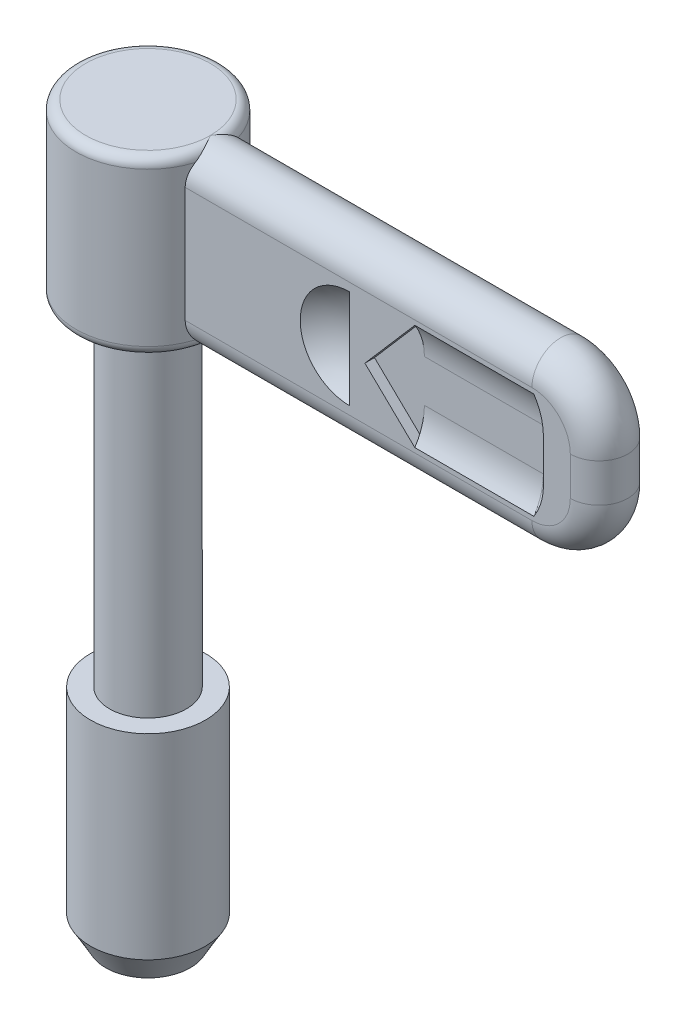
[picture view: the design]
ISO-10303-21;
HEADER;
FILE_DESCRIPTION(('STEP AP214'),'2;1');
FILE_NAME('part.step','',(''),(''),'','','');
FILE_SCHEMA(('AUTOMOTIVE_DESIGN { 1 0 10303 214 1 1 1 1 }'));
ENDSEC;
DATA;
#1=APPLICATION_CONTEXT('core data for automotive mechanical design processes');
#2=APPLICATION_PROTOCOL_DEFINITION('international standard','automotive_design',2000,#1);
#3=PRODUCT_CONTEXT('',#1,'mechanical');
#4=PRODUCT('Part','Part','',(#3));
#5=PRODUCT_RELATED_PRODUCT_CATEGORY('part','',(#4));
#6=PRODUCT_DEFINITION_FORMATION('','',#4);
#7=PRODUCT_DEFINITION_CONTEXT('part definition',#1,'design');
#8=PRODUCT_DEFINITION('design','',#6,#7);
#9=PRODUCT_DEFINITION_SHAPE('','',#8);
#10=(LENGTH_UNIT() NAMED_UNIT(*) SI_UNIT(.MILLI.,.METRE.));
#11=(NAMED_UNIT(*) PLANE_ANGLE_UNIT() SI_UNIT($,.RADIAN.));
#12=(NAMED_UNIT(*) SI_UNIT($,.STERADIAN.) SOLID_ANGLE_UNIT());
#13=UNCERTAINTY_MEASURE_WITH_UNIT(LENGTH_MEASURE(1.E-05),#10,'distance_accuracy_value','');
#14=(GEOMETRIC_REPRESENTATION_CONTEXT(3) GLOBAL_UNCERTAINTY_ASSIGNED_CONTEXT((#13)) GLOBAL_UNIT_ASSIGNED_CONTEXT((#10,
#11,#12)) REPRESENTATION_CONTEXT('',''));
#15=CARTESIAN_POINT('',(0.,0.,0.));
#16=DIRECTION('',(0.,0.,1.));
#17=DIRECTION('',(1.,0.,0.));
#18=AXIS2_PLACEMENT_3D('',#15,#16,#17);
#19=CARTESIAN_POINT('',(15.4,25.241687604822,-1.5));
#20=DIRECTION('',(-1.,0.,0.));
#21=DIRECTION('',(0.,0.,1.));
#22=AXIS2_PLACEMENT_3D('',#19,#20,#21);
#23=PLANE('',#22);
#24=CARTESIAN_POINT('',(15.4,26.9000000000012,-4.0000000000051));
#25=DIRECTION('',(1.,0.,0.));
#26=DIRECTION('',(0.,-4.16851738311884E-13,1.));
#27=AXIS2_PLACEMENT_3D('',#24,#25,#26);
#28=CIRCLE('',#27,3.0000000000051);
#29=CARTESIAN_POINT('',(15.4,26.9,-1.));
#30=VERTEX_POINT('',#29);
#31=CARTESIAN_POINT('',(15.4,25.241687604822,-1.5));
#32=VERTEX_POINT('',#31);
#33=EDGE_CURVE('E190',#30,#32,#28,.T.);
#34=ORIENTED_EDGE('',*,*,#33,.T.);
#35=DIRECTION('',(0.,0.,1.));
#36=VECTOR('',#35,1.);
#37=CARTESIAN_POINT('',(15.4,25.241687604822,-1.5));
#38=LINE('',#37,#36);
#39=CARTESIAN_POINT('',(15.4,25.241687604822,-1.));
#40=VERTEX_POINT('',#39);
#41=EDGE_CURVE('E206',#40,#32,#38,.F.);
#42=ORIENTED_EDGE('',*,*,#41,.F.);
#43=DIRECTION('',(0.,1.,0.));
#44=VECTOR('',#43,1.);
#45=CARTESIAN_POINT('',(15.4,25.241687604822,-1.));
#46=LINE('',#45,#44);
#47=EDGE_CURVE('E207',#40,#30,#46,.T.);
#48=ORIENTED_EDGE('',*,*,#47,.T.);
#49=EDGE_LOOP('',(#34,#42,#48));
#50=FACE_BOUND('',#49,.T.);
#51=ADVANCED_FACE('F14',(#50),#23,.T.);
#52=CARTESIAN_POINT('',(3.43693177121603,25.,-1.5));
#53=DIRECTION('',(0.,0.,-1.));
#54=DIRECTION('',(0.,1.,0.));
#55=AXIS2_PLACEMENT_3D('',#52,#53,#54);
#56=PLANE('',#55);
#57=DIRECTION('',(2.18195849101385E-13,1.,0.));
#58=VECTOR('',#57,1.);
#59=CARTESIAN_POINT('',(3.43693177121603,25.,-1.5));
#60=LINE('',#59,#58);
#61=CARTESIAN_POINT('',(3.43693177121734,30.9999995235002,-1.5));
#62=VERTEX_POINT('',#61);
#63=CARTESIAN_POINT('',(3.43693177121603,25.,-1.5));
#64=VERTEX_POINT('',#63);
#65=EDGE_CURVE('E421',#62,#64,#60,.F.);
#66=ORIENTED_EDGE('',*,*,#65,.F.);
#67=DIRECTION('',(1.,2.63797795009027E-08,0.));
#68=VECTOR('',#67,1.);
#69=CARTESIAN_POINT('',(3.43693177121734,30.9999995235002,-1.5));
#70=LINE('',#69,#68);
#71=CARTESIAN_POINT('',(21.5,31.,-1.5));
#72=VERTEX_POINT('',#71);
#73=EDGE_CURVE('E439',#62,#72,#70,.T.);
#74=ORIENTED_EDGE('',*,*,#73,.T.);
#75=CARTESIAN_POINT('',(21.5000000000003,29.,-1.5));
#76=DIRECTION('',(0.,0.,-1.));
#77=DIRECTION('',(-1.43884903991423E-13,1.,0.));
#78=AXIS2_PLACEMENT_3D('',#75,#76,#77);
#79=CIRCLE('',#78,1.99999999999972);
#80=CARTESIAN_POINT('',(23.5,29.,-1.5));
#81=VERTEX_POINT('',#80);
#82=EDGE_CURVE('E429',#72,#81,#79,.T.);
#83=ORIENTED_EDGE('',*,*,#82,.T.);
#84=DIRECTION('',(0.,-1.,0.));
#85=VECTOR('',#84,1.);
#86=CARTESIAN_POINT('',(23.5,29.,-1.5));
#87=LINE('',#86,#85);
#88=CARTESIAN_POINT('',(23.5,27.,-1.5));
#89=VERTEX_POINT('',#88);
#90=EDGE_CURVE('E425',#81,#89,#87,.T.);
#91=ORIENTED_EDGE('',*,*,#90,.T.);
#92=CARTESIAN_POINT('',(21.5000000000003,27.,-1.5));
#93=DIRECTION('',(0.,0.,-1.));
#94=DIRECTION('',(1.,0.,0.));
#95=AXIS2_PLACEMENT_3D('',#92,#93,#94);
#96=CIRCLE('',#95,1.99999999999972);
#97=CARTESIAN_POINT('',(21.5,25.,-1.5));
#98=VERTEX_POINT('',#97);
#99=EDGE_CURVE('E225',#89,#98,#96,.T.);
#100=ORIENTED_EDGE('',*,*,#99,.T.);
#101=DIRECTION('',(-1.,0.,0.));
#102=VECTOR('',#101,1.);
#103=CARTESIAN_POINT('',(21.5,25.,-1.5));
#104=LINE('',#103,#102);
#105=EDGE_CURVE('E222',#98,#64,#104,.T.);
#106=ORIENTED_EDGE('',*,*,#105,.T.);
#107=EDGE_LOOP('',(#66,#74,#83,#91,#100,#106));
#108=FACE_BOUND('',#107,.T.);
#109=DIRECTION('',(0.719682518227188,-0.694303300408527,0.));
#110=VECTOR('',#109,1.);
#111=CARTESIAN_POINT('',(12.8,27.75,-1.5));
#112=LINE('',#111,#110);
#113=CARTESIAN_POINT('',(12.8,27.75,-1.5));
#114=VERTEX_POINT('',#113);
#115=EDGE_CURVE('E200',#114,#32,#112,.T.);
#116=ORIENTED_EDGE('',*,*,#115,.T.);
#117=DIRECTION('',(1.,0.,0.));
#118=VECTOR('',#117,1.);
#119=CARTESIAN_POINT('',(15.4,25.241687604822,-1.5));
#120=LINE('',#119,#118);
#121=CARTESIAN_POINT('',(21.6,25.241687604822,-1.5));
#122=VERTEX_POINT('',#121);
#123=EDGE_CURVE('E186',#32,#122,#120,.T.);
#124=ORIENTED_EDGE('',*,*,#123,.T.);
#125=CARTESIAN_POINT('',(22.1,26.9000000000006,-1.5));
#126=CARTESIAN_POINT('',(22.0997802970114,26.8633870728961,-1.5));
#127=CARTESIAN_POINT('',(22.0989547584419,26.8267766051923,-1.5));
#128=CARTESIAN_POINT('',(22.0960619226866,26.7535959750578,-1.5));
#129=CARTESIAN_POINT('',(22.0939943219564,26.7170258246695,-1.5));
#130=CARTESIAN_POINT('',(22.088587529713,26.6439815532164,-1.5));
#131=CARTESIAN_POINT('',(22.0852484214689,26.6075074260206,-1.5));
#132=CARTESIAN_POINT('',(22.077276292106,26.5347099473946,-1.5));
#133=CARTESIAN_POINT('',(22.0726435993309,26.4983865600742,-1.5));
#134=CARTESIAN_POINT('',(22.0620680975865,26.4259432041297,-1.5));
#135=CARTESIAN_POINT('',(22.0561257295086,26.3898231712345,-1.5));
#136=CARTESIAN_POINT('',(22.0429212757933,26.3178373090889,-1.5));
#137=CARTESIAN_POINT('',(22.0356596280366,26.2819713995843,-1.5));
#138=CARTESIAN_POINT('',(22.0198135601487,26.2105425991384,-1.5));
#139=CARTESIAN_POINT('',(22.0112294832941,26.1749796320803,-1.5));
#140=CARTESIAN_POINT('',(21.9927421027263,26.1042035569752,-1.5));
#141=CARTESIAN_POINT('',(21.9828389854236,26.0689904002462,-1.5));
#142=CARTESIAN_POINT('',(21.9617236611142,25.9989587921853,-1.5));
#143=CARTESIAN_POINT('',(21.9505114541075,25.9641403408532,-1.5));
#144=CARTESIAN_POINT('',(21.9267946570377,25.894940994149,-1.5));
#145=CARTESIAN_POINT('',(21.9142898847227,25.8605601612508,-1.5));
#146=CARTESIAN_POINT('',(21.8880111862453,25.7922769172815,-1.5));
#147=CARTESIAN_POINT('',(21.8742369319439,25.7583746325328,-1.5));
#148=CARTESIAN_POINT('',(21.8454489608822,25.6910873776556,-1.5));
#149=CARTESIAN_POINT('',(21.830434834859,25.6577025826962,-1.5));
#150=CARTESIAN_POINT('',(21.7992031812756,25.5914872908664,-1.5));
#151=CARTESIAN_POINT('',(21.7829852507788,25.5586569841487,-1.5));
#152=CARTESIAN_POINT('',(21.7493883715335,25.4935856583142,-1.5));
#153=CARTESIAN_POINT('',(21.7320091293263,25.4613447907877,-1.5));
#154=CARTESIAN_POINT('',(21.6961380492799,25.3974858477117,-1.5));
#155=CARTESIAN_POINT('',(21.677646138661,25.3658678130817,-1.5));
#156=CARTESIAN_POINT('',(21.6396047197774,25.3032848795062,-1.5));
#157=CARTESIAN_POINT('',(21.6200554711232,25.2723198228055,-1.5));
#158=CARTESIAN_POINT('',(21.6,25.241687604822,-1.5));
#159=B_SPLINE_CURVE_WITH_KNOTS('',3,(#125,#126,#127,#128,#129,#130,#131,#132,#133,#134,#135,
#136,#137,#138,#139,#140,#141,#142,#143,#144,#145,#146,#147,#148,#149,#150,#151,#152,#153,#154,
#155,#156,#157,#158),.UNSPECIFIED.,.F.,.F.,(4,2,2,2,2,2,2,2,2,2,2,2,2,2,2,2,4),(0.,
0.109837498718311,0.219701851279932,0.329559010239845,0.439388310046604,0.549180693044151,
0.658936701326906,0.768664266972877,0.878376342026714,0.988088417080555,1.09781598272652,
1.20757199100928,1.31736437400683,1.42719367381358,1.5370508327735,1.64691518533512,
1.75675268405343),.UNSPECIFIED.);
#160=CARTESIAN_POINT('',(22.1,26.9000000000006,-1.5));
#161=VERTEX_POINT('',#160);
#162=EDGE_CURVE('E199',#161,#122,#159,.T.);
#163=ORIENTED_EDGE('',*,*,#162,.F.);
#164=DIRECTION('',(0.,1.,0.));
#165=VECTOR('',#164,1.);
#166=CARTESIAN_POINT('',(22.1,26.9000000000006,-1.5));
#167=LINE('',#166,#165);
#168=CARTESIAN_POINT('',(22.1,29.1,-1.5));
#169=VERTEX_POINT('',#168);
#170=EDGE_CURVE('E240',#161,#169,#167,.T.);
#171=ORIENTED_EDGE('',*,*,#170,.T.);
#172=CARTESIAN_POINT('',(21.6,30.758312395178,-1.5));
#173=CARTESIAN_POINT('',(21.6200554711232,30.7276801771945,-1.5));
#174=CARTESIAN_POINT('',(21.6396047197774,30.6967151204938,-1.5));
#175=CARTESIAN_POINT('',(21.677646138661,30.6341321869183,-1.5));
#176=CARTESIAN_POINT('',(21.6961380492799,30.6025141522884,-1.5));
#177=CARTESIAN_POINT('',(21.7320091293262,30.5386552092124,-1.5));
#178=CARTESIAN_POINT('',(21.7493883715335,30.5064143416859,-1.5));
#179=CARTESIAN_POINT('',(21.7829852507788,30.4413430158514,-1.5));
#180=CARTESIAN_POINT('',(21.7992031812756,30.4085127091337,-1.5));
#181=CARTESIAN_POINT('',(21.8304348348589,30.342297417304,-1.5));
#182=CARTESIAN_POINT('',(21.8454489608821,30.3089126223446,-1.5));
#183=CARTESIAN_POINT('',(21.8742369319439,30.2416253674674,-1.5));
#184=CARTESIAN_POINT('',(21.8880111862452,30.2077230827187,-1.5));
#185=CARTESIAN_POINT('',(21.9142898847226,30.1394398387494,-1.5));
#186=CARTESIAN_POINT('',(21.9267946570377,30.1050590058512,-1.5));
#187=CARTESIAN_POINT('',(21.9505114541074,30.035859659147,-1.5));
#188=CARTESIAN_POINT('',(21.9617236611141,30.001041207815,-1.5));
#189=CARTESIAN_POINT('',(21.9828389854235,29.9310095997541,-1.5));
#190=CARTESIAN_POINT('',(21.9927421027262,29.8957964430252,-1.5));
#191=CARTESIAN_POINT('',(22.011229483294,29.8250203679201,-1.5));
#192=CARTESIAN_POINT('',(22.0198135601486,29.789457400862,-1.5));
#193=CARTESIAN_POINT('',(22.0356596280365,29.7180286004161,-1.5));
#194=CARTESIAN_POINT('',(22.0429212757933,29.6821626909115,-1.5));
#195=CARTESIAN_POINT('',(22.0561257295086,29.6101768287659,-1.5));
#196=CARTESIAN_POINT('',(22.0620680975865,29.5740567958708,-1.5));
#197=CARTESIAN_POINT('',(22.0726435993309,29.5016134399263,-1.5));
#198=CARTESIAN_POINT('',(22.077276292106,29.4652900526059,-1.5));
#199=CARTESIAN_POINT('',(22.0852484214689,29.3924925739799,-1.5));
#200=CARTESIAN_POINT('',(22.088587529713,29.3560184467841,-1.5));
#201=CARTESIAN_POINT('',(22.0939943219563,29.282974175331,-1.5));
#202=CARTESIAN_POINT('',(22.0960619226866,29.2464040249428,-1.5));
#203=CARTESIAN_POINT('',(22.0989547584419,29.1732233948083,-1.5));
#204=CARTESIAN_POINT('',(22.0997802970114,29.1366129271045,-1.5));
#205=CARTESIAN_POINT('',(22.1,29.1,-1.5));
#206=B_SPLINE_CURVE_WITH_KNOTS('',3,(#172,#173,#174,#175,#176,#177,#178,#179,#180,#181,#182,
#183,#184,#185,#186,#187,#188,#189,#190,#191,#192,#193,#194,#195,#196,#197,#198,#199,#200,#201,
#202,#203,#204,#205),.UNSPECIFIED.,.F.,.F.,(4,2,2,2,2,2,2,2,2,2,2,2,2,2,2,2,4),(0.,
0.109837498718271,0.219701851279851,0.329559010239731,0.439388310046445,0.549180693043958,
0.658936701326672,0.768664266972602,0.878376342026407,0.988088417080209,1.09781598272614,
1.20757199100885,1.31736437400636,1.42719367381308,1.53705083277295,1.64691518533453,
1.7567526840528),.UNSPECIFIED.);
#207=CARTESIAN_POINT('',(21.6,30.758312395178,-1.5));
#208=VERTEX_POINT('',#207);
#209=EDGE_CURVE('E678',#208,#169,#206,.T.);
#210=ORIENTED_EDGE('',*,*,#209,.F.);
#211=DIRECTION('',(-1.,0.,0.));
#212=VECTOR('',#211,1.);
#213=CARTESIAN_POINT('',(21.6,30.758312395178,-1.5));
#214=LINE('',#213,#212);
#215=CARTESIAN_POINT('',(15.4,30.758312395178,-1.5));
#216=VERTEX_POINT('',#215);
#217=EDGE_CURVE('E1399',#216,#208,#214,.F.);
#218=ORIENTED_EDGE('',*,*,#217,.F.);
#219=DIRECTION('',(-0.653895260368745,-0.756585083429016,0.));
#220=VECTOR('',#219,1.);
#221=CARTESIAN_POINT('',(15.4,30.758312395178,-1.5));
#222=LINE('',#221,#220);
#223=EDGE_CURVE('E221',#216,#114,#222,.T.);
#224=ORIENTED_EDGE('',*,*,#223,.T.);
#225=EDGE_LOOP('',(#116,#124,#163,#171,#210,#218,#224));
#226=FACE_BOUND('',#225,.T.);
#227=DIRECTION('',(0.,1.,0.));
#228=VECTOR('',#227,1.);
#229=CARTESIAN_POINT('',(12.,25.430953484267,-1.5));
#230=LINE('',#229,#228);
#231=CARTESIAN_POINT('',(12.,25.430953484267,-1.5));
#232=VERTEX_POINT('',#231);
#233=CARTESIAN_POINT('',(12.,30.569046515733,-1.5));
#234=VERTEX_POINT('',#233);
#235=EDGE_CURVE('E1397',#232,#234,#230,.T.);
#236=ORIENTED_EDGE('',*,*,#235,.T.);
#237=CARTESIAN_POINT('',(12.,30.569046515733,-1.5));
#238=CARTESIAN_POINT('',(11.8604662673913,30.569046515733,-1.5));
#239=CARTESIAN_POINT('',(11.7251672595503,30.558257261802,-1.5));
#240=CARTESIAN_POINT('',(11.4614528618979,30.5161788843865,-1.5));
#241=CARTESIAN_POINT('',(11.3330374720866,30.4848897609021,-1.5));
#242=CARTESIAN_POINT('',(10.9180636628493,30.349608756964,-1.5));
#243=CARTESIAN_POINT('',(10.6751190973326,30.2176773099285,-1.5));
#244=CARTESIAN_POINT('',(10.1926951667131,29.8569578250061,-1.5));
#245=CARTESIAN_POINT('',(9.96213756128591,29.6004957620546,-1.5));
#246=CARTESIAN_POINT('',(9.19003735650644,28.3008382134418,-1.5));
#247=CARTESIAN_POINT('',(9.35292610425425,27.0138934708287,-1.5));
#248=CARTESIAN_POINT('',(10.3717569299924,25.9950626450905,-1.5));
#249=CARTESIAN_POINT('',(10.5851466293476,25.8366086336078,-1.5));
#250=CARTESIAN_POINT('',(11.0064475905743,25.6232428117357,-1.5));
#251=CARTESIAN_POINT('',(11.1899669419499,25.55356956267,-1.5));
#252=CARTESIAN_POINT('',(11.58418094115,25.4558125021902,-1.5));
#253=CARTESIAN_POINT('',(11.7896180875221,25.4309534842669,-1.5));
#254=CARTESIAN_POINT('',(12.,25.4309534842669,-1.5));
#255=B_SPLINE_CURVE_WITH_KNOTS('',3,(#237,#238,#239,#240,#241,#242,#243,#244,#245,#246,#247,
#248,#249,#250,#251,#252,#253,#254),.UNSPECIFIED.,.F.,.F.,(4,2,2,2,2,2,2,2,4),(0.,
0.042961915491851,0.0859238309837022,0.184717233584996,0.310914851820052,0.758114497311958,
0.859535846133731,0.928561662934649,1.),.UNSPECIFIED.);
#256=EDGE_CURVE('E274',#234,#232,#255,.T.);
#257=ORIENTED_EDGE('',*,*,#256,.T.);
#258=EDGE_LOOP('',(#236,#257));
#259=FACE_BOUND('',#258,.T.);
#260=ADVANCED_FACE('F217',(#108,#226,#259),#56,.T.);
#261=CARTESIAN_POINT('',(3.43693177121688,25.,1.5));
#262=DIRECTION('',(0.,0.,1.));
#263=DIRECTION('',(1.,0.,0.));
#264=AXIS2_PLACEMENT_3D('',#261,#262,#263);
#265=PLANE('',#264);
#266=DIRECTION('',(-1.,-1.82876122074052E-08,0.));
#267=VECTOR('',#266,1.);
#268=CARTESIAN_POINT('',(21.5,31.,1.5));
#269=LINE('',#268,#267);
#270=CARTESIAN_POINT('',(21.5,31.,1.5));
#271=VERTEX_POINT('',#270);
#272=CARTESIAN_POINT('',(3.4369317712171,30.9999996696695,1.5));
#273=VERTEX_POINT('',#272);
#274=EDGE_CURVE('E265',#271,#273,#269,.T.);
#275=ORIENTED_EDGE('',*,*,#274,.T.);
#276=DIRECTION('',(0.,-1.,0.));
#277=VECTOR('',#276,1.);
#278=CARTESIAN_POINT('',(3.4369317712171,30.9999996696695,1.5));
#279=LINE('',#278,#277);
#280=CARTESIAN_POINT('',(3.43693177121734,25.0000004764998,1.5));
#281=VERTEX_POINT('',#280);
#282=EDGE_CURVE('E273',#273,#281,#279,.T.);
#283=ORIENTED_EDGE('',*,*,#282,.T.);
#284=DIRECTION('',(1.,-2.63797796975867E-08,0.));
#285=VECTOR('',#284,1.);
#286=CARTESIAN_POINT('',(3.43693177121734,25.0000004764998,1.5));
#287=LINE('',#286,#285);
#288=CARTESIAN_POINT('',(21.5,25.,1.5));
#289=VERTEX_POINT('',#288);
#290=EDGE_CURVE('E279',#281,#289,#287,.T.);
#291=ORIENTED_EDGE('',*,*,#290,.T.);
#292=CARTESIAN_POINT('',(21.5000000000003,27.,1.5));
#293=DIRECTION('',(0.,0.,1.));
#294=DIRECTION('',(-1.59872115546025E-13,-1.,0.));
#295=AXIS2_PLACEMENT_3D('',#292,#293,#294);
#296=CIRCLE('',#295,1.99999999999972);
#297=CARTESIAN_POINT('',(23.5,27.,1.5));
#298=VERTEX_POINT('',#297);
#299=EDGE_CURVE('E284',#289,#298,#296,.T.);
#300=ORIENTED_EDGE('',*,*,#299,.T.);
#301=DIRECTION('',(0.,1.,0.));
#302=VECTOR('',#301,1.);
#303=CARTESIAN_POINT('',(23.5,27.,1.5));
#304=LINE('',#303,#302);
#305=CARTESIAN_POINT('',(23.5,29.,1.5));
#306=VERTEX_POINT('',#305);
#307=EDGE_CURVE('E289',#298,#306,#304,.T.);
#308=ORIENTED_EDGE('',*,*,#307,.T.);
#309=CARTESIAN_POINT('',(21.5000000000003,29.,1.5));
#310=DIRECTION('',(0.,0.,1.));
#311=DIRECTION('',(1.,0.,0.));
#312=AXIS2_PLACEMENT_3D('',#309,#310,#311);
#313=CIRCLE('',#312,1.99999999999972);
#314=EDGE_CURVE('E294',#306,#271,#313,.T.);
#315=ORIENTED_EDGE('',*,*,#314,.T.);
#316=EDGE_LOOP('',(#275,#283,#291,#300,#308,#315));
#317=FACE_BOUND('',#316,.T.);
#318=DIRECTION('',(0.653895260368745,0.756585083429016,0.));
#319=VECTOR('',#318,1.);
#320=CARTESIAN_POINT('',(12.8,27.75,1.5));
#321=LINE('',#320,#319);
#322=CARTESIAN_POINT('',(15.4,30.758312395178,1.5));
#323=VERTEX_POINT('',#322);
#324=CARTESIAN_POINT('',(12.8,27.75,1.5));
#325=VERTEX_POINT('',#324);
#326=EDGE_CURVE('E299',#323,#325,#321,.F.);
#327=ORIENTED_EDGE('',*,*,#326,.F.);
#328=DIRECTION('',(1.,0.,0.));
#329=VECTOR('',#328,1.);
#330=CARTESIAN_POINT('',(15.4,30.758312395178,1.5));
#331=LINE('',#330,#329);
#332=CARTESIAN_POINT('',(21.6,30.758312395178,1.5));
#333=VERTEX_POINT('',#332);
#334=EDGE_CURVE('E304',#323,#333,#331,.T.);
#335=ORIENTED_EDGE('',*,*,#334,.T.);
#336=CARTESIAN_POINT('',(22.1,29.0999999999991,1.5));
#337=CARTESIAN_POINT('',(22.0997802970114,29.1366129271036,1.5));
#338=CARTESIAN_POINT('',(22.0989547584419,29.1732233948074,1.5));
#339=CARTESIAN_POINT('',(22.0960619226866,29.246404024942,1.5));
#340=CARTESIAN_POINT('',(22.0939943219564,29.2829741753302,1.5));
#341=CARTESIAN_POINT('',(22.088587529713,29.3560184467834,1.5));
#342=CARTESIAN_POINT('',(22.085248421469,29.3924925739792,1.5));
#343=CARTESIAN_POINT('',(22.0772762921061,29.4652900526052,1.5));
#344=CARTESIAN_POINT('',(22.072643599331,29.5016134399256,1.5));
#345=CARTESIAN_POINT('',(22.0620680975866,29.5740567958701,1.5));
#346=CARTESIAN_POINT('',(22.0561257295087,29.6101768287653,1.5));
#347=CARTESIAN_POINT('',(22.0429212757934,29.6821626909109,1.5));
#348=CARTESIAN_POINT('',(22.0356596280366,29.7180286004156,1.5));
#349=CARTESIAN_POINT('',(22.0198135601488,29.7894574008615,1.5));
#350=CARTESIAN_POINT('',(22.0112294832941,29.8250203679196,1.5));
#351=CARTESIAN_POINT('',(21.9927421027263,29.8957964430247,1.5));
#352=CARTESIAN_POINT('',(21.9828389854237,29.9310095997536,1.5));
#353=CARTESIAN_POINT('',(21.9617236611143,30.0010412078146,1.5));
#354=CARTESIAN_POINT('',(21.9505114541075,30.0358596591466,1.5));
#355=CARTESIAN_POINT('',(21.9267946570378,30.1050590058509,1.5));
#356=CARTESIAN_POINT('',(21.9142898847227,30.1394398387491,1.5));
#357=CARTESIAN_POINT('',(21.8880111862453,30.2077230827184,1.5));
#358=CARTESIAN_POINT('',(21.874236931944,30.2416253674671,1.5));
#359=CARTESIAN_POINT('',(21.8454489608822,30.3089126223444,1.5));
#360=CARTESIAN_POINT('',(21.830434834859,30.3422974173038,1.5));
#361=CARTESIAN_POINT('',(21.7992031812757,30.4085127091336,1.5));
#362=CARTESIAN_POINT('',(21.7829852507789,30.4413430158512,1.5));
#363=CARTESIAN_POINT('',(21.7493883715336,30.5064143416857,1.5));
#364=CARTESIAN_POINT('',(21.7320091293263,30.5386552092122,1.5));
#365=CARTESIAN_POINT('',(21.6961380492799,30.6025141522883,1.5));
#366=CARTESIAN_POINT('',(21.677646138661,30.6341321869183,1.5));
#367=CARTESIAN_POINT('',(21.6396047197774,30.6967151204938,1.5));
#368=CARTESIAN_POINT('',(21.6200554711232,30.7276801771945,1.5));
#369=CARTESIAN_POINT('',(21.6,30.758312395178,1.5));
#370=B_SPLINE_CURVE_WITH_KNOTS('',3,(#336,#337,#338,#339,#340,#341,#342,#343,#344,#345,#346,
#347,#348,#349,#350,#351,#352,#353,#354,#355,#356,#357,#358,#359,#360,#361,#362,#363,#364,#365,
#366,#367,#368,#369),.UNSPECIFIED.,.F.,.F.,(4,2,2,2,2,2,2,2,2,2,2,2,2,2,2,2,4),(0.,
0.109837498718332,0.21970185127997,0.329559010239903,0.439388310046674,0.549180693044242,
0.658936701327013,0.768664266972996,0.878376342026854,0.988088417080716,1.0978159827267,
1.20757199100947,1.31736437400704,1.42719367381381,1.53705083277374,1.64691518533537,
1.7567526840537),.UNSPECIFIED.);
#371=CARTESIAN_POINT('',(22.1,29.0999999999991,1.5));
#372=VERTEX_POINT('',#371);
#373=EDGE_CURVE('E309',#372,#333,#370,.T.);
#374=ORIENTED_EDGE('',*,*,#373,.F.);
#375=DIRECTION('',(0.,-1.,0.));
#376=VECTOR('',#375,1.);
#377=CARTESIAN_POINT('',(22.1,29.0999999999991,1.5));
#378=LINE('',#377,#376);
#379=CARTESIAN_POINT('',(22.1,26.9,1.5));
#380=VERTEX_POINT('',#379);
#381=EDGE_CURVE('E319',#372,#380,#378,.T.);
#382=ORIENTED_EDGE('',*,*,#381,.T.);
#383=CARTESIAN_POINT('',(21.6,25.241687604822,1.5));
#384=CARTESIAN_POINT('',(21.6200554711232,25.2723198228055,1.5));
#385=CARTESIAN_POINT('',(21.6396047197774,25.3032848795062,1.5));
#386=CARTESIAN_POINT('',(21.677646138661,25.3658678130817,1.5));
#387=CARTESIAN_POINT('',(21.6961380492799,25.3974858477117,1.5));
#388=CARTESIAN_POINT('',(21.7320091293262,25.4613447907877,1.5));
#389=CARTESIAN_POINT('',(21.7493883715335,25.4935856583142,1.5));
#390=CARTESIAN_POINT('',(21.7829852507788,25.5586569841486,1.5));
#391=CARTESIAN_POINT('',(21.7992031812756,25.5914872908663,1.5));
#392=CARTESIAN_POINT('',(21.830434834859,25.6577025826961,1.5));
#393=CARTESIAN_POINT('',(21.8454489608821,25.6910873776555,1.5));
#394=CARTESIAN_POINT('',(21.8742369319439,25.7583746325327,1.5));
#395=CARTESIAN_POINT('',(21.8880111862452,25.7922769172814,1.5));
#396=CARTESIAN_POINT('',(21.9142898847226,25.8605601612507,1.5));
#397=CARTESIAN_POINT('',(21.9267946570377,25.8949409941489,1.5));
#398=CARTESIAN_POINT('',(21.9505114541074,25.9641403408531,1.5));
#399=CARTESIAN_POINT('',(21.9617236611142,25.9989587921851,1.5));
#400=CARTESIAN_POINT('',(21.9828389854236,26.0689904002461,1.5));
#401=CARTESIAN_POINT('',(21.9927421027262,26.104203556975,1.5));
#402=CARTESIAN_POINT('',(22.011229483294,26.1749796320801,1.5));
#403=CARTESIAN_POINT('',(22.0198135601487,26.2105425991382,1.5));
#404=CARTESIAN_POINT('',(22.0356596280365,26.281971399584,1.5));
#405=CARTESIAN_POINT('',(22.0429212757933,26.3178373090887,1.5));
#406=CARTESIAN_POINT('',(22.0561257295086,26.3898231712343,1.5));
#407=CARTESIAN_POINT('',(22.0620680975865,26.4259432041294,1.5));
#408=CARTESIAN_POINT('',(22.0726435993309,26.4983865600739,1.5));
#409=CARTESIAN_POINT('',(22.077276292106,26.5347099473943,1.5));
#410=CARTESIAN_POINT('',(22.0852484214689,26.6075074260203,1.5));
#411=CARTESIAN_POINT('',(22.088587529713,26.6439815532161,1.5));
#412=CARTESIAN_POINT('',(22.0939943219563,26.7170258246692,1.5));
#413=CARTESIAN_POINT('',(22.0960619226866,26.7535959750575,1.5));
#414=CARTESIAN_POINT('',(22.0989547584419,26.826776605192,1.5));
#415=CARTESIAN_POINT('',(22.0997802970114,26.8633870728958,1.5));
#416=CARTESIAN_POINT('',(22.1,26.9000000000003,1.5));
#417=B_SPLINE_CURVE_WITH_KNOTS('',3,(#383,#384,#385,#386,#387,#388,#389,#390,#391,#392,#393,
#394,#395,#396,#397,#398,#399,#400,#401,#402,#403,#404,#405,#406,#407,#408,#409,#410,#411,#412,
#413,#414,#415,#416),.UNSPECIFIED.,.F.,.F.,(4,2,2,2,2,2,2,2,2,2,2,2,2,2,2,2,4),(0.,
0.109837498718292,0.219701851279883,0.329559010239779,0.439388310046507,0.549180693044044,
0.658936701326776,0.768664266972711,0.878376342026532,0.988088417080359,1.0978159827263,
1.20757199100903,1.31736437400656,1.42719367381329,1.53705083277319,1.64691518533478,
1.75675268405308),.UNSPECIFIED.);
#418=CARTESIAN_POINT('',(21.6,25.241687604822,1.5));
#419=VERTEX_POINT('',#418);
#420=EDGE_CURVE('E326',#419,#380,#417,.T.);
#421=ORIENTED_EDGE('',*,*,#420,.F.);
#422=DIRECTION('',(-1.,0.,0.));
#423=VECTOR('',#422,1.);
#424=CARTESIAN_POINT('',(21.6,25.241687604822,1.5));
#425=LINE('',#424,#423);
#426=CARTESIAN_POINT('',(15.4,25.241687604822,1.5));
#427=VERTEX_POINT('',#426);
#428=EDGE_CURVE('E336',#427,#419,#425,.F.);
#429=ORIENTED_EDGE('',*,*,#428,.F.);
#430=DIRECTION('',(-0.719682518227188,0.694303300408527,0.));
#431=VECTOR('',#430,1.);
#432=CARTESIAN_POINT('',(15.4,25.241687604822,1.5));
#433=LINE('',#432,#431);
#434=EDGE_CURVE('E343',#325,#427,#433,.F.);
#435=ORIENTED_EDGE('',*,*,#434,.F.);
#436=EDGE_LOOP('',(#327,#335,#374,#382,#421,#429,#435));
#437=FACE_BOUND('',#436,.T.);
#438=CARTESIAN_POINT('',(12.,30.569046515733,1.5));
#439=CARTESIAN_POINT('',(11.9582370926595,30.5690491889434,1.50000165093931));
#440=CARTESIAN_POINT('',(11.9164737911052,30.5680358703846,1.50000705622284));
#441=CARTESIAN_POINT('',(11.8333649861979,30.5639908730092,1.50001785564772));
#442=CARTESIAN_POINT('',(11.7920187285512,30.5609746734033,1.5000232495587));
#443=CARTESIAN_POINT('',(11.7097099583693,30.552955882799,1.50002675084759));
#444=CARTESIAN_POINT('',(11.6687465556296,30.5479624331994,1.50002489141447));
#445=CARTESIAN_POINT('',(11.5871842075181,30.5360141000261,1.50001585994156));
#446=CARTESIAN_POINT('',(11.5465847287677,30.5290628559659,1.50000869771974));
#447=CARTESIAN_POINT('',(11.4657484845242,30.5132128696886,1.49999399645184));
#448=CARTESIAN_POINT('',(11.4255118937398,30.5043132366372,1.49998645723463));
#449=CARTESIAN_POINT('',(11.3454198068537,30.4845716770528,1.49997618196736));
#450=CARTESIAN_POINT('',(11.3055654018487,30.4737253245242,1.49997345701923));
#451=CARTESIAN_POINT('',(11.2262777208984,30.4500884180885,1.49997532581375));
#452=CARTESIAN_POINT('',(11.1868465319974,30.4372908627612,1.49997994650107));
#453=CARTESIAN_POINT('',(11.1084689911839,30.4097413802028,1.49999065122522));
#454=CARTESIAN_POINT('',(11.0695257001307,30.3949807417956,1.49999674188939));
#455=CARTESIAN_POINT('',(10.9923719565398,30.3635644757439,1.50000265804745));
#456=CARTESIAN_POINT('',(10.9541621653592,30.3469072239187,1.50000247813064));
#457=CARTESIAN_POINT('',(10.8787589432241,30.3118282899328,1.50000176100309));
#458=CARTESIAN_POINT('',(10.8415618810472,30.2934144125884,1.50000122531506));
#459=CARTESIAN_POINT('',(10.7681900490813,30.2548440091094,1.49999346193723));
#460=CARTESIAN_POINT('',(10.7320131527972,30.2346915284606,1.49998624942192));
#461=CARTESIAN_POINT('',(10.66070034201,30.19267111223,1.49996757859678));
#462=CARTESIAN_POINT('',(10.6255637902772,30.1708042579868,1.49995612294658));
#463=CARTESIAN_POINT('',(10.5563669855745,30.1253840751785,1.49993212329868));
#464=CARTESIAN_POINT('',(10.5223074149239,30.1018297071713,1.49991957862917));
#465=CARTESIAN_POINT('',(10.4553136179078,30.0530680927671,1.49989741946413));
#466=CARTESIAN_POINT('',(10.4223811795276,30.0278583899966,1.49988780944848));
#467=CARTESIAN_POINT('',(10.3577022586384,29.9758249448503,1.49987495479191));
#468=CARTESIAN_POINT('',(10.3259584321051,29.9489979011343,1.4998717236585));
#469=CARTESIAN_POINT('',(10.2637264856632,29.8937748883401,1.49987396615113));
#470=CARTESIAN_POINT('',(10.2332416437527,29.865375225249,1.49987946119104));
#471=CARTESIAN_POINT('',(10.1736041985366,29.8070590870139,1.49990005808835));
#472=CARTESIAN_POINT('',(10.1444552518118,29.7771388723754,1.49991518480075));
#473=CARTESIAN_POINT('',(10.0875705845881,29.7158413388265,1.49995446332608));
#474=CARTESIAN_POINT('',(10.0598386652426,29.6844604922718,1.49997863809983));
#475=CARTESIAN_POINT('',(10.0058712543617,29.6203094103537,1.50003408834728));
#476=CARTESIAN_POINT('',(9.97963948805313,29.5875360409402,1.50006538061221));
#477=CARTESIAN_POINT('',(9.92875566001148,29.5206758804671,1.50013208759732));
#478=CARTESIAN_POINT('',(9.90410704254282,29.4865864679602,1.50016751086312));
#479=CARTESIAN_POINT('',(9.85647084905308,29.4171785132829,1.50023883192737));
#480=CARTESIAN_POINT('',(9.83348624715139,29.3818579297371,1.50027473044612));
#481=CARTESIAN_POINT('',(9.78925560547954,29.3100801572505,1.50034312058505));
#482=CARTESIAN_POINT('',(9.76801189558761,29.2736215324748,1.50037560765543));
#483=CARTESIAN_POINT('',(9.72733501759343,29.1996681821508,1.50043350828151));
#484=CARTESIAN_POINT('',(9.70790337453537,29.1621726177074,1.50045891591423));
#485=CARTESIAN_POINT('',(9.67091550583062,29.0862534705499,1.50049963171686));
#486=CARTESIAN_POINT('',(9.65335985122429,29.0478296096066,1.50051493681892));
#487=CARTESIAN_POINT('',(9.62018033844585,28.9701689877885,1.50053343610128));
#488=CARTESIAN_POINT('',(9.60455595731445,28.9309324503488,1.50053663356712));
#489=CARTESIAN_POINT('',(9.5752856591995,28.85176796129,1.50053021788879));
#490=CARTESIAN_POINT('',(9.56163799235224,28.8118406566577,1.50052061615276));
#491=CARTESIAN_POINT('',(9.53635704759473,28.7314217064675,1.50048941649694));
#492=CARTESIAN_POINT('',(9.52472066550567,28.6909310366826,1.50046783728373));
#493=CARTESIAN_POINT('',(9.50348663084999,28.6095171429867,1.5004151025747));
#494=CARTESIAN_POINT('',(9.49388439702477,28.5685951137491,1.50038396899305));
#495=CARTESIAN_POINT('',(9.4767307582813,28.4864540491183,1.50031613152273));
#496=CARTESIAN_POINT('',(9.469173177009,28.4452363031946,1.50027944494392));
#497=CARTESIAN_POINT('',(9.45610826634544,28.362642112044,1.50020592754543));
#498=CARTESIAN_POINT('',(9.45059305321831,28.3212669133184,1.50016909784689));
#499=CARTESIAN_POINT('',(9.44159928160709,28.238497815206,1.50010194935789));
#500=CARTESIAN_POINT('',(9.43811102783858,28.1971049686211,1.50007160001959));
#501=CARTESIAN_POINT('',(9.43314479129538,28.1144412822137,1.50002464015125));
#502=CARTESIAN_POINT('',(9.43165520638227,28.0731711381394,1.50000795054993));
#503=CARTESIAN_POINT('',(9.4306439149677,27.9907111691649,1.49999662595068));
#504=CARTESIAN_POINT('',(9.4311172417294,27.9495214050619,1.50000193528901));
#505=CARTESIAN_POINT('',(9.43403811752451,27.8669064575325,1.5000273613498));
#506=CARTESIAN_POINT('',(9.43650025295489,27.8254817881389,1.50004758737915));
#507=CARTESIAN_POINT('',(9.44344068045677,27.7425213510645,1.50009759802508));
#508=CARTESIAN_POINT('',(9.44793240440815,27.7009867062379,1.5001274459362));
#509=CARTESIAN_POINT('',(9.4589618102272,27.6179533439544,1.50019123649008));
#510=CARTESIAN_POINT('',(9.4655107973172,27.5764561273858,1.50022520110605));
#511=CARTESIAN_POINT('',(9.48067047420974,27.4936440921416,1.50029243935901));
#512=CARTESIAN_POINT('',(9.48929043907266,27.4523309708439,1.50032570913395));
#513=CARTESIAN_POINT('',(9.50859396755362,27.3700318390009,1.50038770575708));
#514=CARTESIAN_POINT('',(9.5192848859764,27.3290475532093,1.50041641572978));
#515=CARTESIAN_POINT('',(9.54271864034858,27.2475479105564,1.50046665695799));
#516=CARTESIAN_POINT('',(9.55546703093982,27.2070341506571,1.50048816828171));
#517=CARTESIAN_POINT('',(9.58299100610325,27.1266133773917,1.50052270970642));
#518=CARTESIAN_POINT('',(9.59777047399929,27.0867076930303,1.50053572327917));
#519=CARTESIAN_POINT('',(9.62931957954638,27.0076358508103,1.50055330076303));
#520=CARTESIAN_POINT('',(9.64609156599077,26.968470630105,1.50055785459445));
#521=CARTESIAN_POINT('',(9.68157734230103,26.8910065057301,1.50055975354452));
#522=CARTESIAN_POINT('',(9.70029209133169,26.8527080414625,1.50055709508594));
#523=CARTESIAN_POINT('',(9.73960485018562,26.777097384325,1.50054678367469));
#524=CARTESIAN_POINT('',(9.76020258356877,26.7397850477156,1.50053913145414));
#525=CARTESIAN_POINT('',(9.80321395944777,26.6662590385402,1.50052168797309));
#526=CARTESIAN_POINT('',(9.82562625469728,26.6300445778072,1.50051189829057));
#527=CARTESIAN_POINT('',(9.87219215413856,26.5588185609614,1.50049327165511));
#528=CARTESIAN_POINT('',(9.89634351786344,26.5238055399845,1.50048443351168));
#529=CARTESIAN_POINT('',(9.94630745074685,26.455078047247,1.50047058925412));
#530=CARTESIAN_POINT('',(9.97211707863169,26.4213614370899,1.50046557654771));
#531=CARTESIAN_POINT('',(10.0253138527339,26.3553135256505,1.50046159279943));
#532=CARTESIAN_POINT('',(10.0526975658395,26.3229794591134,1.50046260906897));
#533=CARTESIAN_POINT('',(10.1089573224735,26.2597743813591,1.50047179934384));
#534=CARTESIAN_POINT('',(10.1378296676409,26.2289000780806,1.50047995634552));
#535=CARTESIAN_POINT('',(10.1969822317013,26.1686832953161,1.50050310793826));
#536=CARTESIAN_POINT('',(10.2272587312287,26.1393371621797,1.50051808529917));
#537=CARTESIAN_POINT('',(10.2891382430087,26.0822367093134,1.50055291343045));
#538=CARTESIAN_POINT('',(10.320737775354,26.0544786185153,1.50057275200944));
#539=CARTESIAN_POINT('',(10.3851875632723,26.0006058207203,1.50061368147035));
#540=CARTESIAN_POINT('',(10.4180348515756,25.9744875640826,1.50063476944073));
#541=CARTESIAN_POINT('',(10.4849124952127,25.9239381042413,1.50067316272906));
#542=CARTESIAN_POINT('',(10.5189406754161,25.8995040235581,1.50069047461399));
#543=CARTESIAN_POINT('',(10.5881231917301,25.8523593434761,1.50071544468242));
#544=CARTESIAN_POINT('',(10.6232764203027,25.8296471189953,1.50072311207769));
#545=CARTESIAN_POINT('',(10.6946654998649,25.7859761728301,1.50072302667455));
#546=CARTESIAN_POINT('',(10.73090156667,25.7650178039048,1.50071527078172));
#547=CARTESIAN_POINT('',(10.804428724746,25.7248790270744,1.50068020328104));
#548=CARTESIAN_POINT('',(10.8417215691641,25.7057018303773,1.5006528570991));
#549=CARTESIAN_POINT('',(10.9173532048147,25.6691457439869,1.5005777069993));
#550=CARTESIAN_POINT('',(10.9556954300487,25.6517739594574,1.50052982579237));
#551=CARTESIAN_POINT('',(11.0334371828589,25.6188447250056,1.5004198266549));
#552=CARTESIAN_POINT('',(11.0728418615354,25.6032994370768,1.50035762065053));
#553=CARTESIAN_POINT('',(11.1527437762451,25.5740415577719,1.50023045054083));
#554=CARTESIAN_POINT('',(11.193247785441,25.5603474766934,1.50016546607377));
#555=CARTESIAN_POINT('',(11.2753912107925,25.5347980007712,1.50007240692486));
#556=CARTESIAN_POINT('',(11.3170385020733,25.5229679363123,1.50004480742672));
#557=CARTESIAN_POINT('',(11.400908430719,25.5013815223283,1.50002290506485));
#558=CARTESIAN_POINT('',(11.4431315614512,25.4916270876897,1.50002863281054));
#559=CARTESIAN_POINT('',(11.5278166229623,25.4743068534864,1.50003999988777));
#560=CARTESIAN_POINT('',(11.5702764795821,25.4667309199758,1.50004563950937));
#561=CARTESIAN_POINT('',(11.6554527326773,25.4537425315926,1.50005125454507));
#562=CARTESIAN_POINT('',(11.6981685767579,25.4483264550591,1.50005123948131));
#563=CARTESIAN_POINT('',(11.7838953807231,25.4396510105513,1.50004091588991));
#564=CARTESIAN_POINT('',(11.8269067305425,25.4363954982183,1.50003058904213));
#565=CARTESIAN_POINT('',(11.9132785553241,25.4320389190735,1.50001128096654));
#566=CARTESIAN_POINT('',(11.9566396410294,25.4309499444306,1.50000230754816));
#567=CARTESIAN_POINT('',(12.,25.430953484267,1.49999999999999));
#568=B_SPLINE_CURVE_WITH_KNOTS('',3,(#438,#439,#440,#441,#442,#443,#444,#445,#446,#447,#448,
#449,#450,#451,#452,#453,#454,#455,#456,#457,#458,#459,#460,#461,#462,#463,#464,#465,#466,#467,
#468,#469,#470,#471,#472,#473,#474,#475,#476,#477,#478,#479,#480,#481,#482,#483,#484,#485,#486,
#487,#488,#489,#490,#491,#492,#493,#494,#495,#496,#497,#498,#499,#500,#501,#502,#503,#504,#505,
#506,#507,#508,#509,#510,#511,#512,#513,#514,#515,#516,#517,#518,#519,#520,#521,#522,#523,#524,
#525,#526,#527,#528,#529,#530,#531,#532,#533,#534,#535,#536,#537,#538,#539,#540,#541,#542,#543,
#544,#545,#546,#547,#548,#549,#550,#551,#552,#553,#554,#555,#556,#557,#558,#559,#560,#561,#562,
#563,#564,#565,#566,#567),.UNSPECIFIED.,.F.,.F.,(4,2,2,2,2,2,2,2,2,2,2,2,2,2,2,2,2,2,2,2,2,2,2,
2,2,2,2,2,2,2,2,2,2,2,2,2,2,2,2,2,2,2,2,2,2,2,2,2,2,2,2,2,2,2,2,2,2,2,2,2,2,2,2,2,4),(0.,
0.125276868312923,0.249596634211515,0.373348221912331,0.496871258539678,0.620450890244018,
0.744315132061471,0.868634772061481,0.993525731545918,1.11852445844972,1.24299160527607,
1.36717656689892,1.49128381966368,1.61546818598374,1.73984118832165,1.86447727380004,
1.98941968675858,2.11468583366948,2.24027204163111,2.36615765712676,2.49230846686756,
2.61867944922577,2.74521688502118,2.8718598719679,2.99854129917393,3.12518834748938,
3.25172258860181,3.37805976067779,3.50410930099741,3.62977371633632,3.75494786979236,
3.8795182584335,4.00336234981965,4.12689327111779,4.25133851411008,4.37661968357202,
4.50260171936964,4.62915885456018,4.75617397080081,4.88353791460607,5.01114885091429,
5.13891173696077,5.2667380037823,5.39454553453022,5.52225902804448,5.64981083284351,
5.77714233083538,5.90420594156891,6.03096780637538,6.15741119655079,6.28354066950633,
6.40938696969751,6.53501263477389,6.66051821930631,6.78604898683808,6.91180184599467,
7.03803222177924,7.16506046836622,7.29327736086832,7.42310913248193,7.55306016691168,
7.68239653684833,7.81151511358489,7.94086349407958,8.07093180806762),.UNSPECIFIED.);
#569=CARTESIAN_POINT('',(12.,30.569046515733,1.5));
#570=VERTEX_POINT('',#569);
#571=CARTESIAN_POINT('',(12.,25.430953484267,1.5));
#572=VERTEX_POINT('',#571);
#573=EDGE_CURVE('E347',#570,#572,#568,.T.);
#574=ORIENTED_EDGE('',*,*,#573,.F.);
#575=DIRECTION('',(0.,-1.,0.));
#576=VECTOR('',#575,1.);
#577=CARTESIAN_POINT('',(12.,30.569046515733,1.5));
#578=LINE('',#577,#576);
#579=EDGE_CURVE('E358',#572,#570,#578,.F.);
#580=ORIENTED_EDGE('',*,*,#579,.F.);
#581=EDGE_LOOP('',(#574,#580));
#582=FACE_BOUND('',#581,.T.);
#583=ADVANCED_FACE('F251',(#317,#437,#582),#265,.T.);
#584=CARTESIAN_POINT('',(21.5000000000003,25.,0.));
#585=DIRECTION('',(-1.,0.,0.));
#586=DIRECTION('',(0.,1.49091509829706E-13,-1.));
#587=AXIS2_PLACEMENT_3D('',#584,#585,#586);
#588=CYLINDRICAL_SURFACE('',#587,1.5);
#589=ORIENTED_EDGE('',*,*,#290,.F.);
#590=CARTESIAN_POINT('',(3.43693177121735,25.0000004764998,1.49999999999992));
#591=CARTESIAN_POINT('',(3.43693084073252,24.976099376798,1.50000080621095));
#592=CARTESIAN_POINT('',(3.43717996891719,24.9521985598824,1.49942877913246));
#593=CARTESIAN_POINT('',(3.43816456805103,24.9048032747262,1.49716122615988));
#594=CARTESIAN_POINT('',(3.43889302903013,24.8813078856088,1.49548189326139));
#595=CARTESIAN_POINT('',(3.44081113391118,24.8347290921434,1.49104871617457));
#596=CARTESIAN_POINT('',(3.44199501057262,24.8116441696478,1.4883083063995));
#597=CARTESIAN_POINT('',(3.44479742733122,24.7658880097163,1.48179623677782));
#598=CARTESIAN_POINT('',(3.44641141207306,24.7432149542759,1.47803537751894));
#599=CARTESIAN_POINT('',(3.4500479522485,24.6982815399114,1.46951850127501));
#600=CARTESIAN_POINT('',(3.45206708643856,24.6760193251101,1.46477080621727));
#601=CARTESIAN_POINT('',(3.45648782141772,24.631904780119,1.45430969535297));
#602=CARTESIAN_POINT('',(3.45888704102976,24.6100507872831,1.4486022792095));
#603=CARTESIAN_POINT('',(3.46404197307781,24.5667489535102,1.43624456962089));
#604=CARTESIAN_POINT('',(3.46679623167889,24.5452998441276,1.42959811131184));
#605=CARTESIAN_POINT('',(3.47263538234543,24.5028039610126,1.41537880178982));
#606=CARTESIAN_POINT('',(3.47571962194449,24.481756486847,1.4078077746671));
#607=CARTESIAN_POINT('',(3.48219300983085,24.4400607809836,1.3917496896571));
#608=CARTESIAN_POINT('',(3.48558217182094,24.4194125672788,1.38326259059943));
#609=CARTESIAN_POINT('',(3.49263981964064,24.3785137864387,1.36537688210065));
#610=CARTESIAN_POINT('',(3.49630884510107,24.3582640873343,1.35597650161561));
#611=CARTESIAN_POINT('',(3.50390077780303,24.3181629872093,1.33626321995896));
#612=CARTESIAN_POINT('',(3.50782460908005,24.2983134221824,1.32594694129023));
#613=CARTESIAN_POINT('',(3.51590085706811,24.2590162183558,1.3043956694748));
#614=CARTESIAN_POINT('',(3.52005444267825,24.2395714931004,1.29315580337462));
#615=CARTESIAN_POINT('',(3.52856503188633,24.2010912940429,1.26974635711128));
#616=CARTESIAN_POINT('',(3.53292331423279,24.1820599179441,1.25757050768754));
#617=CARTESIAN_POINT('',(3.54181830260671,24.1444181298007,1.23227372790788));
#618=CARTESIAN_POINT('',(3.54635626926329,24.1258131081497,1.21914522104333));
#619=CARTESIAN_POINT('',(3.55558560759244,24.0890408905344,1.19192379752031));
#620=CARTESIAN_POINT('',(3.56027810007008,24.0708804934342,1.17782207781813));
#621=CARTESIAN_POINT('',(3.56979215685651,24.0350200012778,1.14863169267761));
#622=CARTESIAN_POINT('',(3.57461459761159,24.017328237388,1.13353307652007));
#623=CARTESIAN_POINT('',(3.5794552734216,23.9999999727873,1.11803396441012));
#624=B_SPLINE_CURVE_WITH_KNOTS('',3,(#590,#591,#592,#593,#594,#595,#596,#597,#598,#599,#600,
#601,#602,#603,#604,#605,#606,#607,#608,#609,#610,#611,#612,#613,#614,#615,#616,#617,#618,#619,
#620,#621,#622,#623),.UNSPECIFIED.,.F.,.F.,(4,2,2,2,2,2,2,2,2,2,2,2,2,2,2,2,4),(0.,
0.0716946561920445,0.142363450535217,0.212165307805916,0.281255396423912,0.349784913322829,
0.417900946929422,0.485746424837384,0.553460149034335,0.621176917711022,0.689027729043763,
0.757140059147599,0.825638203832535,0.894643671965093,0.96427561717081,1.03465129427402,
1.10588652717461),.UNSPECIFIED.);
#625=CARTESIAN_POINT('',(3.57945527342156,24.0000000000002,1.1180339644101));
#626=VERTEX_POINT('',#625);
#627=EDGE_CURVE('E365',#281,#626,#624,.T.);
#628=ORIENTED_EDGE('',*,*,#627,.T.);
#629=CARTESIAN_POINT('',(3.24999999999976,23.5,0.));
#630=CARTESIAN_POINT('',(3.2643639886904,23.5000003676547,0.024924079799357));
#631=CARTESIAN_POINT('',(3.27851851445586,23.5006190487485,0.0499723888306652));
#632=CARTESIAN_POINT('',(3.30625631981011,23.5031278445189,0.100135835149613));
#633=CARTESIAN_POINT('',(3.31984236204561,23.5050107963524,0.125249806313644));
#634=CARTESIAN_POINT('',(3.34638117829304,23.5100681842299,0.175506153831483));
#635=CARTESIAN_POINT('',(3.35933700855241,23.5132355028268,0.200647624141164));
#636=CARTESIAN_POINT('',(3.38454749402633,23.5208832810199,0.250912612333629));
#637=CARTESIAN_POINT('',(3.3968055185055,23.5253566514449,0.276035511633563));
#638=CARTESIAN_POINT('',(3.42054648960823,23.5356376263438,0.32621004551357));
#639=CARTESIAN_POINT('',(3.43203313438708,23.5414381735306,0.351261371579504));
#640=CARTESIAN_POINT('',(3.45415128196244,23.5543939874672,0.401235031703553));
#641=CARTESIAN_POINT('',(3.46478682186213,23.5615422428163,0.42615737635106));
#642=CARTESIAN_POINT('',(3.48004823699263,23.573305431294,0.463433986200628));
#643=CARTESIAN_POINT('',(3.48501169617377,23.5773916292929,0.475819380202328));
#644=CARTESIAN_POINT('',(3.49469074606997,23.5859071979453,0.500531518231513));
#645=CARTESIAN_POINT('',(3.49940690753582,23.5903357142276,0.512858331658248));
#646=CARTESIAN_POINT('',(3.50857852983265,23.599536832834,0.537443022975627));
#647=CARTESIAN_POINT('',(3.51303458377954,23.6043085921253,0.54970099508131));
#648=CARTESIAN_POINT('',(3.52167276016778,23.6141967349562,0.574137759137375));
#649=CARTESIAN_POINT('',(3.52585549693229,23.6193122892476,0.586316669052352));
#650=CARTESIAN_POINT('',(3.53393310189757,23.6298878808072,0.610584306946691));
#651=CARTESIAN_POINT('',(3.53782860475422,23.6353471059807,0.622673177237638));
#652=CARTESIAN_POINT('',(3.54531716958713,23.6466091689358,0.646749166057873));
#653=CARTESIAN_POINT('',(3.54891088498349,23.652411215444,0.6587364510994));
#654=CARTESIAN_POINT('',(3.55578064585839,23.6643571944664,0.682597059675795));
#655=CARTESIAN_POINT('',(3.55905736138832,23.6705003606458,0.694470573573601));
#656=CARTESIAN_POINT('',(3.56527724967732,23.6831258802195,0.718090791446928));
#657=CARTESIAN_POINT('',(3.56822110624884,23.6896074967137,0.729837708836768));
#658=CARTESIAN_POINT('',(3.57375877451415,23.7029061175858,0.753191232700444));
#659=CARTESIAN_POINT('',(3.57635328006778,23.7097224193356,0.764798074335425));
#660=CARTESIAN_POINT('',(3.58117514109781,23.7236853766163,0.787857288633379));
#661=CARTESIAN_POINT('',(3.58340319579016,23.7308313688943,0.799309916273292));
#662=CARTESIAN_POINT('',(3.58747448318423,23.745447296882,0.822045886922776));
#663=CARTESIAN_POINT('',(3.58931841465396,23.75291661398,0.833329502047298));
#664=CARTESIAN_POINT('',(3.59260326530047,23.7681712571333,0.855711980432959));
#665=CARTESIAN_POINT('',(3.59404487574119,23.7759560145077,0.866811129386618));
#666=CARTESIAN_POINT('',(3.59650643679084,23.7918319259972,0.888808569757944));
#667=CARTESIAN_POINT('',(3.59752706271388,23.7999225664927,0.899707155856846));
#668=CARTESIAN_POINT('',(3.59912762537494,23.816398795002,0.921286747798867));
#669=CARTESIAN_POINT('',(3.59970821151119,23.8247839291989,0.931968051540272));
#670=CARTESIAN_POINT('',(3.60040937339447,23.8418356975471,0.953095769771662));
#671=CARTESIAN_POINT('',(3.60053056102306,23.8505019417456,0.963542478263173));
#672=CARTESIAN_POINT('',(3.60029342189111,23.8681003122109,0.984183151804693));
#673=CARTESIAN_POINT('',(3.59993565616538,23.8770321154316,0.994377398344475));
#674=CARTESIAN_POINT('',(3.59872104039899,23.8951436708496,1.01449480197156));
#675=CARTESIAN_POINT('',(3.59786468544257,23.9043231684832,1.02441821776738));
#676=CARTESIAN_POINT('',(3.59563342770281,23.922909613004,1.04397518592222));
#677=CARTESIAN_POINT('',(3.59425893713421,23.9323163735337,1.05360896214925));
#678=CARTESIAN_POINT('',(3.59097210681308,23.9513344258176,1.07256753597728));
#679=CARTESIAN_POINT('',(3.58906007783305,23.9609455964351,1.08189250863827));
#680=CARTESIAN_POINT('',(3.58467961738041,23.980345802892,1.10021408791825));
#681=CARTESIAN_POINT('',(3.58221137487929,23.9901347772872,1.10921080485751));
#682=CARTESIAN_POINT('',(3.57945527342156,23.9999999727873,1.11803396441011));
#683=B_SPLINE_CURVE_WITH_KNOTS('',3,(#629,#630,#631,#632,#633,#634,#635,#636,#637,#638,#639,
#640,#641,#642,#643,#644,#645,#646,#647,#648,#649,#650,#651,#652,#653,#654,#655,#656,#657,#658,
#659,#660,#661,#662,#663,#664,#665,#666,#667,#668,#669,#670,#671,#672,#673,#674,#675,#676,#677,
#678,#679,#680,#681,#682),.UNSPECIFIED.,.F.,.F.,(4,2,2,2,2,2,2,2,2,2,2,2,2,2,2,2,2,2,2,2,2,2,2,
2,2,2,4),(0.,0.0862975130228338,0.172110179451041,0.257453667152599,0.342342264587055,
0.426789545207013,0.510809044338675,0.552667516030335,0.59442469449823,0.636082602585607,
0.677643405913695,0.719109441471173,0.760483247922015,0.801767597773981,0.842965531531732,
0.884080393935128,0.925115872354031,0.966076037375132,1.00696538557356,1.04778888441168,
1.08855201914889,1.12926084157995,1.16992202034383,1.21054289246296,1.25113151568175,
1.29169672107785,1.33224816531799),.UNSPECIFIED.);
#684=CARTESIAN_POINT('',(3.25,23.5,0.));
#685=VERTEX_POINT('',#684);
#686=EDGE_CURVE('E610',#685,#626,#683,.T.);
#687=ORIENTED_EDGE('',*,*,#686,.F.);
#688=CARTESIAN_POINT('',(3.57945533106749,23.9999997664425,-1.11803377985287));
#689=CARTESIAN_POINT('',(3.58221153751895,23.9901341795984,-1.10921026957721));
#690=CARTESIAN_POINT('',(3.58467985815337,23.9803448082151,-1.1002131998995));
#691=CARTESIAN_POINT('',(3.58906040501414,23.9609438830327,-1.08189098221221));
#692=CARTESIAN_POINT('',(3.59097244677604,23.9513323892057,-1.07256572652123));
#693=CARTESIAN_POINT('',(3.5942592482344,23.9323137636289,-1.05360665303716));
#694=CARTESIAN_POINT('',(3.59563370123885,23.9229067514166,-1.04397266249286));
#695=CARTESIAN_POINT('',(3.59786484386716,23.9043198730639,-1.02441533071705));
#696=CARTESIAN_POINT('',(3.59872112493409,23.8951401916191,-1.01449176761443));
#697=CARTESIAN_POINT('',(3.59993556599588,23.8770283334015,-0.994374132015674));
#698=CARTESIAN_POINT('',(3.60029323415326,23.8680964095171,-0.984179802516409));
#699=CARTESIAN_POINT('',(3.60053016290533,23.8504978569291,-0.963539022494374));
#700=CARTESIAN_POINT('',(3.60040886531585,23.8418315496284,-0.953092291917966));
#701=CARTESIAN_POINT('',(3.59970747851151,23.8247797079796,-0.931964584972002));
#702=CARTESIAN_POINT('',(3.59912677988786,23.816394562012,-0.921283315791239));
#703=CARTESIAN_POINT('',(3.59752599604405,23.7999183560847,-0.89970384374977));
#704=CARTESIAN_POINT('',(3.59650526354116,23.7918277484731,-0.888805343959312));
#705=CARTESIAN_POINT('',(3.59404350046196,23.7759519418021,-0.866808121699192));
#706=CARTESIAN_POINT('',(3.59260179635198,23.7681672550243,-0.855709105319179));
#707=CARTESIAN_POINT('',(3.58931677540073,23.7529127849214,-0.833326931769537));
#708=CARTESIAN_POINT('',(3.58747276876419,23.745443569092,-0.82204348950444));
#709=CARTESIAN_POINT('',(3.58340135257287,23.7308278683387,-0.799307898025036));
#710=CARTESIAN_POINT('',(3.58117324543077,23.723682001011,-0.787855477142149));
#711=CARTESIAN_POINT('',(3.57635130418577,23.7097193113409,-0.764796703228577));
#712=CARTESIAN_POINT('',(3.57375677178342,23.7029031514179,-0.753190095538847));
#713=CARTESIAN_POINT('',(3.56821907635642,23.6896048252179,-0.729837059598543));
#714=CARTESIAN_POINT('',(3.56527522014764,23.6831233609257,-0.718090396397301));
#715=CARTESIAN_POINT('',(3.55905535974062,23.6704981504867,-0.694470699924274));
#716=CARTESIAN_POINT('',(3.55577867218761,23.664355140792,-0.682597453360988));
#717=CARTESIAN_POINT('',(3.5489089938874,23.6524094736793,-0.658737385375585));
#718=CARTESIAN_POINT('',(3.54531533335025,23.6466075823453,-0.646750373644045));
#719=CARTESIAN_POINT('',(3.5378269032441,23.6353458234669,-0.622674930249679));
#720=CARTESIAN_POINT('',(3.53393148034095,23.6298867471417,-0.610586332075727));
#721=CARTESIAN_POINT('',(3.52585405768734,23.6193114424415,-0.586319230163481));
#722=CARTESIAN_POINT('',(3.52167142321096,23.614196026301,-0.574140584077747));
#723=CARTESIAN_POINT('',(3.51303347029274,23.6043081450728,-0.549704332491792));
#724=CARTESIAN_POINT('',(3.50857753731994,23.5995365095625,-0.537446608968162));
#725=CARTESIAN_POINT('',(3.49940617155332,23.590335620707,-0.512862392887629));
#726=CARTESIAN_POINT('',(3.49469014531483,23.5859072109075,-0.500535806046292));
#727=CARTESIAN_POINT('',(3.48501137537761,23.5773918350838,-0.47582409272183));
#728=CARTESIAN_POINT('',(3.48004806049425,23.5733057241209,-0.463438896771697));
#729=CARTESIAN_POINT('',(3.46478706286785,23.5615427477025,-0.426162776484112));
#730=CARTESIAN_POINT('',(3.45415181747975,23.5543946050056,-0.401240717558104));
#731=CARTESIAN_POINT('',(3.43203422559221,23.5414389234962,-0.351267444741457));
#732=CARTESIAN_POINT('',(3.42054783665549,23.5356384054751,-0.326216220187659));
#733=CARTESIAN_POINT('',(3.39680728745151,23.5253574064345,-0.276041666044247));
#734=CARTESIAN_POINT('',(3.38454942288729,23.5208839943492,-0.250918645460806));
#735=CARTESIAN_POINT('',(3.35933910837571,23.5132360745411,-0.200653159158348));
#736=CARTESIAN_POINT('',(3.34638328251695,23.510068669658,-0.175511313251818));
#737=CARTESIAN_POINT('',(3.31984426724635,23.5050110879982,-0.12525393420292));
#738=CARTESIAN_POINT('',(3.30625801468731,23.5031280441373,-0.10013930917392));
#739=CARTESIAN_POINT('',(3.27851952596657,23.5006190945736,-0.0499742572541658));
#740=CARTESIAN_POINT('',(3.26436452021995,23.5000003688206,-0.0249249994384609));
#741=CARTESIAN_POINT('',(3.24999999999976,23.5,0.));
#742=B_SPLINE_CURVE_WITH_KNOTS('',3,(#688,#689,#690,#691,#692,#693,#694,#695,#696,#697,#698,
#699,#700,#701,#702,#703,#704,#705,#706,#707,#708,#709,#710,#711,#712,#713,#714,#715,#716,#717,
#718,#719,#720,#721,#722,#723,#724,#725,#726,#727,#728,#729,#730,#731,#732,#733,#734,#735,#736,
#737,#738,#739,#740,#741),.UNSPECIFIED.,.F.,.F.,(4,2,2,2,2,2,2,2,2,2,2,2,2,2,2,2,2,2,2,2,2,2,2,
2,2,2,4),(0.,0.0405530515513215,0.0811195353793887,0.121709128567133,0.162330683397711,
0.202992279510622,0.243701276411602,0.284464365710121,0.325287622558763,0.366176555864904,
0.407136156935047,0.448170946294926,0.489285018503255,0.530482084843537,0.571765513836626,
0.613138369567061,0.654603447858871,0.696163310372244,0.737820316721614,0.779576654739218,
0.821434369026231,0.905452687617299,0.989899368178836,1.07478810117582,1.16013260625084,
1.24594730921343,1.33224800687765),.UNSPECIFIED.);
#743=CARTESIAN_POINT('',(3.57945533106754,23.9999997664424,-1.11803377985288));
#744=VERTEX_POINT('',#743);
#745=EDGE_CURVE('E413',#744,#685,#742,.T.);
#746=ORIENTED_EDGE('',*,*,#745,.F.);
#747=CARTESIAN_POINT('',(3.57945533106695,23.999999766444,-1.11803377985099));
#748=CARTESIAN_POINT('',(3.57460447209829,24.0173645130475,-1.13356553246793));
#749=CARTESIAN_POINT('',(3.56977218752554,24.0350943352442,-1.14869513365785));
#750=CARTESIAN_POINT('',(3.56024102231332,24.0710266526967,-1.17793813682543));
#751=CARTESIAN_POINT('',(3.5555412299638,24.0892205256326,-1.19206183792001));
#752=CARTESIAN_POINT('',(3.54629960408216,24.1260548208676,-1.21931908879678));
#753=CARTESIAN_POINT('',(3.54175660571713,24.1446881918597,-1.2324617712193));
#754=CARTESIAN_POINT('',(3.53285361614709,24.1823813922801,-1.25777995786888));
#755=CARTESIAN_POINT('',(3.52849231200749,24.2014356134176,-1.26996334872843));
#756=CARTESIAN_POINT('',(3.51997748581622,24.239955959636,-1.29338208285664));
#757=CARTESIAN_POINT('',(3.51582262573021,24.2594177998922,-1.30462398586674));
#758=CARTESIAN_POINT('',(3.50774537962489,24.2987435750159,-1.32617463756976));
#759=CARTESIAN_POINT('',(3.5038217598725,24.3186044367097,-1.3364885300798));
#760=CARTESIAN_POINT('',(3.49623154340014,24.3587224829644,-1.35619339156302));
#761=CARTESIAN_POINT('',(3.4925639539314,24.3789776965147,-1.36558798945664));
#762=CARTESIAN_POINT('',(3.4855102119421,24.4198819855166,-1.38345947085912));
#763=CARTESIAN_POINT('',(3.48212344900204,24.4405300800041,-1.39193835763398));
#764=CARTESIAN_POINT('',(3.47565563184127,24.4822202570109,-1.40797827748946));
#765=CARTESIAN_POINT('',(3.47257449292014,24.5032622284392,-1.41553956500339));
#766=CARTESIAN_POINT('',(3.46674205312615,24.5457421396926,-1.42973850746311));
#767=CARTESIAN_POINT('',(3.46399133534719,24.5671807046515,-1.43637453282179));
#768=CARTESIAN_POINT('',(3.4588437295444,24.6104568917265,-1.44871126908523));
#769=CARTESIAN_POINT('',(3.45644822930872,24.6322957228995,-1.45440832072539));
#770=CARTESIAN_POINT('',(3.45203491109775,24.6763758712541,-1.46484929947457));
#771=CARTESIAN_POINT('',(3.45001941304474,24.6986188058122,-1.46958738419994));
#772=CARTESIAN_POINT('',(3.44638985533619,24.7435101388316,-1.47808626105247));
#773=CARTESIAN_POINT('',(3.44477916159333,24.7661603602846,-1.48183886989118));
#774=CARTESIAN_POINT('',(3.44198276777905,24.8118679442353,-1.48833619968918));
#775=CARTESIAN_POINT('',(3.44080157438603,24.8349271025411,-1.49107023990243));
#776=CARTESIAN_POINT('',(3.43888800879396,24.8814521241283,-1.49549289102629));
#777=CARTESIAN_POINT('',(3.43816136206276,24.9049194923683,-1.49716816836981));
#778=CARTESIAN_POINT('',(3.43717928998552,24.9522572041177,-1.49943017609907));
#779=CARTESIAN_POINT('',(3.43693083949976,24.9761284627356,-1.50000079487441));
#780=CARTESIAN_POINT('',(3.43693177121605,25.0000000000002,-1.5));
#781=B_SPLINE_CURVE_WITH_KNOTS('',3,(#747,#748,#749,#750,#751,#752,#753,#754,#755,#756,#757,
#758,#759,#760,#761,#762,#763,#764,#765,#766,#767,#768,#769,#770,#771,#772,#773,#774,#775,#776,
#777,#778,#779,#780),.UNSPECIFIED.,.F.,.F.,(4,2,2,2,2,2,2,2,2,2,2,2,2,2,2,2,4),(0.,
0.0713851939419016,0.141882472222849,0.2116094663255,0.280685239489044,0.349230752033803,
0.417369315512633,0.485227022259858,0.552933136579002,0.620620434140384,0.688425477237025,
0.756488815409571,0.824955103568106,0.893973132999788,0.963695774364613,1.0342798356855,
1.10588584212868),.UNSPECIFIED.);
#782=EDGE_CURVE('E410',#744,#64,#781,.T.);
#783=ORIENTED_EDGE('',*,*,#782,.T.);
#784=ORIENTED_EDGE('',*,*,#105,.F.);
#785=CARTESIAN_POINT('',(21.5,25.,0.));
#786=DIRECTION('',(-1.,1.35003119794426E-13,0.));
#787=DIRECTION('',(0.,-1.13686837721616E-13,-1.));
#788=AXIS2_PLACEMENT_3D('',#785,#786,#787);
#789=CIRCLE('',#788,1.5);
#790=EDGE_CURVE('E417',#98,#289,#789,.T.);
#791=ORIENTED_EDGE('',*,*,#790,.T.);
#792=EDGE_LOOP('',(#589,#628,#687,#746,#783,#784,#791));
#793=FACE_BOUND('',#792,.T.);
#794=ADVANCED_FACE('F377',(#793),#588,.T.);
#795=CARTESIAN_POINT('',(21.5000000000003,31.,0.));
#796=DIRECTION('',(1.,0.,0.));
#797=DIRECTION('',(0.,-3.17666533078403E-07,-0.99999999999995));
#798=AXIS2_PLACEMENT_3D('',#795,#796,#797);
#799=CYLINDRICAL_SURFACE('',#798,1.5);
#800=CARTESIAN_POINT('',(3.57945533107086,32.0000002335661,1.11803377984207));
#801=CARTESIAN_POINT('',(3.58221153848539,32.009865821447,1.10921026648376));
#802=CARTESIAN_POINT('',(3.58467985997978,32.0196551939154,1.10021319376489));
#803=CARTESIAN_POINT('',(3.58906040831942,32.0390561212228,1.08189097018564));
#804=CARTESIAN_POINT('',(3.59097245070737,32.0486676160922,1.0725657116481));
#805=CARTESIAN_POINT('',(3.59425925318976,32.0676862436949,1.05360663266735));
#806=CARTESIAN_POINT('',(3.59563370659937,32.0770932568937,1.04397263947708));
#807=CARTESIAN_POINT('',(3.5978648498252,32.0956801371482,1.02441530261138));
#808=CARTESIAN_POINT('',(3.5987211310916,32.1048598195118,1.01449173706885));
#809=CARTESIAN_POINT('',(3.59993557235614,32.122971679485,0.994374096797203));
#810=CARTESIAN_POINT('',(3.6002932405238,32.1319036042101,0.98417976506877));
#811=CARTESIAN_POINT('',(3.60053016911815,32.1495021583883,0.963538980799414));
#812=CARTESIAN_POINT('',(3.60040887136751,32.1581684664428,0.953092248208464));
#813=CARTESIAN_POINT('',(3.59970748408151,32.1752203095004,0.931964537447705));
#814=CARTESIAN_POINT('',(3.59912678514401,32.1836054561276,0.921283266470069));
#815=CARTESIAN_POINT('',(3.59752600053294,32.2000816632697,0.899703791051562));
#816=CARTESIAN_POINT('',(3.59650526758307,32.208172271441,0.888805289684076));
#817=CARTESIAN_POINT('',(3.59404350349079,32.2240480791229,0.866808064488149));
#818=CARTESIAN_POINT('',(3.59260179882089,32.2318327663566,0.855709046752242));
#819=CARTESIAN_POINT('',(3.58931677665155,32.24708723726,0.8333268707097));
#820=CARTESIAN_POINT('',(3.58747276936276,32.254556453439,0.82204342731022));
#821=CARTESIAN_POINT('',(3.58340135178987,32.2691721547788,0.799307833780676));
#822=CARTESIAN_POINT('',(3.58117324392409,32.2763180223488,0.787855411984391));
#823=CARTESIAN_POINT('',(3.57635130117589,32.2902807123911,0.764796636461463));
#824=CARTESIAN_POINT('',(3.5737567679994,32.2970968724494,0.753190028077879));
#825=CARTESIAN_POINT('',(3.56821907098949,32.3103951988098,0.729836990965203));
#826=CARTESIAN_POINT('',(3.56527521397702,32.3168766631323,0.718090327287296));
#827=CARTESIAN_POINT('',(3.55905535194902,32.3295018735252,0.694470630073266));
#828=CARTESIAN_POINT('',(3.5557786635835,32.3356448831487,0.682597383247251));
#829=CARTESIAN_POINT('',(3.5489089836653,32.3475905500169,0.658737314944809));
#830=CARTESIAN_POINT('',(3.5453153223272,32.3533924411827,0.646750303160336));
#831=CARTESIAN_POINT('',(3.53782689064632,32.3646541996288,0.622674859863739));
#832=CARTESIAN_POINT('',(3.53393146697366,32.370113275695,0.610586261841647));
#833=CARTESIAN_POINT('',(3.52585404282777,32.3806885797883,0.586319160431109));
#834=CARTESIAN_POINT('',(3.52167140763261,32.385803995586,0.574140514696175));
#835=CARTESIAN_POINT('',(3.51303345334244,32.3956918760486,0.549704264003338));
#836=CARTESIAN_POINT('',(3.50857751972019,32.4004635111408,0.537446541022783));
#837=CARTESIAN_POINT('',(3.49940615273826,32.4096643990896,0.512862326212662));
#838=CARTESIAN_POINT('',(3.49469012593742,32.4140928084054,0.500535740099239));
#839=CARTESIAN_POINT('',(3.48501135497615,32.4226081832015,0.475824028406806));
#840=CARTESIAN_POINT('',(3.48004803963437,32.4266942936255,0.463438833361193));
#841=CARTESIAN_POINT('',(3.46478704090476,32.4384572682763,0.426162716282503));
#842=CARTESIAN_POINT('',(3.45415179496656,32.4456054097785,0.401240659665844));
#843=CARTESIAN_POINT('',(3.43203420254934,32.4585610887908,0.351267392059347));
#844=CARTESIAN_POINT('',(3.42054781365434,32.4643616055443,0.326216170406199));
#845=CARTESIAN_POINT('',(3.39680726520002,32.474642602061,0.276041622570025));
#846=CARTESIAN_POINT('',(3.38454940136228,32.4791160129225,0.250918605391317));
#847=CARTESIAN_POINT('',(3.35933908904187,32.486763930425,0.20065312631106));
#848=CARTESIAN_POINT('',(3.34638326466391,32.4899313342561,0.175511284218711));
#849=CARTESIAN_POINT('',(3.31984425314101,32.4949889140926,0.1252539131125));
#850=CARTESIAN_POINT('',(3.3062580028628,32.49687195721,0.100139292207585));
#851=CARTESIAN_POINT('',(3.27851951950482,32.4993809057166,0.0499742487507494));
#852=CARTESIAN_POINT('',(3.26436451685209,32.4999996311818,0.0249249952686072));
#853=CARTESIAN_POINT('',(3.24999999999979,32.5,0.));
#854=B_SPLINE_CURVE_WITH_KNOTS('',3,(#800,#801,#802,#803,#804,#805,#806,#807,#808,#809,#810,
#811,#812,#813,#814,#815,#816,#817,#818,#819,#820,#821,#822,#823,#824,#825,#826,#827,#828,#829,
#830,#831,#832,#833,#834,#835,#836,#837,#838,#839,#840,#841,#842,#843,#844,#845,#846,#847,#848,
#849,#850,#851,#852,#853),.UNSPECIFIED.,.F.,.F.,(4,2,2,2,2,2,2,2,2,2,2,2,2,2,2,2,2,2,2,2,2,2,2,
2,2,2,4),(0.,0.0405530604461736,0.0811195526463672,0.121709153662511,0.162330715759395,
0.202992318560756,0.243701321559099,0.284464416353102,0.325287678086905,0.366176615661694,
0.407136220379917,0.448171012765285,0.489285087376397,0.530482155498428,0.57176558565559,
0.613138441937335,0.654603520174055,0.696163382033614,0.737820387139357,0.779576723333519,
0.821434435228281,0.905452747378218,0.989899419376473,1.07478814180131,1.16013263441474,
1.24594732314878,1.33224800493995),.UNSPECIFIED.);
#855=CARTESIAN_POINT('',(3.57945533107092,32.0000002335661,1.11803377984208));
#856=VERTEX_POINT('',#855);
#857=CARTESIAN_POINT('',(3.25000012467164,32.5,0.));
#858=VERTEX_POINT('',#857);
#859=EDGE_CURVE('E508',#856,#858,#854,.T.);
#860=ORIENTED_EDGE('',*,*,#859,.F.);
#861=CARTESIAN_POINT('',(3.5794553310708,32.0000002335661,1.11803377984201));
#862=CARTESIAN_POINT('',(3.57460447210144,31.9826354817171,1.13356553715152));
#863=CARTESIAN_POINT('',(3.56977218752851,31.9649056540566,1.14869514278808));
#864=CARTESIAN_POINT('',(3.5602410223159,31.9289733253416,1.17793815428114));
#865=CARTESIAN_POINT('',(3.55554122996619,31.9107794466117,1.1920618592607));
#866=CARTESIAN_POINT('',(3.54629960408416,31.8739451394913,1.21931911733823));
#867=CARTESIAN_POINT('',(3.54175660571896,31.8553117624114,1.23246180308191));
#868=CARTESIAN_POINT('',(3.53285361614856,31.8176185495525,1.25777999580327));
#869=CARTESIAN_POINT('',(3.52849231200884,31.7985643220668,1.26996338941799));
#870=CARTESIAN_POINT('',(3.51997748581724,31.7600439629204,1.29338212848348));
#871=CARTESIAN_POINT('',(3.51582262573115,31.7405821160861,1.30462403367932));
#872=CARTESIAN_POINT('',(3.50774537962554,31.7012563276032,1.32617468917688));
#873=CARTESIAN_POINT('',(3.50382175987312,31.6813954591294,1.33648858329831));
#874=CARTESIAN_POINT('',(3.49623154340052,31.6412773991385,1.35619344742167));
#875=CARTESIAN_POINT('',(3.49256395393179,31.6210221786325,1.36558804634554));
#876=CARTESIAN_POINT('',(3.4855102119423,31.5801178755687,1.38345952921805));
#877=CARTESIAN_POINT('',(3.48212344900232,31.5594697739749,1.39193841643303));
#878=CARTESIAN_POINT('',(3.4756556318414,31.51777958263,1.40797833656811));
#879=CARTESIAN_POINT('',(3.47257449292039,31.4967376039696,1.41553962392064));
#880=CARTESIAN_POINT('',(3.4667420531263,31.4542576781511,1.42973856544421));
#881=CARTESIAN_POINT('',(3.4639913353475,31.4328191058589,1.436374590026));
#882=CARTESIAN_POINT('',(3.45884372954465,31.3895429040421,1.44871132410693));
#883=CARTESIAN_POINT('',(3.45644822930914,31.3677040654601,1.45440837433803));
#884=CARTESIAN_POINT('',(3.45203491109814,31.3236239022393,1.46484934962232));
#885=CARTESIAN_POINT('',(3.45001941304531,31.3013809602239,1.46958743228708));
#886=CARTESIAN_POINT('',(3.44638985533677,31.2564896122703,1.47808630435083));
#887=CARTESIAN_POINT('',(3.44477916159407,31.2338393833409,1.48183891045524));
#888=CARTESIAN_POINT('',(3.44198276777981,31.1881317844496,1.48833623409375));
#889=CARTESIAN_POINT('',(3.44080157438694,31.1650726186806,1.49107027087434));
#890=CARTESIAN_POINT('',(3.43888800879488,31.118547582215,1.49549291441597));
#891=CARTESIAN_POINT('',(3.43816136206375,31.0950802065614,1.4971681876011));
#892=CARTESIAN_POINT('',(3.43717928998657,31.0477424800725,1.49943018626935));
#893=CARTESIAN_POINT('',(3.43693083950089,31.0238712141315,1.50000080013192));
#894=CARTESIAN_POINT('',(3.4369317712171,30.9999996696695,1.49999999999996));
#895=B_SPLINE_CURVE_WITH_KNOTS('',3,(#861,#862,#863,#864,#865,#866,#867,#868,#869,#870,#871,
#872,#873,#874,#875,#876,#877,#878,#879,#880,#881,#882,#883,#884,#885,#886,#887,#888,#889,#890,
#891,#892,#893,#894),.UNSPECIFIED.,.F.,.F.,(4,2,2,2,2,2,2,2,2,2,2,2,2,2,2,2,4),(0.,
0.0713852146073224,0.141882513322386,0.211609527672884,0.280685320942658,0.349230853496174,
0.417369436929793,0.48522716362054,0.55293329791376,0.620620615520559,0.688425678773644,
0.756489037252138,0.824955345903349,0.893973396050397,0.963696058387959,1.03428014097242,
1.1058861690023),.UNSPECIFIED.);
#896=EDGE_CURVE('E504',#856,#273,#895,.T.);
#897=ORIENTED_EDGE('',*,*,#896,.T.);
#898=ORIENTED_EDGE('',*,*,#274,.F.);
#899=CARTESIAN_POINT('',(21.5,31.,0.));
#900=DIRECTION('',(-1.,0.,0.));
#901=DIRECTION('',(0.,1.13686837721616E-13,1.));
#902=AXIS2_PLACEMENT_3D('',#899,#900,#901);
#903=CIRCLE('',#902,1.5);
#904=EDGE_CURVE('E463',#72,#271,#903,.F.);
#905=ORIENTED_EDGE('',*,*,#904,.F.);
#906=ORIENTED_EDGE('',*,*,#73,.F.);
#907=CARTESIAN_POINT('',(3.43693177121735,30.9999995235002,-1.49999999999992));
#908=CARTESIAN_POINT('',(3.43693084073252,31.023900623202,-1.50000080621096));
#909=CARTESIAN_POINT('',(3.43717996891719,31.0478014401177,-1.49942877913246));
#910=CARTESIAN_POINT('',(3.43816456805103,31.0951967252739,-1.49716122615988));
#911=CARTESIAN_POINT('',(3.43889302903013,31.1186921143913,-1.49548189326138));
#912=CARTESIAN_POINT('',(3.44081113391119,31.1652709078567,-1.49104871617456));
#913=CARTESIAN_POINT('',(3.44199501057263,31.1883558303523,-1.48830830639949));
#914=CARTESIAN_POINT('',(3.44479742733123,31.2341119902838,-1.4817962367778));
#915=CARTESIAN_POINT('',(3.44641141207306,31.2567850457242,-1.47803537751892));
#916=CARTESIAN_POINT('',(3.45004795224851,31.3017184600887,-1.46951850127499));
#917=CARTESIAN_POINT('',(3.45206708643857,31.32398067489,-1.46477080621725));
#918=CARTESIAN_POINT('',(3.45648782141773,31.3680952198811,-1.45430969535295));
#919=CARTESIAN_POINT('',(3.45888704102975,31.389949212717,-1.44860227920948));
#920=CARTESIAN_POINT('',(3.46404197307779,31.4332510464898,-1.43624456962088));
#921=CARTESIAN_POINT('',(3.46679623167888,31.4547001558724,-1.42959811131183));
#922=CARTESIAN_POINT('',(3.47263538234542,31.4971960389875,-1.41537880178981));
#923=CARTESIAN_POINT('',(3.47571962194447,31.518243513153,-1.4078077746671));
#924=CARTESIAN_POINT('',(3.48219300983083,31.5599392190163,-1.39174968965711));
#925=CARTESIAN_POINT('',(3.48558217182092,31.5805874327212,-1.38326259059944));
#926=CARTESIAN_POINT('',(3.49263981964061,31.6214862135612,-1.36537688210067));
#927=CARTESIAN_POINT('',(3.49630884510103,31.6417359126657,-1.35597650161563));
#928=CARTESIAN_POINT('',(3.503900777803,31.6818370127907,-1.33626321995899));
#929=CARTESIAN_POINT('',(3.50782460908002,31.7016865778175,-1.32594694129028));
#930=CARTESIAN_POINT('',(3.51590085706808,31.7409837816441,-1.30439566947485));
#931=CARTESIAN_POINT('',(3.52005444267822,31.7604285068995,-1.29315580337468));
#932=CARTESIAN_POINT('',(3.52856503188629,31.798908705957,-1.26974635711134));
#933=CARTESIAN_POINT('',(3.53292331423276,31.8179400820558,-1.2575705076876));
#934=CARTESIAN_POINT('',(3.54181830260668,31.8555818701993,-1.23227372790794));
#935=CARTESIAN_POINT('',(3.54635626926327,31.8741868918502,-1.21914522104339));
#936=CARTESIAN_POINT('',(3.55558560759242,31.9109591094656,-1.19192379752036));
#937=CARTESIAN_POINT('',(3.56027810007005,31.9291195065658,-1.17782207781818));
#938=CARTESIAN_POINT('',(3.56979215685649,31.9649799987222,-1.14863169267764));
#939=CARTESIAN_POINT('',(3.57461459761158,31.982671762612,-1.13353307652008));
#940=CARTESIAN_POINT('',(3.5794552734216,32.0000000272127,-1.11803396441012));
#941=B_SPLINE_CURVE_WITH_KNOTS('',3,(#907,#908,#909,#910,#911,#912,#913,#914,#915,#916,#917,
#918,#919,#920,#921,#922,#923,#924,#925,#926,#927,#928,#929,#930,#931,#932,#933,#934,#935,#936,
#937,#938,#939,#940),.UNSPECIFIED.,.F.,.F.,(4,2,2,2,2,2,2,2,2,2,2,2,2,2,2,2,4),(0.,
0.0716946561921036,0.142363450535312,0.212165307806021,0.281255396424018,0.349784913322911,
0.417900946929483,0.485746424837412,0.553460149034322,0.621176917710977,0.689027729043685,
0.757140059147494,0.825638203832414,0.894643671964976,0.964275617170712,1.03465129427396,
1.10588652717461),.UNSPECIFIED.);
#942=CARTESIAN_POINT('',(3.57945527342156,32.,-1.1180339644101));
#943=VERTEX_POINT('',#942);
#944=EDGE_CURVE('E455',#62,#943,#941,.T.);
#945=ORIENTED_EDGE('',*,*,#944,.T.);
#946=CARTESIAN_POINT('',(3.24999999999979,32.5,0.));
#947=CARTESIAN_POINT('',(3.26436398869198,32.4999996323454,-0.024924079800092));
#948=CARTESIAN_POINT('',(3.27851851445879,32.4993809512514,-0.0499723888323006));
#949=CARTESIAN_POINT('',(3.30625631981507,32.4968721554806,-0.100135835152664));
#950=CARTESIAN_POINT('',(3.31984236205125,32.4949892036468,-0.125249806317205));
#951=CARTESIAN_POINT('',(3.3463811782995,32.4899318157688,-0.175506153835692));
#952=CARTESIAN_POINT('',(3.35933700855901,32.4867644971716,-0.200647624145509));
#953=CARTESIAN_POINT('',(3.38454749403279,32.4791167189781,-0.250912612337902));
#954=CARTESIAN_POINT('',(3.39680551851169,32.474643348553,-0.276035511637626));
#955=CARTESIAN_POINT('',(3.4205464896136,32.4643623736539,-0.326210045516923));
#956=CARTESIAN_POINT('',(3.4320331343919,32.4585618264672,-0.351261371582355));
#957=CARTESIAN_POINT('',(3.45415128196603,32.4456060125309,-0.401235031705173));
#958=CARTESIAN_POINT('',(3.46478682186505,32.438457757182,-0.42615737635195));
#959=CARTESIAN_POINT('',(3.48004823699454,32.4266945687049,-0.463433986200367));
#960=CARTESIAN_POINT('',(3.48501169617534,32.4226083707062,-0.475819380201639));
#961=CARTESIAN_POINT('',(3.49469074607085,32.4140928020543,-0.500531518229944));
#962=CARTESIAN_POINT('',(3.49940690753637,32.4096642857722,-0.512858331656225));
#963=CARTESIAN_POINT('',(3.50857852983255,32.4004631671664,-0.537443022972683));
#964=CARTESIAN_POINT('',(3.51303458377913,32.3956914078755,-0.549700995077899));
#965=CARTESIAN_POINT('',(3.52167276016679,32.3858032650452,-0.574137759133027));
#966=CARTESIAN_POINT('',(3.52585549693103,32.3806877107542,-0.586316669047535));
#967=CARTESIAN_POINT('',(3.53393310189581,32.3701121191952,-0.610584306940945));
#968=CARTESIAN_POINT('',(3.53782860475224,32.3646528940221,-0.622673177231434));
#969=CARTESIAN_POINT('',(3.54531716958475,32.3533908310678,-0.646749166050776));
#970=CARTESIAN_POINT('',(3.54891088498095,32.34758878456,-0.658736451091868));
#971=CARTESIAN_POINT('',(3.55578064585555,32.3356428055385,-0.682597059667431));
#972=CARTESIAN_POINT('',(3.55905736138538,32.3294996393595,-0.694470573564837));
#973=CARTESIAN_POINT('',(3.56527724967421,32.3168741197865,-0.718090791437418));
#974=CARTESIAN_POINT('',(3.56822110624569,32.3103925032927,-0.72983770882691));
#975=CARTESIAN_POINT('',(3.57375877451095,32.2970938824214,-0.753191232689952));
#976=CARTESIAN_POINT('',(3.57635328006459,32.290277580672,-0.764798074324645));
#977=CARTESIAN_POINT('',(3.58117514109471,32.2763146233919,-0.787857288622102));
#978=CARTESIAN_POINT('',(3.58340319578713,32.2691686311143,-0.799309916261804));
#979=CARTESIAN_POINT('',(3.5874744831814,32.2545527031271,-0.822045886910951));
#980=CARTESIAN_POINT('',(3.58931841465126,32.2470833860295,-0.833329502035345));
#981=CARTESIAN_POINT('',(3.59260326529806,32.2318287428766,-0.855711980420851));
#982=CARTESIAN_POINT('',(3.59404487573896,32.2240439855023,-0.866811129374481));
#983=CARTESIAN_POINT('',(3.59650643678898,32.2081680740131,-0.888808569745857));
#984=CARTESIAN_POINT('',(3.59752706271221,32.2000774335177,-0.899707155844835));
#985=CARTESIAN_POINT('',(3.5991276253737,32.1836012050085,-0.921286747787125));
#986=CARTESIAN_POINT('',(3.59970821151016,32.1752160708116,-0.93196805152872));
#987=CARTESIAN_POINT('',(3.60040937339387,32.1581643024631,-0.953095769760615));
#988=CARTESIAN_POINT('',(3.60053056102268,32.1494980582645,-0.963542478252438));
#989=CARTESIAN_POINT('',(3.60029342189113,32.1318996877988,-0.984183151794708));
#990=CARTESIAN_POINT('',(3.59993565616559,32.1229678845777,-0.994377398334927));
#991=CARTESIAN_POINT('',(3.59872104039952,32.1048563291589,-1.01449480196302));
#992=CARTESIAN_POINT('',(3.59786468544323,32.0956768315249,-1.02441821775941));
#993=CARTESIAN_POINT('',(3.59563342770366,32.0770903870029,-1.04397518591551));
#994=CARTESIAN_POINT('',(3.5942589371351,32.0676836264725,-1.05360896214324));
#995=CARTESIAN_POINT('',(3.59097210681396,32.0486655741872,-1.07256753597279));
#996=CARTESIAN_POINT('',(3.58906007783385,32.0390544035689,-1.08189250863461));
#997=CARTESIAN_POINT('',(3.58467961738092,32.0196541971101,-1.10021408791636));
#998=CARTESIAN_POINT('',(3.58221137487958,32.0098652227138,-1.10921080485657));
#999=CARTESIAN_POINT('',(3.57945527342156,32.0000000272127,-1.1180339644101));
#1000=B_SPLINE_CURVE_WITH_KNOTS('',3,(#946,#947,#948,#949,#950,#951,#952,#953,#954,#955,#956,
#957,#958,#959,#960,#961,#962,#963,#964,#965,#966,#967,#968,#969,#970,#971,#972,#973,#974,#975,
#976,#977,#978,#979,#980,#981,#982,#983,#984,#985,#986,#987,#988,#989,#990,#991,#992,#993,#994,
#995,#996,#997,#998,#999),.UNSPECIFIED.,.F.,.F.,(4,2,2,2,2,2,2,2,2,2,2,2,2,2,2,2,2,2,2,2,2,2,2,
2,2,2,4),(0.,0.0862975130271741,0.172110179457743,0.257453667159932,0.342342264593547,
0.426789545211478,0.510809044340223,0.55266751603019,0.594424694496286,0.636082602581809,
0.677643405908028,0.71910944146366,0.760483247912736,0.801767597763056,0.842965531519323,
0.884080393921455,0.925115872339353,0.966076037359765,1.00696538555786,1.04778888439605,
1.0885520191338,1.12926084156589,1.16992202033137,1.21054289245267,1.2511315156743,
1.29169672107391,1.33224816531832),.UNSPECIFIED.);
#1001=EDGE_CURVE('E462',#858,#943,#1000,.T.);
#1002=ORIENTED_EDGE('',*,*,#1001,.F.);
#1003=EDGE_LOOP('',(#860,#897,#898,#905,#906,#945,#1002));
#1004=FACE_BOUND('',#1003,.T.);
#1005=ADVANCED_FACE('F386',(#1004),#799,.T.);
#1006=CARTESIAN_POINT('',(21.5000000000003,29.,0.));
#1007=DIRECTION('',(0.,0.,1.));
#1008=DIRECTION('',(1.,0.,0.));
#1009=AXIS2_PLACEMENT_3D('',#1006,#1007,#1008);
#1010=TOROIDAL_SURFACE('',#1009,1.99999999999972,1.5);
#1011=ORIENTED_EDGE('',*,*,#904,.T.);
#1012=ORIENTED_EDGE('',*,*,#314,.F.);
#1013=CARTESIAN_POINT('',(23.5,29.,0.));
#1014=DIRECTION('',(0.,1.,0.));
#1015=DIRECTION('',(0.,0.,1.));
#1016=AXIS2_PLACEMENT_3D('',#1013,#1014,#1015);
#1017=CIRCLE('',#1016,1.5);
#1018=EDGE_CURVE('E548',#81,#306,#1017,.F.);
#1019=ORIENTED_EDGE('',*,*,#1018,.F.);
#1020=ORIENTED_EDGE('',*,*,#82,.F.);
#1021=EDGE_LOOP('',(#1011,#1012,#1019,#1020));
#1022=FACE_BOUND('',#1021,.T.);
#1023=ADVANCED_FACE('F892',(#1022),#1010,.T.);
#1024=CARTESIAN_POINT('',(23.5,27.,0.));
#1025=DIRECTION('',(0.,-1.,0.));
#1026=DIRECTION('',(0.,0.,-1.));
#1027=AXIS2_PLACEMENT_3D('',#1024,#1025,#1026);
#1028=CYLINDRICAL_SURFACE('',#1027,1.5);
#1029=ORIENTED_EDGE('',*,*,#1018,.T.);
#1030=ORIENTED_EDGE('',*,*,#307,.F.);
#1031=CARTESIAN_POINT('',(23.5,27.,0.));
#1032=DIRECTION('',(0.,1.,0.));
#1033=DIRECTION('',(0.,0.,1.));
#1034=AXIS2_PLACEMENT_3D('',#1031,#1032,#1033);
#1035=CIRCLE('',#1034,1.5);
#1036=EDGE_CURVE('E555',#89,#298,#1035,.F.);
#1037=ORIENTED_EDGE('',*,*,#1036,.F.);
#1038=ORIENTED_EDGE('',*,*,#90,.F.);
#1039=EDGE_LOOP('',(#1029,#1030,#1037,#1038));
#1040=FACE_BOUND('',#1039,.T.);
#1041=ADVANCED_FACE('F900',(#1040),#1028,.T.);
#1042=CARTESIAN_POINT('',(21.5000000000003,27.,0.));
#1043=DIRECTION('',(0.,0.,1.));
#1044=DIRECTION('',(-2.08660696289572E-13,-1.,0.));
#1045=AXIS2_PLACEMENT_3D('',#1042,#1043,#1044);
#1046=TOROIDAL_SURFACE('',#1045,1.99999999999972,1.5);
#1047=ORIENTED_EDGE('',*,*,#1036,.T.);
#1048=ORIENTED_EDGE('',*,*,#299,.F.);
#1049=ORIENTED_EDGE('',*,*,#790,.F.);
#1050=ORIENTED_EDGE('',*,*,#99,.F.);
#1051=EDGE_LOOP('',(#1047,#1048,#1049,#1050));
#1052=FACE_BOUND('',#1051,.T.);
#1053=ADVANCED_FACE('F909',(#1052),#1046,.T.);
#1054=CARTESIAN_POINT('',(-3.24997217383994,32.5,3.2746253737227));
#1055=DIRECTION('',(0.,1.,0.));
#1056=DIRECTION('',(1.,0.,0.));
#1057=AXIS2_PLACEMENT_3D('',#1054,#1055,#1056);
#1058=PLANE('',#1057);
#1059=CARTESIAN_POINT('',(0.,32.5,0.));
#1060=DIRECTION('',(0.,1.,0.));
#1061=DIRECTION('',(-0.707106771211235,0.,0.70710679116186));
#1062=AXIS2_PLACEMENT_3D('',#1059,#1060,#1061);
#1063=CIRCLE('',#1062,3.25000012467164);
#1064=EDGE_CURVE('E557',#858,#858,#1063,.F.);
#1065=ORIENTED_EDGE('',*,*,#1064,.F.);
#1066=EDGE_LOOP('',(#1065));
#1067=FACE_BOUND('',#1066,.T.);
#1068=ADVANCED_FACE('F482',(#1067),#1058,.T.);
#1069=CARTESIAN_POINT('',(0.,23.5,0.));
#1070=DIRECTION('',(0.,-1.,0.));
#1071=DIRECTION('',(-1.,0.,0.));
#1072=AXIS2_PLACEMENT_3D('',#1069,#1070,#1071);
#1073=CYLINDRICAL_SURFACE('',#1072,3.75);
#1074=ORIENTED_EDGE('',*,*,#944,.F.);
#1075=ORIENTED_EDGE('',*,*,#65,.T.);
#1076=ORIENTED_EDGE('',*,*,#782,.F.);
#1077=CARTESIAN_POINT('',(0.,23.9999997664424,0.));
#1078=DIRECTION('',(0.,1.,0.));
#1079=DIRECTION('',(0.954521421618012,0.,-0.298142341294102));
#1080=AXIS2_PLACEMENT_3D('',#1077,#1078,#1079);
#1081=CIRCLE('',#1080,3.75);
#1082=EDGE_CURVE('E558',#626,#744,#1081,.F.);
#1083=ORIENTED_EDGE('',*,*,#1082,.F.);
#1084=ORIENTED_EDGE('',*,*,#627,.F.);
#1085=ORIENTED_EDGE('',*,*,#282,.F.);
#1086=ORIENTED_EDGE('',*,*,#896,.F.);
#1087=CARTESIAN_POINT('',(0.,32.0000002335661,0.));
#1088=DIRECTION('',(0.,-1.,0.));
#1089=DIRECTION('',(0.954521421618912,0.,0.29814234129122));
#1090=AXIS2_PLACEMENT_3D('',#1087,#1088,#1089);
#1091=CIRCLE('',#1090,3.75);
#1092=EDGE_CURVE('E458',#856,#943,#1091,.T.);
#1093=ORIENTED_EDGE('',*,*,#1092,.T.);
#1094=EDGE_LOOP('',(#1074,#1075,#1076,#1083,#1084,#1085,#1086,#1093));
#1095=FACE_BOUND('',#1094,.T.);
#1096=ADVANCED_FACE('F452',(#1095),#1073,.T.);
#1097=CARTESIAN_POINT('',(-3.27462537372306,23.5,-3.25000458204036));
#1098=DIRECTION('',(0.,-1.,0.));
#1099=DIRECTION('',(1.,0.,0.));
#1100=AXIS2_PLACEMENT_3D('',#1097,#1098,#1099);
#1101=PLANE('',#1100);
#1102=CARTESIAN_POINT('',(0.,23.5,0.));
#1103=DIRECTION('',(0.,-1.,0.));
#1104=DIRECTION('',(1.42006240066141E-07,0.,-1.));
#1105=AXIS2_PLACEMENT_3D('',#1102,#1103,#1104);
#1106=CIRCLE('',#1105,3.25);
#1107=CARTESIAN_POINT('',(-2.29814125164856,23.5,2.29814118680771));
#1108=VERTEX_POINT('',#1107);
#1109=EDGE_CURVE('E1206',#1108,#685,#1106,.T.);
#1110=ORIENTED_EDGE('',*,*,#1109,.T.);
#1111=CARTESIAN_POINT('',(0.,23.5,0.));
#1112=DIRECTION('',(0.,-1.,0.));
#1113=DIRECTION('',(1.,0.,0.));
#1114=AXIS2_PLACEMENT_3D('',#1111,#1112,#1113);
#1115=CIRCLE('',#1114,3.24999999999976);
#1116=EDGE_CURVE('E1202',#685,#1108,#1115,.T.);
#1117=ORIENTED_EDGE('',*,*,#1116,.T.);
#1118=EDGE_LOOP('',(#1110,#1117));
#1119=FACE_BOUND('',#1118,.T.);
#1120=CARTESIAN_POINT('',(0.,23.5,0.));
#1121=DIRECTION('',(0.,-1.,0.));
#1122=DIRECTION('',(0.,0.,-1.));
#1123=AXIS2_PLACEMENT_3D('',#1120,#1121,#1122);
#1124=CIRCLE('',#1123,2.);
#1125=CARTESIAN_POINT('',(0.,23.5,-2.));
#1126=VERTEX_POINT('',#1125);
#1127=EDGE_CURVE('E9',#1126,#1126,#1124,.F.);
#1128=ORIENTED_EDGE('',*,*,#1127,.T.);
#1129=EDGE_LOOP('',(#1128));
#1130=FACE_BOUND('',#1129,.T.);
#1131=ADVANCED_FACE('F481',(#1119,#1130),#1101,.T.);
#1132=CARTESIAN_POINT('',(12.,28.,4.3));
#1133=DIRECTION('',(0.,-1.,0.));
#1134=DIRECTION('',(-0.676064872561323,0.,-0.736842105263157));
#1135=AXIS2_PLACEMENT_3D('',#1132,#1133,#1134);
#1136=SPHERICAL_SURFACE('',#1135,3.8);
#1137=ORIENTED_EDGE('',*,*,#573,.T.);
#1138=CARTESIAN_POINT('',(12.,25.430953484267,1.49999999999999));
#1139=CARTESIAN_POINT('',(12.,25.4742599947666,1.46026412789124));
#1140=CARTESIAN_POINT('',(12.,25.5184897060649,1.42153457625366));
#1141=CARTESIAN_POINT('',(12.,25.6086973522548,1.34616793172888));
#1142=CARTESIAN_POINT('',(12.,25.6546752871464,1.30953083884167));
#1143=CARTESIAN_POINT('',(12.,25.7482812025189,1.23842892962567));
#1144=CARTESIAN_POINT('',(12.,25.7959091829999,1.20396411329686));
#1145=CARTESIAN_POINT('',(12.,25.8927124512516,1.13728069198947));
#1146=CARTESIAN_POINT('',(12.,25.9418877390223,1.10506208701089));
#1147=CARTESIAN_POINT('',(12.,26.0416798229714,1.04294051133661));
#1148=CARTESIAN_POINT('',(12.,26.0922966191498,1.01303754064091));
#1149=CARTESIAN_POINT('',(12.,26.1948627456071,0.955611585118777));
#1150=CARTESIAN_POINT('',(12.,26.2468120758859,0.928088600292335));
#1151=CARTESIAN_POINT('',(12.,26.3519314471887,0.875481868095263));
#1152=CARTESIAN_POINT('',(12.,26.4051014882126,0.850398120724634));
#1153=CARTESIAN_POINT('',(12.,26.5125478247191,0.802723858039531));
#1154=CARTESIAN_POINT('',(12.,26.5668241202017,0.780133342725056));
#1155=CARTESIAN_POINT('',(12.,26.6763661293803,0.73749417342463));
#1156=CARTESIAN_POINT('',(12.,26.7316318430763,0.717445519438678));
#1157=CARTESIAN_POINT('',(12.,26.8430337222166,0.679933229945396));
#1158=CARTESIAN_POINT('',(12.,26.8991698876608,0.662469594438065));
#1159=CARTESIAN_POINT('',(12.,27.0121918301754,0.630164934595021));
#1160=CARTESIAN_POINT('',(12.,27.0690776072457,0.615323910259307));
#1161=CARTESIAN_POINT('',(12.,27.1834763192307,0.588296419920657));
#1162=CARTESIAN_POINT('',(12.,27.2409892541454,0.57610995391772));
#1163=CARTESIAN_POINT('',(12.,27.3565184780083,0.554417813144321));
#1164=CARTESIAN_POINT('',(12.,27.4145347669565,0.544912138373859));
#1165=CARTESIAN_POINT('',(12.,27.5309458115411,0.528602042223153));
#1166=CARTESIAN_POINT('',(12.,27.5893405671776,0.521797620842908));
#1167=CARTESIAN_POINT('',(12.,27.7063828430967,0.510904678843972));
#1168=CARTESIAN_POINT('',(12.,27.7650303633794,0.506816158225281));
#1169=CARTESIAN_POINT('',(12.,27.8824519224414,0.501363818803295));
#1170=CARTESIAN_POINT('',(12.,27.9412259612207,0.500000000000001));
#1171=CARTESIAN_POINT('',(12.,28.0587740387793,0.500000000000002));
#1172=CARTESIAN_POINT('',(12.,28.1175480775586,0.501363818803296));
#1173=CARTESIAN_POINT('',(12.,28.2349696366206,0.506816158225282));
#1174=CARTESIAN_POINT('',(12.,28.2936171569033,0.510904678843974));
#1175=CARTESIAN_POINT('',(12.,28.4106594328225,0.52179762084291));
#1176=CARTESIAN_POINT('',(12.,28.4690541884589,0.528602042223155));
#1177=CARTESIAN_POINT('',(12.,28.5854652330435,0.544912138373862));
#1178=CARTESIAN_POINT('',(12.,28.6434815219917,0.554417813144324));
#1179=CARTESIAN_POINT('',(12.,28.7590107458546,0.576109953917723));
#1180=CARTESIAN_POINT('',(12.,28.8165236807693,0.588296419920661));
#1181=CARTESIAN_POINT('',(12.,28.9309223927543,0.615323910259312));
#1182=CARTESIAN_POINT('',(12.,28.9878081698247,0.630164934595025));
#1183=CARTESIAN_POINT('',(12.,29.1008301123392,0.66246959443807));
#1184=CARTESIAN_POINT('',(12.,29.1569662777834,0.679933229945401));
#1185=CARTESIAN_POINT('',(12.,29.2683681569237,0.717445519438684));
#1186=CARTESIAN_POINT('',(12.,29.3236338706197,0.737494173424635));
#1187=CARTESIAN_POINT('',(12.,29.4331758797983,0.780133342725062));
#1188=CARTESIAN_POINT('',(12.,29.4874521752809,0.802723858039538));
#1189=CARTESIAN_POINT('',(12.,29.5948985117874,0.850398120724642));
#1190=CARTESIAN_POINT('',(12.,29.6480685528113,0.875481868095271));
#1191=CARTESIAN_POINT('',(12.,29.7531879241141,0.928088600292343));
#1192=CARTESIAN_POINT('',(12.,29.8051372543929,0.955611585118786));
#1193=CARTESIAN_POINT('',(12.,29.9077033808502,1.01303754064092));
#1194=CARTESIAN_POINT('',(12.,29.9583201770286,1.04294051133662));
#1195=CARTESIAN_POINT('',(12.,30.0581122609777,1.1050620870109));
#1196=CARTESIAN_POINT('',(12.,30.1072875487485,1.13728069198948));
#1197=CARTESIAN_POINT('',(12.,30.2040908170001,1.20396411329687));
#1198=CARTESIAN_POINT('',(12.,30.2517187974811,1.23842892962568));
#1199=CARTESIAN_POINT('',(12.,30.3453247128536,1.30953083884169));
#1200=CARTESIAN_POINT('',(12.,30.3913026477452,1.34616793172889));
#1201=CARTESIAN_POINT('',(12.,30.4815102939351,1.42153457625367));
#1202=CARTESIAN_POINT('',(12.,30.5257400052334,1.46026412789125));
#1203=CARTESIAN_POINT('',(12.,30.569046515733,1.5));
#1204=B_SPLINE_CURVE_WITH_KNOTS('',3,(#1138,#1139,#1140,#1141,#1142,#1143,#1144,#1145,#1146,
#1147,#1148,#1149,#1150,#1151,#1152,#1153,#1154,#1155,#1156,#1157,#1158,#1159,#1160,#1161,#1162,
#1163,#1164,#1165,#1166,#1167,#1168,#1169,#1170,#1171,#1172,#1173,#1174,#1175,#1176,#1177,#1178,
#1179,#1180,#1181,#1182,#1183,#1184,#1185,#1186,#1187,#1188,#1189,#1190,#1191,#1192,#1193,#1194,
#1195,#1196,#1197,#1198,#1199,#1200,#1201,#1202,#1203),.UNSPECIFIED.,.F.,.F.,(4,2,2,2,2,2,2,2,2,
2,2,2,2,2,2,2,2,2,2,2,2,2,2,2,2,2,2,2,2,2,2,2,4),(0.,0.176306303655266,0.35261260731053,
0.528918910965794,0.705225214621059,0.881531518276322,1.05783782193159,1.23414412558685,
1.41045042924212,1.58675673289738,1.76306303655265,1.93936934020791,2.11567564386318,
2.29198194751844,2.4682882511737,2.64459455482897,2.82090085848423,2.9972071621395,
3.17351346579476,3.34981976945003,3.52612607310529,3.70243237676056,3.87873868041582,
4.05504498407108,4.23135128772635,4.40765759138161,4.58396389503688,4.76027019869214,
4.93657650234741,5.11288280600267,5.28918910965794,5.4654954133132,5.64180171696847),.UNSPECIFIED.);
#1205=EDGE_CURVE('E1201',#572,#570,#1204,.T.);
#1206=ORIENTED_EDGE('',*,*,#1205,.T.);
#1207=EDGE_LOOP('',(#1137,#1206));
#1208=FACE_BOUND('',#1207,.T.);
#1209=ADVANCED_FACE('F940',(#1208),#1136,.F.);
#1210=CARTESIAN_POINT('',(12.,25.430953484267,1.5));
#1211=DIRECTION('',(-1.,0.,0.));
#1212=DIRECTION('',(0.,1.,0.));
#1213=AXIS2_PLACEMENT_3D('',#1210,#1211,#1212);
#1214=PLANE('',#1213);
#1215=ORIENTED_EDGE('',*,*,#579,.T.);
#1216=ORIENTED_EDGE('',*,*,#1205,.F.);
#1217=EDGE_LOOP('',(#1215,#1216));
#1218=FACE_BOUND('',#1217,.T.);
#1219=ADVANCED_FACE('F950',(#1218),#1214,.T.);
#1220=CARTESIAN_POINT('',(12.,28.,-4.3));
#1221=DIRECTION('',(0.,1.,0.));
#1222=DIRECTION('',(-0.676064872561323,0.,0.736842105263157));
#1223=AXIS2_PLACEMENT_3D('',#1220,#1221,#1222);
#1224=SPHERICAL_SURFACE('',#1223,3.8);
#1225=CARTESIAN_POINT('',(12.,30.569046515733,-1.50000000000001));
#1226=CARTESIAN_POINT('',(12.,30.5257400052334,-1.46026412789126));
#1227=CARTESIAN_POINT('',(12.,30.4815102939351,-1.42153457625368));
#1228=CARTESIAN_POINT('',(12.,30.3913026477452,-1.3461679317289));
#1229=CARTESIAN_POINT('',(12.,30.3453247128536,-1.30953083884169));
#1230=CARTESIAN_POINT('',(12.,30.2517187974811,-1.23842892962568));
#1231=CARTESIAN_POINT('',(12.,30.2040908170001,-1.20396411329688));
#1232=CARTESIAN_POINT('',(12.,30.1072875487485,-1.13728069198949));
#1233=CARTESIAN_POINT('',(12.,30.0581122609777,-1.1050620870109));
#1234=CARTESIAN_POINT('',(12.,29.9583201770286,-1.04294051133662));
#1235=CARTESIAN_POINT('',(12.,29.9077033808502,-1.01303754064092));
#1236=CARTESIAN_POINT('',(12.,29.8051372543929,-0.955611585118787));
#1237=CARTESIAN_POINT('',(12.,29.7531879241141,-0.928088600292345));
#1238=CARTESIAN_POINT('',(12.,29.6480685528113,-0.875481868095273));
#1239=CARTESIAN_POINT('',(12.,29.5948985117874,-0.850398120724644));
#1240=CARTESIAN_POINT('',(12.,29.4874521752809,-0.802723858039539));
#1241=CARTESIAN_POINT('',(12.,29.4331758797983,-0.780133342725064));
#1242=CARTESIAN_POINT('',(12.,29.3236338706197,-0.737494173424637));
#1243=CARTESIAN_POINT('',(12.,29.2683681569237,-0.717445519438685));
#1244=CARTESIAN_POINT('',(12.,29.1569662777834,-0.679933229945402));
#1245=CARTESIAN_POINT('',(12.,29.1008301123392,-0.662469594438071));
#1246=CARTESIAN_POINT('',(12.,28.9878081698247,-0.630164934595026));
#1247=CARTESIAN_POINT('',(12.,28.9309223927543,-0.615323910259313));
#1248=CARTESIAN_POINT('',(12.,28.8165236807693,-0.588296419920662));
#1249=CARTESIAN_POINT('',(12.,28.7590107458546,-0.576109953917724));
#1250=CARTESIAN_POINT('',(12.,28.6434815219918,-0.554417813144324));
#1251=CARTESIAN_POINT('',(12.,28.5854652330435,-0.544912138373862));
#1252=CARTESIAN_POINT('',(12.,28.4690541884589,-0.528602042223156));
#1253=CARTESIAN_POINT('',(12.,28.4106594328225,-0.52179762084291));
#1254=CARTESIAN_POINT('',(12.,28.2936171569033,-0.510904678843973));
#1255=CARTESIAN_POINT('',(12.,28.2349696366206,-0.506816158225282));
#1256=CARTESIAN_POINT('',(12.,28.1175480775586,-0.501363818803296));
#1257=CARTESIAN_POINT('',(12.,28.0587740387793,-0.500000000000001));
#1258=CARTESIAN_POINT('',(12.,27.9412259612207,-0.500000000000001));
#1259=CARTESIAN_POINT('',(12.,27.8824519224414,-0.501363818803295));
#1260=CARTESIAN_POINT('',(12.,27.7650303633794,-0.506816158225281));
#1261=CARTESIAN_POINT('',(12.,27.7063828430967,-0.510904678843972));
#1262=CARTESIAN_POINT('',(12.,27.5893405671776,-0.521797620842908));
#1263=CARTESIAN_POINT('',(12.,27.5309458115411,-0.528602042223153));
#1264=CARTESIAN_POINT('',(12.,27.4145347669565,-0.544912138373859));
#1265=CARTESIAN_POINT('',(12.,27.3565184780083,-0.554417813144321));
#1266=CARTESIAN_POINT('',(12.,27.2409892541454,-0.57610995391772));
#1267=CARTESIAN_POINT('',(12.,27.1834763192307,-0.588296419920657));
#1268=CARTESIAN_POINT('',(12.,27.0690776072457,-0.615323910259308));
#1269=CARTESIAN_POINT('',(12.,27.0121918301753,-0.630164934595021));
#1270=CARTESIAN_POINT('',(12.,26.8991698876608,-0.662469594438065));
#1271=CARTESIAN_POINT('',(12.,26.8430337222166,-0.679933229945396));
#1272=CARTESIAN_POINT('',(12.,26.7316318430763,-0.717445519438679));
#1273=CARTESIAN_POINT('',(12.,26.6763661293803,-0.73749417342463));
#1274=CARTESIAN_POINT('',(12.,26.5668241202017,-0.780133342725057));
#1275=CARTESIAN_POINT('',(12.,26.5125478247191,-0.802723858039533));
#1276=CARTESIAN_POINT('',(12.,26.4051014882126,-0.850398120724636));
#1277=CARTESIAN_POINT('',(12.,26.3519314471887,-0.875481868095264));
#1278=CARTESIAN_POINT('',(12.,26.2468120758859,-0.928088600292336));
#1279=CARTESIAN_POINT('',(12.,26.1948627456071,-0.955611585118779));
#1280=CARTESIAN_POINT('',(12.,26.0922966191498,-1.01303754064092));
#1281=CARTESIAN_POINT('',(12.,26.0416798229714,-1.04294051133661));
#1282=CARTESIAN_POINT('',(12.,25.9418877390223,-1.10506208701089));
#1283=CARTESIAN_POINT('',(12.,25.8927124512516,-1.13728069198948));
#1284=CARTESIAN_POINT('',(12.,25.7959091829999,-1.20396411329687));
#1285=CARTESIAN_POINT('',(12.,25.7482812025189,-1.23842892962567));
#1286=CARTESIAN_POINT('',(12.,25.6546752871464,-1.30953083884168));
#1287=CARTESIAN_POINT('',(12.,25.6086973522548,-1.34616793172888));
#1288=CARTESIAN_POINT('',(12.,25.5184897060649,-1.42153457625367));
#1289=CARTESIAN_POINT('',(12.,25.4742599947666,-1.46026412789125));
#1290=CARTESIAN_POINT('',(12.,25.430953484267,-1.5));
#1291=B_SPLINE_CURVE_WITH_KNOTS('',3,(#1225,#1226,#1227,#1228,#1229,#1230,#1231,#1232,#1233,
#1234,#1235,#1236,#1237,#1238,#1239,#1240,#1241,#1242,#1243,#1244,#1245,#1246,#1247,#1248,#1249,
#1250,#1251,#1252,#1253,#1254,#1255,#1256,#1257,#1258,#1259,#1260,#1261,#1262,#1263,#1264,#1265,
#1266,#1267,#1268,#1269,#1270,#1271,#1272,#1273,#1274,#1275,#1276,#1277,#1278,#1279,#1280,#1281,
#1282,#1283,#1284,#1285,#1286,#1287,#1288,#1289,#1290),.UNSPECIFIED.,.F.,.F.,(4,2,2,2,2,2,2,2,2,
2,2,2,2,2,2,2,2,2,2,2,2,2,2,2,2,2,2,2,2,2,2,2,4),(0.,0.176306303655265,0.35261260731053,
0.528918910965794,0.70522521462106,0.881531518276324,1.05783782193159,1.23414412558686,
1.41045042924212,1.58675673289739,1.76306303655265,1.93936934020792,2.11567564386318,
2.29198194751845,2.46828825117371,2.64459455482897,2.82090085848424,2.9972071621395,
3.17351346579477,3.34981976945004,3.5261260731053,3.70243237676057,3.87873868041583,
4.0550449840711,4.23135128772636,4.40765759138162,4.58396389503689,4.76027019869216,
4.93657650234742,5.11288280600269,5.28918910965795,5.46549541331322,5.64180171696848),.UNSPECIFIED.);
#1292=EDGE_CURVE('E1205',#234,#232,#1291,.T.);
#1293=ORIENTED_EDGE('',*,*,#1292,.T.);
#1294=ORIENTED_EDGE('',*,*,#256,.F.);
#1295=EDGE_LOOP('',(#1293,#1294));
#1296=FACE_BOUND('',#1295,.T.);
#1297=ADVANCED_FACE('F959',(#1296),#1224,.F.);
#1298=CARTESIAN_POINT('',(12.,25.430953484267,-0.497806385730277));
#1299=DIRECTION('',(-1.,0.,0.));
#1300=DIRECTION('',(0.,1.,0.));
#1301=AXIS2_PLACEMENT_3D('',#1298,#1299,#1300);
#1302=PLANE('',#1301);
#1303=ORIENTED_EDGE('',*,*,#1292,.F.);
#1304=ORIENTED_EDGE('',*,*,#235,.F.);
#1305=EDGE_LOOP('',(#1303,#1304));
#1306=FACE_BOUND('',#1305,.T.);
#1307=ADVANCED_FACE('F969',(#1306),#1302,.T.);
#1308=CARTESIAN_POINT('',(15.4,26.9000000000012,4.00000000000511));
#1309=DIRECTION('',(1.,0.,0.));
#1310=DIRECTION('',(0.,-0.552770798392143,-0.833333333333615));
#1311=AXIS2_PLACEMENT_3D('',#1308,#1309,#1310);
#1312=CYLINDRICAL_SURFACE('',#1311,3.0000000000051);
#1313=CARTESIAN_POINT('',(21.6,26.9000000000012,1.));
#1314=CARTESIAN_POINT('',(21.6,26.8633870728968,1.00021970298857));
#1315=CARTESIAN_POINT('',(21.6,26.8267766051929,1.00104524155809));
#1316=CARTESIAN_POINT('',(21.6,26.7535959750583,1.00393807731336));
#1317=CARTESIAN_POINT('',(21.6,26.7170258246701,1.00600567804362));
#1318=CARTESIAN_POINT('',(21.6,26.6439815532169,1.01141247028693));
#1319=CARTESIAN_POINT('',(21.6,26.6075074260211,1.01475157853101));
#1320=CARTESIAN_POINT('',(21.6,26.5347099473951,1.0227237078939));
#1321=CARTESIAN_POINT('',(21.6,26.4983865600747,1.02735640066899));
#1322=CARTESIAN_POINT('',(21.6,26.4259432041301,1.0379319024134));
#1323=CARTESIAN_POINT('',(21.6,26.389823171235,1.04387427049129));
#1324=CARTESIAN_POINT('',(21.6,26.3178373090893,1.05707872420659));
#1325=CARTESIAN_POINT('',(21.6,26.2819713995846,1.06434037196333));
#1326=CARTESIAN_POINT('',(21.6,26.2105425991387,1.0801864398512));
#1327=CARTESIAN_POINT('',(21.6,26.1749796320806,1.08877051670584));
#1328=CARTESIAN_POINT('',(21.6,26.1042035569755,1.10725789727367));
#1329=CARTESIAN_POINT('',(21.6,26.0689904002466,1.11716101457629));
#1330=CARTESIAN_POINT('',(21.6,25.9989587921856,1.13827633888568));
#1331=CARTESIAN_POINT('',(21.6,25.9641403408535,1.14948854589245));
#1332=CARTESIAN_POINT('',(21.6,25.8949409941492,1.17320534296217));
#1333=CARTESIAN_POINT('',(21.6,25.860560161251,1.18571011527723));
#1334=CARTESIAN_POINT('',(21.6,25.7922769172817,1.21198881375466));
#1335=CARTESIAN_POINT('',(21.6,25.758374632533,1.225763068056));
#1336=CARTESIAN_POINT('',(21.6,25.6910873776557,1.25455103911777));
#1337=CARTESIAN_POINT('',(21.6,25.6577025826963,1.26956516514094));
#1338=CARTESIAN_POINT('',(21.6,25.5914872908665,1.30079681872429));
#1339=CARTESIAN_POINT('',(21.6,25.5586569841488,1.31701474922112));
#1340=CARTESIAN_POINT('',(21.6,25.4935856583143,1.35061162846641));
#1341=CARTESIAN_POINT('',(21.6,25.4613447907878,1.3679908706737));
#1342=CARTESIAN_POINT('',(21.6,25.3974858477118,1.40386195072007));
#1343=CARTESIAN_POINT('',(21.6,25.3658678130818,1.42235386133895));
#1344=CARTESIAN_POINT('',(21.6,25.3032848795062,1.46039528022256));
#1345=CARTESIAN_POINT('',(21.6,25.2723198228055,1.47994452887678));
#1346=CARTESIAN_POINT('',(21.6,25.241687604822,1.5));
#1347=B_SPLINE_CURVE_WITH_KNOTS('',3,(#1313,#1314,#1315,#1316,#1317,#1318,#1319,#1320,#1321,
#1322,#1323,#1324,#1325,#1326,#1327,#1328,#1329,#1330,#1331,#1332,#1333,#1334,#1335,#1336,#1337,
#1338,#1339,#1340,#1341,#1342,#1343,#1344,#1345,#1346),.UNSPECIFIED.,.F.,.F.,(4,2,2,2,2,2,2,2,2,
2,2,2,2,2,2,2,4),(0.,0.109837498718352,0.21970185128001,0.329559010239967,0.439388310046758,
0.549180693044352,0.658936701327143,0.76866426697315,0.87837634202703,0.988088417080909,
1.09781598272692,1.20757199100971,1.3173643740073,1.42719367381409,1.53705083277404,
1.6469151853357,1.75675268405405),.UNSPECIFIED.);
#1348=CARTESIAN_POINT('',(21.6,26.9000000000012,1.));
#1349=VERTEX_POINT('',#1348);
#1350=EDGE_CURVE('E840',#419,#1349,#1347,.F.);
#1351=ORIENTED_EDGE('',*,*,#1350,.T.);
#1352=DIRECTION('',(-1.,-1.00851227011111E-13,0.));
#1353=VECTOR('',#1352,1.);
#1354=CARTESIAN_POINT('',(21.6,26.9000000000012,1.));
#1355=LINE('',#1354,#1353);
#1356=CARTESIAN_POINT('',(15.4,26.9000000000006,1.));
#1357=VERTEX_POINT('',#1356);
#1358=EDGE_CURVE('E1280',#1357,#1349,#1355,.F.);
#1359=ORIENTED_EDGE('',*,*,#1358,.F.);
#1360=CARTESIAN_POINT('',(15.4,26.9000000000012,4.00000000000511));
#1361=DIRECTION('',(-1.,0.,0.));
#1362=DIRECTION('',(0.,-2.08425869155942E-13,-1.));
#1363=AXIS2_PLACEMENT_3D('',#1360,#1361,#1362);
#1364=CIRCLE('',#1363,3.0000000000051);
#1365=EDGE_CURVE('E1365',#427,#1357,#1364,.F.);
#1366=ORIENTED_EDGE('',*,*,#1365,.F.);
#1367=ORIENTED_EDGE('',*,*,#428,.T.);
#1368=EDGE_LOOP('',(#1351,#1359,#1366,#1367));
#1369=FACE_BOUND('',#1368,.T.);
#1370=ADVANCED_FACE('F979',(#1369),#1312,.F.);
#1371=CARTESIAN_POINT('',(21.6,25.241687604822,1.));
#1372=DIRECTION('',(0.,0.,1.));
#1373=DIRECTION('',(0.,1.,0.));
#1374=AXIS2_PLACEMENT_3D('',#1371,#1372,#1373);
#1375=PLANE('',#1374);
#1376=DIRECTION('',(0.,1.,0.));
#1377=VECTOR('',#1376,1.);
#1378=CARTESIAN_POINT('',(21.6,26.9000000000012,1.));
#1379=LINE('',#1378,#1377);
#1380=CARTESIAN_POINT('',(21.6,29.1,1.));
#1381=VERTEX_POINT('',#1380);
#1382=EDGE_CURVE('E846',#1349,#1381,#1379,.T.);
#1383=ORIENTED_EDGE('',*,*,#1382,.T.);
#1384=DIRECTION('',(-1.,-1.00851227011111E-13,0.));
#1385=VECTOR('',#1384,1.);
#1386=CARTESIAN_POINT('',(21.6,29.1,1.));
#1387=LINE('',#1386,#1385);
#1388=CARTESIAN_POINT('',(15.4,29.0999999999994,1.));
#1389=VERTEX_POINT('',#1388);
#1390=EDGE_CURVE('E1358',#1389,#1381,#1387,.F.);
#1391=ORIENTED_EDGE('',*,*,#1390,.F.);
#1392=DIRECTION('',(0.,1.,0.));
#1393=VECTOR('',#1392,1.);
#1394=CARTESIAN_POINT('',(15.4,29.0999999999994,1.));
#1395=LINE('',#1394,#1393);
#1396=CARTESIAN_POINT('',(15.4,30.758312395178,1.));
#1397=VERTEX_POINT('',#1396);
#1398=EDGE_CURVE('E1353',#1389,#1397,#1395,.T.);
#1399=ORIENTED_EDGE('',*,*,#1398,.T.);
#1400=DIRECTION('',(-0.653895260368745,-0.756585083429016,0.));
#1401=VECTOR('',#1400,1.);
#1402=CARTESIAN_POINT('',(15.4,30.758312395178,1.));
#1403=LINE('',#1402,#1401);
#1404=CARTESIAN_POINT('',(12.8,27.75,1.));
#1405=VERTEX_POINT('',#1404);
#1406=EDGE_CURVE('E1343',#1397,#1405,#1403,.T.);
#1407=ORIENTED_EDGE('',*,*,#1406,.T.);
#1408=DIRECTION('',(0.719682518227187,-0.694303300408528,0.));
#1409=VECTOR('',#1408,1.);
#1410=CARTESIAN_POINT('',(12.8,27.75,1.));
#1411=LINE('',#1410,#1409);
#1412=CARTESIAN_POINT('',(15.4,25.241687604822,1.));
#1413=VERTEX_POINT('',#1412);
#1414=EDGE_CURVE('E1339',#1405,#1413,#1411,.T.);
#1415=ORIENTED_EDGE('',*,*,#1414,.T.);
#1416=DIRECTION('',(0.,1.,0.));
#1417=VECTOR('',#1416,1.);
#1418=CARTESIAN_POINT('',(15.4,25.241687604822,1.));
#1419=LINE('',#1418,#1417);
#1420=EDGE_CURVE('E1337',#1413,#1357,#1419,.T.);
#1421=ORIENTED_EDGE('',*,*,#1420,.T.);
#1422=ORIENTED_EDGE('',*,*,#1358,.T.);
#1423=EDGE_LOOP('',(#1383,#1391,#1399,#1407,#1415,#1421,#1422));
#1424=FACE_BOUND('',#1423,.T.);
#1425=ADVANCED_FACE('F989',(#1424),#1375,.T.);
#1426=CARTESIAN_POINT('',(15.4,29.0999999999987,4.0000000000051));
#1427=DIRECTION('',(1.,0.,0.));
#1428=DIRECTION('',(0.,2.09610107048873E-13,-1.));
#1429=AXIS2_PLACEMENT_3D('',#1426,#1427,#1428);
#1430=CYLINDRICAL_SURFACE('',#1429,3.0000000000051);
#1431=CARTESIAN_POINT('',(21.6,30.758312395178,1.5));
#1432=CARTESIAN_POINT('',(21.6,30.7276801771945,1.4799445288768));
#1433=CARTESIAN_POINT('',(21.6,30.6967151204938,1.46039528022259));
#1434=CARTESIAN_POINT('',(21.6,30.6341321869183,1.42235386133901));
#1435=CARTESIAN_POINT('',(21.6,30.6025141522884,1.40386195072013));
#1436=CARTESIAN_POINT('',(21.6,30.5386552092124,1.36799087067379));
#1437=CARTESIAN_POINT('',(21.6,30.5064143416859,1.3506116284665));
#1438=CARTESIAN_POINT('',(21.6,30.4413430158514,1.31701474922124));
#1439=CARTESIAN_POINT('',(21.6,30.4085127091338,1.30079681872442));
#1440=CARTESIAN_POINT('',(21.6,30.342297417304,1.26956516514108));
#1441=CARTESIAN_POINT('',(21.6,30.3089126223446,1.25455103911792));
#1442=CARTESIAN_POINT('',(21.6,30.2416253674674,1.22576306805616));
#1443=CARTESIAN_POINT('',(21.6,30.2077230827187,1.21198881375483));
#1444=CARTESIAN_POINT('',(21.6,30.1394398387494,1.1857101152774));
#1445=CARTESIAN_POINT('',(21.6,30.1050590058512,1.17320534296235));
#1446=CARTESIAN_POINT('',(21.6,30.035859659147,1.14948854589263));
#1447=CARTESIAN_POINT('',(21.6,30.001041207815,1.13827633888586));
#1448=CARTESIAN_POINT('',(21.6,29.9310095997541,1.11716101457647));
#1449=CARTESIAN_POINT('',(21.6,29.8957964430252,1.10725789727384));
#1450=CARTESIAN_POINT('',(21.6,29.8250203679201,1.08877051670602));
#1451=CARTESIAN_POINT('',(21.6,29.789457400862,1.08018643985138));
#1452=CARTESIAN_POINT('',(21.6,29.7180286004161,1.06434037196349));
#1453=CARTESIAN_POINT('',(21.6,29.6821626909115,1.05707872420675));
#1454=CARTESIAN_POINT('',(21.6,29.6101768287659,1.04387427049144));
#1455=CARTESIAN_POINT('',(21.6,29.5740567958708,1.03793190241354));
#1456=CARTESIAN_POINT('',(21.6,29.5016134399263,1.02735640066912));
#1457=CARTESIAN_POINT('',(21.6,29.4652900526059,1.02272370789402));
#1458=CARTESIAN_POINT('',(21.6,29.3924925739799,1.01475157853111));
#1459=CARTESIAN_POINT('',(21.6,29.3560184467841,1.01141247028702));
#1460=CARTESIAN_POINT('',(21.6,29.282974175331,1.00600567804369));
#1461=CARTESIAN_POINT('',(21.6,29.2464040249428,1.00393807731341));
#1462=CARTESIAN_POINT('',(21.6,29.1732233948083,1.00104524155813));
#1463=CARTESIAN_POINT('',(21.6,29.1366129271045,1.00021970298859));
#1464=CARTESIAN_POINT('',(21.6,29.1,1.00000000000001));
#1465=B_SPLINE_CURVE_WITH_KNOTS('',3,(#1431,#1432,#1433,#1434,#1435,#1436,#1437,#1438,#1439,
#1440,#1441,#1442,#1443,#1444,#1445,#1446,#1447,#1448,#1449,#1450,#1451,#1452,#1453,#1454,#1455,
#1456,#1457,#1458,#1459,#1460,#1461,#1462,#1463,#1464),.UNSPECIFIED.,.F.,.F.,(4,2,2,2,2,2,2,2,2,
2,2,2,2,2,2,2,4),(0.,0.109837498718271,0.219701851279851,0.32955901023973,0.439388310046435,
0.549180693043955,0.658936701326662,0.768664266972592,0.878376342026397,0.988088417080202,
1.09781598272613,1.20757199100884,1.31736437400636,1.42719367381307,1.53705083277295,
1.64691518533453,1.7567526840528),.UNSPECIFIED.);
#1466=EDGE_CURVE('E1307',#1381,#333,#1465,.F.);
#1467=ORIENTED_EDGE('',*,*,#1466,.T.);
#1468=ORIENTED_EDGE('',*,*,#334,.F.);
#1469=CARTESIAN_POINT('',(15.4,29.0999999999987,4.0000000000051));
#1470=DIRECTION('',(-1.,0.,0.));
#1471=DIRECTION('',(0.,0.552770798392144,-0.833333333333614));
#1472=AXIS2_PLACEMENT_3D('',#1469,#1470,#1471);
#1473=CIRCLE('',#1472,3.0000000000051);
#1474=EDGE_CURVE('E1299',#1389,#323,#1473,.F.);
#1475=ORIENTED_EDGE('',*,*,#1474,.F.);
#1476=ORIENTED_EDGE('',*,*,#1390,.T.);
#1477=EDGE_LOOP('',(#1467,#1468,#1475,#1476));
#1478=FACE_BOUND('',#1477,.T.);
#1479=ADVANCED_FACE('F999',(#1478),#1430,.F.);
#1480=CARTESIAN_POINT('',(21.6,29.0999999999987,1.));
#1481=CARTESIAN_POINT('',(21.6,30.0028946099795,1.00543735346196));
#1482=CARTESIAN_POINT('',(21.6,30.758312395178,1.5));
#1483=CARTESIAN_POINT('',(21.7963495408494,29.0999999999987,1.));
#1484=CARTESIAN_POINT('',(21.794214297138,30.0028946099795,1.00543735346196));
#1485=CARTESIAN_POINT('',(21.6,30.758312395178,1.5));
#1486=CARTESIAN_POINT('',(21.9952426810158,29.0999999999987,1.10475731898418));
#1487=CARTESIAN_POINT('',(21.990944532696,30.0028946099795,1.10905546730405));
#1488=CARTESIAN_POINT('',(21.6,30.758312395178,1.5));
#1489=CARTESIAN_POINT('',(22.1,29.0999999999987,1.30365045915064));
#1490=CARTESIAN_POINT('',(22.0945626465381,30.0028946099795,1.30578570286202));
#1491=CARTESIAN_POINT('',(21.6,30.758312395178,1.5));
#1492=CARTESIAN_POINT('',(22.1,29.0999999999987,1.5));
#1493=CARTESIAN_POINT('',(22.0945626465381,30.0028946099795,1.5));
#1494=CARTESIAN_POINT('',(21.6,30.758312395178,1.5));
#1495=B_SPLINE_SURFACE_WITH_KNOTS('',4,2,((#1480,#1481,#1482),(#1483,#1484,#1485),(#1486,#1487,
#1488),(#1489,#1490,#1491),(#1492,#1493,#1494)),.UNSPECIFIED.,.F.,.F.,.F.,(5,5),(3,3),(0.,1.),
(0.,1.),.UNSPECIFIED.);
#1496=CARTESIAN_POINT('',(21.6,29.1,1.00000000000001));
#1497=CARTESIAN_POINT('',(21.608185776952,29.1,0.999999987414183));
#1498=CARTESIAN_POINT('',(21.6163713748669,29.1,1.00020482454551));
#1499=CARTESIAN_POINT('',(21.6327293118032,29.1,1.00102038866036));
#1500=CARTESIAN_POINT('',(21.6409016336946,29.1,1.00163145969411));
#1501=CARTESIAN_POINT('',(21.6572103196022,29.0999999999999,1.00325608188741));
#1502=CARTESIAN_POINT('',(21.665346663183,29.0999999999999,1.00426983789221));
#1503=CARTESIAN_POINT('',(21.6815614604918,29.0999999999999,1.00669572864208));
#1504=CARTESIAN_POINT('',(21.6896399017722,29.0999999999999,1.00810794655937));
#1505=CARTESIAN_POINT('',(21.7057175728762,29.0999999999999,1.01132599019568));
#1506=CARTESIAN_POINT('',(21.7137168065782,29.0999999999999,1.01313179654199));
#1507=CARTESIAN_POINT('',(21.7296153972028,29.0999999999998,1.0171315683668));
#1508=CARTESIAN_POINT('',(21.7375147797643,29.0999999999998,1.01932543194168));
#1509=CARTESIAN_POINT('',(21.753193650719,29.0999999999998,1.02409519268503));
#1510=CARTESIAN_POINT('',(21.7609731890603,29.0999999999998,1.02667092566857));
#1511=CARTESIAN_POINT('',(21.7763930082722,29.0999999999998,1.03219762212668));
#1512=CARTESIAN_POINT('',(21.7840333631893,29.0999999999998,1.03514837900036));
#1513=CARTESIAN_POINT('',(21.7991561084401,29.0999999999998,1.04141764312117));
#1514=CARTESIAN_POINT('',(21.8066385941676,29.0999999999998,1.04473592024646));
#1515=CARTESIAN_POINT('',(21.8214275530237,29.0999999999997,1.05173206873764));
#1516=CARTESIAN_POINT('',(21.8287341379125,29.0999999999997,1.05540970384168));
#1517=CARTESIAN_POINT('',(21.8431539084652,29.0999999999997,1.06311573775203));
#1518=CARTESIAN_POINT('',(21.8502672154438,29.0999999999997,1.06714390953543));
#1519=CARTESIAN_POINT('',(21.8642837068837,29.0999999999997,1.07554151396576));
#1520=CARTESIAN_POINT('',(21.8711870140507,29.0999999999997,1.07991074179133));
#1521=CARTESIAN_POINT('',(21.8847674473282,29.0999999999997,1.08898028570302));
#1522=CARTESIAN_POINT('',(21.8914446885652,29.0999999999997,1.09368042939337));
#1523=CARTESIAN_POINT('',(21.9045575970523,29.0999999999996,1.10340096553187));
#1524=CARTESIAN_POINT('',(21.910993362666,29.0999999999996,1.108421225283));
#1525=CARTESIAN_POINT('',(21.9236085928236,29.0999999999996,1.11877049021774));
#1526=CARTESIAN_POINT('',(21.9297881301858,29.0999999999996,1.124099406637));
#1527=CARTESIAN_POINT('',(21.941876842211,29.0999999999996,1.13505382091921));
#1528=CARTESIAN_POINT('',(21.9477860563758,29.0999999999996,1.14067927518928));
#1529=CARTESIAN_POINT('',(21.9593207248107,29.0999999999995,1.15221394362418));
#1530=CARTESIAN_POINT('',(21.9649461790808,29.0999999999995,1.158123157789));
#1531=CARTESIAN_POINT('',(21.975900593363,29.0999999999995,1.17021186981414));
#1532=CARTESIAN_POINT('',(21.9812295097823,29.0999999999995,1.17639140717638));
#1533=CARTESIAN_POINT('',(21.991578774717,29.0999999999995,1.18900663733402));
#1534=CARTESIAN_POINT('',(21.9965990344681,29.0999999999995,1.19544240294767));
#1535=CARTESIAN_POINT('',(22.0063195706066,29.0999999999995,1.2085553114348));
#1536=CARTESIAN_POINT('',(22.011019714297,29.0999999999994,1.21523255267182));
#1537=CARTESIAN_POINT('',(22.0200892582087,29.0999999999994,1.22881298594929));
#1538=CARTESIAN_POINT('',(22.0244584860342,29.0999999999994,1.23571629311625));
#1539=CARTESIAN_POINT('',(22.0328560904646,29.0999999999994,1.24973278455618));
#1540=CARTESIAN_POINT('',(22.036884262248,29.0999999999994,1.25684609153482));
#1541=CARTESIAN_POINT('',(22.0445902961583,29.0999999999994,1.27126586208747));
#1542=CARTESIAN_POINT('',(22.0482679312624,29.0999999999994,1.27857244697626));
#1543=CARTESIAN_POINT('',(22.0552640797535,29.0999999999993,1.2933614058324));
#1544=CARTESIAN_POINT('',(22.0585823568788,29.0999999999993,1.30084389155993));
#1545=CARTESIAN_POINT('',(22.0648516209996,29.0999999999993,1.31596663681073));
#1546=CARTESIAN_POINT('',(22.0678023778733,29.0999999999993,1.32360699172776));
#1547=CARTESIAN_POINT('',(22.0733290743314,29.0999999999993,1.33902681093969));
#1548=CARTESIAN_POINT('',(22.075904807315,29.0999999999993,1.34680634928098));
#1549=CARTESIAN_POINT('',(22.0806745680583,29.0999999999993,1.36248522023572));
#1550=CARTESIAN_POINT('',(22.0828684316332,29.0999999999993,1.37038460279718));
#1551=CARTESIAN_POINT('',(22.086868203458,29.0999999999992,1.38628319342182));
#1552=CARTESIAN_POINT('',(22.0886740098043,29.0999999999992,1.39428242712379));
#1553=CARTESIAN_POINT('',(22.0918920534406,29.0999999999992,1.41036009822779));
#1554=CARTESIAN_POINT('',(22.0933042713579,29.0999999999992,1.41843853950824));
#1555=CARTESIAN_POINT('',(22.0957301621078,29.0999999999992,1.43465333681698));
#1556=CARTESIAN_POINT('',(22.0967439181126,29.0999999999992,1.44278968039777));
#1557=CARTESIAN_POINT('',(22.0983685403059,29.0999999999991,1.45909836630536));
#1558=CARTESIAN_POINT('',(22.0989796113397,29.0999999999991,1.46727068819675));
#1559=CARTESIAN_POINT('',(22.0997951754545,29.0999999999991,1.48362862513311));
#1560=CARTESIAN_POINT('',(22.1000000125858,29.0999999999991,1.49181422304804));
#1561=CARTESIAN_POINT('',(22.1,29.0999999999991,1.5));
#1562=B_SPLINE_CURVE_WITH_KNOTS('',3,(#1496,#1497,#1498,#1499,#1500,#1501,#1502,#1503,#1504,
#1505,#1506,#1507,#1508,#1509,#1510,#1511,#1512,#1513,#1514,#1515,#1516,#1517,#1518,#1519,#1520,
#1521,#1522,#1523,#1524,#1525,#1526,#1527,#1528,#1529,#1530,#1531,#1532,#1533,#1534,#1535,#1536,
#1537,#1538,#1539,#1540,#1541,#1542,#1543,#1544,#1545,#1546,#1547,#1548,#1549,#1550,#1551,#1552,
#1553,#1554,#1555,#1556,#1557,#1558,#1559,#1560,#1561),.UNSPECIFIED.,.F.,.F.,(4,2,2,2,2,2,2,2,2,
2,2,2,2,2,2,2,2,2,2,2,2,2,2,2,2,2,2,2,2,2,2,2,4),(0.,0.0245545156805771,0.0491298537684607,
0.0737177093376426,0.0983107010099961,0.122902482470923,0.147487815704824,0.172062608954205,
0.196623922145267,0.221169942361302,0.245699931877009,0.270214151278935,0.294713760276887,
0.31920069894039,0.343677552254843,0.368147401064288,0.392613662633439,0.417079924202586,
0.441549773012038,0.466026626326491,0.490513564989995,0.515013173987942,0.539527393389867,
0.564057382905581,0.588603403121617,0.613164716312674,0.637739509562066,0.662324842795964,
0.686916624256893,0.71150961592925,0.736097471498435,0.760672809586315,0.785227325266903),.UNSPECIFIED.);
#1563=EDGE_CURVE('E847',#1381,#372,#1562,.T.);
#1564=ORIENTED_EDGE('',*,*,#1563,.T.);
#1565=ORIENTED_EDGE('',*,*,#373,.T.);
#1566=ORIENTED_EDGE('',*,*,#1466,.F.);
#1567=EDGE_LOOP('',(#1564,#1565,#1566));
#1568=FACE_BOUND('',#1567,.T.);
#1569=ADVANCED_FACE('F1009',(#1568),#1495,.T.);
#1570=CARTESIAN_POINT('',(21.6,25.241687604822,1.5));
#1571=DIRECTION('',(0.,-1.,0.));
#1572=DIRECTION('',(0.,0.,-1.));
#1573=AXIS2_PLACEMENT_3D('',#1570,#1571,#1572);
#1574=CYLINDRICAL_SURFACE('',#1573,0.5);
#1575=CARTESIAN_POINT('',(22.1,26.9000000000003,1.5));
#1576=CARTESIAN_POINT('',(22.1000000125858,26.9000000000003,1.49181422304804));
#1577=CARTESIAN_POINT('',(22.0997951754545,26.9000000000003,1.48362862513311));
#1578=CARTESIAN_POINT('',(22.0989796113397,26.9000000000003,1.46727068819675));
#1579=CARTESIAN_POINT('',(22.0983685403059,26.9000000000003,1.45909836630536));
#1580=CARTESIAN_POINT('',(22.0967439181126,26.9000000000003,1.44278968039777));
#1581=CARTESIAN_POINT('',(22.0957301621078,26.9000000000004,1.43465333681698));
#1582=CARTESIAN_POINT('',(22.0933042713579,26.9000000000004,1.41843853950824));
#1583=CARTESIAN_POINT('',(22.0918920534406,26.9000000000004,1.41036009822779));
#1584=CARTESIAN_POINT('',(22.0886740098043,26.9000000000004,1.39428242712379));
#1585=CARTESIAN_POINT('',(22.086868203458,26.9000000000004,1.38628319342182));
#1586=CARTESIAN_POINT('',(22.0828684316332,26.9000000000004,1.37038460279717));
#1587=CARTESIAN_POINT('',(22.0806745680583,26.9000000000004,1.36248522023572));
#1588=CARTESIAN_POINT('',(22.075904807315,26.9000000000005,1.34680634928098));
#1589=CARTESIAN_POINT('',(22.0733290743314,26.9000000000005,1.33902681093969));
#1590=CARTESIAN_POINT('',(22.0678023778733,26.9000000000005,1.32360699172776));
#1591=CARTESIAN_POINT('',(22.0648516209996,26.9000000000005,1.31596663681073));
#1592=CARTESIAN_POINT('',(22.0585823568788,26.9000000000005,1.30084389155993));
#1593=CARTESIAN_POINT('',(22.0552640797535,26.9000000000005,1.2933614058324));
#1594=CARTESIAN_POINT('',(22.0482679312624,26.9000000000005,1.27857244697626));
#1595=CARTESIAN_POINT('',(22.0445902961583,26.9000000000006,1.27126586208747));
#1596=CARTESIAN_POINT('',(22.036884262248,26.9000000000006,1.25684609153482));
#1597=CARTESIAN_POINT('',(22.0328560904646,26.9000000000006,1.24973278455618));
#1598=CARTESIAN_POINT('',(22.0244584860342,26.9000000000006,1.23571629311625));
#1599=CARTESIAN_POINT('',(22.0200892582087,26.9000000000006,1.22881298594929));
#1600=CARTESIAN_POINT('',(22.011019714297,26.9000000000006,1.21523255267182));
#1601=CARTESIAN_POINT('',(22.0063195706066,26.9000000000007,1.2085553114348));
#1602=CARTESIAN_POINT('',(21.9965990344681,26.9000000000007,1.19544240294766));
#1603=CARTESIAN_POINT('',(21.991578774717,26.9000000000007,1.18900663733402));
#1604=CARTESIAN_POINT('',(21.9812295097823,26.9000000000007,1.17639140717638));
#1605=CARTESIAN_POINT('',(21.975900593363,26.9000000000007,1.17021186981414));
#1606=CARTESIAN_POINT('',(21.9649461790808,26.9000000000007,1.158123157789));
#1607=CARTESIAN_POINT('',(21.9593207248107,26.9000000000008,1.15221394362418));
#1608=CARTESIAN_POINT('',(21.9477860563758,26.9000000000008,1.14067927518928));
#1609=CARTESIAN_POINT('',(21.941876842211,26.9000000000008,1.13505382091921));
#1610=CARTESIAN_POINT('',(21.9297881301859,26.9000000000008,1.124099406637));
#1611=CARTESIAN_POINT('',(21.9236085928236,26.9000000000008,1.11877049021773));
#1612=CARTESIAN_POINT('',(21.910993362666,26.9000000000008,1.108421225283));
#1613=CARTESIAN_POINT('',(21.9045575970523,26.9000000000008,1.10340096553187));
#1614=CARTESIAN_POINT('',(21.8914446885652,26.9000000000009,1.09368042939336));
#1615=CARTESIAN_POINT('',(21.8847674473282,26.9000000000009,1.08898028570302));
#1616=CARTESIAN_POINT('',(21.8711870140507,26.9000000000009,1.07991074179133));
#1617=CARTESIAN_POINT('',(21.8642837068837,26.9000000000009,1.07554151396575));
#1618=CARTESIAN_POINT('',(21.8502672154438,26.9000000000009,1.06714390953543));
#1619=CARTESIAN_POINT('',(21.8431539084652,26.9000000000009,1.06311573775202));
#1620=CARTESIAN_POINT('',(21.8287341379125,26.900000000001,1.05540970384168));
#1621=CARTESIAN_POINT('',(21.8214275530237,26.900000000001,1.05173206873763));
#1622=CARTESIAN_POINT('',(21.8066385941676,26.900000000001,1.04473592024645));
#1623=CARTESIAN_POINT('',(21.7991561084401,26.900000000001,1.04141764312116));
#1624=CARTESIAN_POINT('',(21.7840333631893,26.900000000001,1.03514837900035));
#1625=CARTESIAN_POINT('',(21.7763930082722,26.900000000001,1.03219762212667));
#1626=CARTESIAN_POINT('',(21.7609731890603,26.900000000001,1.02667092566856));
#1627=CARTESIAN_POINT('',(21.753193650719,26.9000000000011,1.02409519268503));
#1628=CARTESIAN_POINT('',(21.7375147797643,26.9000000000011,1.01932543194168));
#1629=CARTESIAN_POINT('',(21.7296153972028,26.9000000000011,1.01713156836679));
#1630=CARTESIAN_POINT('',(21.7137168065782,26.9000000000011,1.01313179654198));
#1631=CARTESIAN_POINT('',(21.7057175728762,26.9000000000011,1.01132599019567));
#1632=CARTESIAN_POINT('',(21.6896399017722,26.9000000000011,1.00810794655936));
#1633=CARTESIAN_POINT('',(21.6815614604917,26.9000000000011,1.00669572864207));
#1634=CARTESIAN_POINT('',(21.665346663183,26.9000000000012,1.0042698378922));
#1635=CARTESIAN_POINT('',(21.6572103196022,26.9000000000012,1.0032560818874));
#1636=CARTESIAN_POINT('',(21.6409016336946,26.9000000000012,1.0016314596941));
#1637=CARTESIAN_POINT('',(21.6327293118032,26.9000000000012,1.00102038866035));
#1638=CARTESIAN_POINT('',(21.6163713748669,26.9000000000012,1.0002048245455));
#1639=CARTESIAN_POINT('',(21.608185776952,26.9000000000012,0.999999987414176));
#1640=CARTESIAN_POINT('',(21.6,26.9000000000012,1.));
#1641=B_SPLINE_CURVE_WITH_KNOTS('',3,(#1575,#1576,#1577,#1578,#1579,#1580,#1581,#1582,#1583,
#1584,#1585,#1586,#1587,#1588,#1589,#1590,#1591,#1592,#1593,#1594,#1595,#1596,#1597,#1598,#1599,
#1600,#1601,#1602,#1603,#1604,#1605,#1606,#1607,#1608,#1609,#1610,#1611,#1612,#1613,#1614,#1615,
#1616,#1617,#1618,#1619,#1620,#1621,#1622,#1623,#1624,#1625,#1626,#1627,#1628,#1629,#1630,#1631,
#1632,#1633,#1634,#1635,#1636,#1637,#1638,#1639,#1640),.UNSPECIFIED.,.F.,.F.,(4,2,2,2,2,2,2,2,2,
2,2,2,2,2,2,2,2,2,2,2,2,2,2,2,2,2,2,2,2,2,2,2,4),(0.,0.0245545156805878,0.0491298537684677,
0.0737177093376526,0.0983107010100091,0.122902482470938,0.147487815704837,0.172062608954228,
0.196623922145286,0.22116994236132,0.245699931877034,0.270214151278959,0.294713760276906,
0.31920069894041,0.343677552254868,0.368147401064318,0.392613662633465,0.417079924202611,
0.441549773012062,0.466026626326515,0.490513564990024,0.515013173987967,0.539527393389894,
0.56405738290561,0.588603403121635,0.613164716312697,0.637739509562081,0.66232484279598,
0.686916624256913,0.711509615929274,0.736097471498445,0.760672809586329,0.785227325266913),.UNSPECIFIED.);
#1642=EDGE_CURVE('E795',#1349,#380,#1641,.F.);
#1643=ORIENTED_EDGE('',*,*,#1642,.T.);
#1644=ORIENTED_EDGE('',*,*,#381,.F.);
#1645=ORIENTED_EDGE('',*,*,#1563,.F.);
#1646=ORIENTED_EDGE('',*,*,#1382,.F.);
#1647=EDGE_LOOP('',(#1643,#1644,#1645,#1646));
#1648=FACE_BOUND('',#1647,.T.);
#1649=ADVANCED_FACE('F814',(#1648),#1574,.F.);
#1650=CARTESIAN_POINT('',(21.6,25.241687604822,1.5));
#1651=CARTESIAN_POINT('',(21.6,25.9971053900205,1.00543735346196));
#1652=CARTESIAN_POINT('',(21.6,26.9000000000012,1.));
#1653=CARTESIAN_POINT('',(21.6,25.241687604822,1.5));
#1654=CARTESIAN_POINT('',(21.794214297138,25.9971053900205,1.00543735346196));
#1655=CARTESIAN_POINT('',(21.7963495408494,26.9000000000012,1.));
#1656=CARTESIAN_POINT('',(21.6,25.241687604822,1.5));
#1657=CARTESIAN_POINT('',(21.990944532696,25.9971053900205,1.10905546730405));
#1658=CARTESIAN_POINT('',(21.9952426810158,26.9000000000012,1.10475731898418));
#1659=CARTESIAN_POINT('',(21.6,25.241687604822,1.5));
#1660=CARTESIAN_POINT('',(22.0945626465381,25.9971053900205,1.30578570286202));
#1661=CARTESIAN_POINT('',(22.1,26.9000000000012,1.30365045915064));
#1662=CARTESIAN_POINT('',(21.6,25.241687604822,1.5));
#1663=CARTESIAN_POINT('',(22.0945626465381,25.9971053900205,1.5));
#1664=CARTESIAN_POINT('',(22.1,26.9000000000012,1.5));
#1665=B_SPLINE_SURFACE_WITH_KNOTS('',4,2,((#1650,#1651,#1652),(#1653,#1654,#1655),(#1656,#1657,
#1658),(#1659,#1660,#1661),(#1662,#1663,#1664)),.UNSPECIFIED.,.F.,.F.,.F.,(5,5),(3,3),(0.,1.),
(0.,1.),.UNSPECIFIED.);
#1666=ORIENTED_EDGE('',*,*,#1350,.F.);
#1667=ORIENTED_EDGE('',*,*,#420,.T.);
#1668=ORIENTED_EDGE('',*,*,#1642,.F.);
#1669=EDGE_LOOP('',(#1666,#1667,#1668));
#1670=FACE_BOUND('',#1669,.T.);
#1671=ADVANCED_FACE('F801',(#1670),#1665,.T.);
#1672=CARTESIAN_POINT('',(15.4,25.241687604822,1.5));
#1673=DIRECTION('',(-1.,0.,0.));
#1674=DIRECTION('',(0.,1.,0.));
#1675=AXIS2_PLACEMENT_3D('',#1672,#1673,#1674);
#1676=PLANE('',#1675);
#1677=ORIENTED_EDGE('',*,*,#1420,.F.);
#1678=DIRECTION('',(0.,0.,1.));
#1679=VECTOR('',#1678,1.);
#1680=CARTESIAN_POINT('',(15.4,25.241687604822,1.));
#1681=LINE('',#1680,#1679);
#1682=EDGE_CURVE('E790',#1413,#427,#1681,.T.);
#1683=ORIENTED_EDGE('',*,*,#1682,.T.);
#1684=ORIENTED_EDGE('',*,*,#1365,.T.);
#1685=EDGE_LOOP('',(#1677,#1683,#1684));
#1686=FACE_BOUND('',#1685,.T.);
#1687=ADVANCED_FACE('F813',(#1686),#1676,.T.);
#1688=CARTESIAN_POINT('',(15.4,29.0999999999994,1.5));
#1689=DIRECTION('',(-1.,0.,0.));
#1690=DIRECTION('',(0.,1.,0.));
#1691=AXIS2_PLACEMENT_3D('',#1688,#1689,#1690);
#1692=PLANE('',#1691);
#1693=DIRECTION('',(0.,0.,-1.));
#1694=VECTOR('',#1693,1.);
#1695=CARTESIAN_POINT('',(15.4,30.758312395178,1.5));
#1696=LINE('',#1695,#1694);
#1697=EDGE_CURVE('E786',#1397,#323,#1696,.F.);
#1698=ORIENTED_EDGE('',*,*,#1697,.F.);
#1699=ORIENTED_EDGE('',*,*,#1398,.F.);
#1700=ORIENTED_EDGE('',*,*,#1474,.T.);
#1701=EDGE_LOOP('',(#1698,#1699,#1700));
#1702=FACE_BOUND('',#1701,.T.);
#1703=ADVANCED_FACE('F1040',(#1702),#1692,.T.);
#1704=CARTESIAN_POINT('',(15.4,30.758312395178,1.));
#1705=DIRECTION('',(0.756585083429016,-0.653895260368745,0.));
#1706=DIRECTION('',(0.,0.,1.));
#1707=AXIS2_PLACEMENT_3D('',#1704,#1705,#1706);
#1708=PLANE('',#1707);
#1709=ORIENTED_EDGE('',*,*,#326,.T.);
#1710=DIRECTION('',(0.,0.,-1.));
#1711=VECTOR('',#1710,1.);
#1712=CARTESIAN_POINT('',(12.8,27.75,1.5));
#1713=LINE('',#1712,#1711);
#1714=EDGE_CURVE('E782',#1405,#325,#1713,.F.);
#1715=ORIENTED_EDGE('',*,*,#1714,.F.);
#1716=ORIENTED_EDGE('',*,*,#1406,.F.);
#1717=ORIENTED_EDGE('',*,*,#1697,.T.);
#1718=EDGE_LOOP('',(#1709,#1715,#1716,#1717));
#1719=FACE_BOUND('',#1718,.T.);
#1720=ADVANCED_FACE('F1049',(#1719),#1708,.T.);
#1721=CARTESIAN_POINT('',(12.8,27.75,1.));
#1722=DIRECTION('',(0.694303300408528,0.719682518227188,0.));
#1723=DIRECTION('',(0.,0.,1.));
#1724=AXIS2_PLACEMENT_3D('',#1721,#1722,#1723);
#1725=PLANE('',#1724);
#1726=ORIENTED_EDGE('',*,*,#434,.T.);
#1727=ORIENTED_EDGE('',*,*,#1682,.F.);
#1728=ORIENTED_EDGE('',*,*,#1414,.F.);
#1729=ORIENTED_EDGE('',*,*,#1714,.T.);
#1730=EDGE_LOOP('',(#1726,#1727,#1728,#1729));
#1731=FACE_BOUND('',#1730,.T.);
#1732=ADVANCED_FACE('F1058',(#1731),#1725,.T.);
#1733=CARTESIAN_POINT('',(12.8,27.75,-1.5));
#1734=DIRECTION('',(0.756585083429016,-0.653895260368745,0.));
#1735=DIRECTION('',(0.653895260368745,0.756585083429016,0.));
#1736=AXIS2_PLACEMENT_3D('',#1733,#1734,#1735);
#1737=PLANE('',#1736);
#1738=ORIENTED_EDGE('',*,*,#223,.F.);
#1739=DIRECTION('',(0.,0.,1.));
#1740=VECTOR('',#1739,1.);
#1741=CARTESIAN_POINT('',(15.4,30.758312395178,-1.5));
#1742=LINE('',#1741,#1740);
#1743=CARTESIAN_POINT('',(15.4,30.758312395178,-1.));
#1744=VERTEX_POINT('',#1743);
#1745=EDGE_CURVE('E777',#1744,#216,#1742,.F.);
#1746=ORIENTED_EDGE('',*,*,#1745,.F.);
#1747=DIRECTION('',(-0.653895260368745,-0.756585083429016,0.));
#1748=VECTOR('',#1747,1.);
#1749=CARTESIAN_POINT('',(15.4,30.758312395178,-1.));
#1750=LINE('',#1749,#1748);
#1751=CARTESIAN_POINT('',(12.8,27.75,-1.));
#1752=VERTEX_POINT('',#1751);
#1753=EDGE_CURVE('E772',#1744,#1752,#1750,.T.);
#1754=ORIENTED_EDGE('',*,*,#1753,.T.);
#1755=DIRECTION('',(0.,0.,-1.));
#1756=VECTOR('',#1755,1.);
#1757=CARTESIAN_POINT('',(12.8,27.75,-1.));
#1758=LINE('',#1757,#1756);
#1759=EDGE_CURVE('E768',#1752,#114,#1758,.T.);
#1760=ORIENTED_EDGE('',*,*,#1759,.T.);
#1761=EDGE_LOOP('',(#1738,#1746,#1754,#1760));
#1762=FACE_BOUND('',#1761,.T.);
#1763=ADVANCED_FACE('F1068',(#1762),#1737,.T.);
#1764=CARTESIAN_POINT('',(15.4,25.241687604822,-1.5));
#1765=DIRECTION('',(0.694303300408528,0.719682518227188,0.));
#1766=DIRECTION('',(-0.719682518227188,0.694303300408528,0.));
#1767=AXIS2_PLACEMENT_3D('',#1764,#1765,#1766);
#1768=PLANE('',#1767);
#1769=ORIENTED_EDGE('',*,*,#115,.F.);
#1770=ORIENTED_EDGE('',*,*,#1759,.F.);
#1771=DIRECTION('',(0.719682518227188,-0.694303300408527,0.));
#1772=VECTOR('',#1771,1.);
#1773=CARTESIAN_POINT('',(12.8,27.75,-1.));
#1774=LINE('',#1773,#1772);
#1775=EDGE_CURVE('E214',#1752,#40,#1774,.T.);
#1776=ORIENTED_EDGE('',*,*,#1775,.T.);
#1777=ORIENTED_EDGE('',*,*,#41,.T.);
#1778=EDGE_LOOP('',(#1769,#1770,#1776,#1777));
#1779=FACE_BOUND('',#1778,.T.);
#1780=ADVANCED_FACE('F211',(#1779),#1768,.T.);
#1781=CARTESIAN_POINT('',(15.4,29.1,-1.5));
#1782=DIRECTION('',(-1.,0.,0.));
#1783=DIRECTION('',(0.,0.,1.));
#1784=AXIS2_PLACEMENT_3D('',#1781,#1782,#1783);
#1785=PLANE('',#1784);
#1786=CARTESIAN_POINT('',(15.4,29.0999999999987,-4.00000000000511));
#1787=DIRECTION('',(1.,0.,0.));
#1788=DIRECTION('',(0.,0.552770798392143,0.833333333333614));
#1789=AXIS2_PLACEMENT_3D('',#1786,#1787,#1788);
#1790=CIRCLE('',#1789,3.0000000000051);
#1791=CARTESIAN_POINT('',(15.4,29.1,-1.));
#1792=VERTEX_POINT('',#1791);
#1793=EDGE_CURVE('E760',#216,#1792,#1790,.T.);
#1794=ORIENTED_EDGE('',*,*,#1793,.T.);
#1795=DIRECTION('',(0.,1.,0.));
#1796=VECTOR('',#1795,1.);
#1797=CARTESIAN_POINT('',(15.4,29.1,-1.));
#1798=LINE('',#1797,#1796);
#1799=EDGE_CURVE('E755',#1792,#1744,#1798,.T.);
#1800=ORIENTED_EDGE('',*,*,#1799,.T.);
#1801=ORIENTED_EDGE('',*,*,#1745,.T.);
#1802=EDGE_LOOP('',(#1794,#1800,#1801));
#1803=FACE_BOUND('',#1802,.T.);
#1804=ADVANCED_FACE('F1087',(#1803),#1785,.T.);
#1805=CARTESIAN_POINT('',(12.8,25.241687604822,-1.));
#1806=DIRECTION('',(0.,0.,-1.));
#1807=DIRECTION('',(0.,1.,0.));
#1808=AXIS2_PLACEMENT_3D('',#1805,#1806,#1807);
#1809=PLANE('',#1808);
#1810=ORIENTED_EDGE('',*,*,#1753,.F.);
#1811=ORIENTED_EDGE('',*,*,#1799,.F.);
#1812=DIRECTION('',(1.,0.,0.));
#1813=VECTOR('',#1812,1.);
#1814=CARTESIAN_POINT('',(15.4,29.1,-1.));
#1815=LINE('',#1814,#1813);
#1816=CARTESIAN_POINT('',(21.6,29.1,-1.));
#1817=VERTEX_POINT('',#1816);
#1818=EDGE_CURVE('E751',#1792,#1817,#1815,.T.);
#1819=ORIENTED_EDGE('',*,*,#1818,.T.);
#1820=DIRECTION('',(0.,-1.,0.));
#1821=VECTOR('',#1820,1.);
#1822=CARTESIAN_POINT('',(21.6,29.1,-1.));
#1823=LINE('',#1822,#1821);
#1824=CARTESIAN_POINT('',(21.6,26.9,-1.));
#1825=VERTEX_POINT('',#1824);
#1826=EDGE_CURVE('E747',#1825,#1817,#1823,.F.);
#1827=ORIENTED_EDGE('',*,*,#1826,.F.);
#1828=DIRECTION('',(-1.,0.,0.));
#1829=VECTOR('',#1828,1.);
#1830=CARTESIAN_POINT('',(21.6,26.9,-1.));
#1831=LINE('',#1830,#1829);
#1832=EDGE_CURVE('E745',#30,#1825,#1831,.F.);
#1833=ORIENTED_EDGE('',*,*,#1832,.F.);
#1834=ORIENTED_EDGE('',*,*,#47,.F.);
#1835=ORIENTED_EDGE('',*,*,#1775,.F.);
#1836=EDGE_LOOP('',(#1810,#1811,#1819,#1827,#1833,#1834,#1835));
#1837=FACE_BOUND('',#1836,.T.);
#1838=ADVANCED_FACE('F1096',(#1837),#1809,.T.);
#1839=CARTESIAN_POINT('',(21.6,26.9000000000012,-1.));
#1840=CARTESIAN_POINT('',(21.6,25.9971053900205,-1.00543735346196));
#1841=CARTESIAN_POINT('',(21.6,25.241687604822,-1.5));
#1842=CARTESIAN_POINT('',(21.7963495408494,26.9000000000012,-1.));
#1843=CARTESIAN_POINT('',(21.794214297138,25.9971053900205,-1.00543735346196));
#1844=CARTESIAN_POINT('',(21.6,25.241687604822,-1.5));
#1845=CARTESIAN_POINT('',(21.9952426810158,26.9000000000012,-1.10475731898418));
#1846=CARTESIAN_POINT('',(21.990944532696,25.9971053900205,-1.10905546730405));
#1847=CARTESIAN_POINT('',(21.6,25.241687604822,-1.5));
#1848=CARTESIAN_POINT('',(22.1,26.9000000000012,-1.30365045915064));
#1849=CARTESIAN_POINT('',(22.0945626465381,25.9971053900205,-1.30578570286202));
#1850=CARTESIAN_POINT('',(21.6,25.241687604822,-1.5));
#1851=CARTESIAN_POINT('',(22.1,26.9000000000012,-1.5));
#1852=CARTESIAN_POINT('',(22.0945626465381,25.9971053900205,-1.5));
#1853=CARTESIAN_POINT('',(21.6,25.241687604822,-1.5));
#1854=B_SPLINE_SURFACE_WITH_KNOTS('',4,2,((#1839,#1840,#1841),(#1842,#1843,#1844),(#1845,#1846,
#1847),(#1848,#1849,#1850),(#1851,#1852,#1853)),.UNSPECIFIED.,.F.,.F.,.F.,(5,5),(3,3),(0.,1.),
(0.,1.),.UNSPECIFIED.);
#1855=CARTESIAN_POINT('',(21.6,26.9,-1.00000000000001));
#1856=CARTESIAN_POINT('',(21.608185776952,26.9,-0.999999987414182));
#1857=CARTESIAN_POINT('',(21.6163713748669,26.9,-1.00020482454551));
#1858=CARTESIAN_POINT('',(21.6327293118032,26.9,-1.00102038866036));
#1859=CARTESIAN_POINT('',(21.6409016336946,26.9,-1.00163145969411));
#1860=CARTESIAN_POINT('',(21.6572103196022,26.9,-1.00325608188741));
#1861=CARTESIAN_POINT('',(21.665346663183,26.9,-1.00426983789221));
#1862=CARTESIAN_POINT('',(21.6815614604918,26.9000000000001,-1.00669572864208));
#1863=CARTESIAN_POINT('',(21.6896399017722,26.9000000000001,-1.00810794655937));
#1864=CARTESIAN_POINT('',(21.7057175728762,26.9000000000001,-1.01132599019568));
#1865=CARTESIAN_POINT('',(21.7137168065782,26.9000000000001,-1.01313179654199));
#1866=CARTESIAN_POINT('',(21.7296153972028,26.9000000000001,-1.0171315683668));
#1867=CARTESIAN_POINT('',(21.7375147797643,26.9000000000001,-1.01932543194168));
#1868=CARTESIAN_POINT('',(21.753193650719,26.9000000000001,-1.02409519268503));
#1869=CARTESIAN_POINT('',(21.7609731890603,26.9000000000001,-1.02667092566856));
#1870=CARTESIAN_POINT('',(21.7763930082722,26.9000000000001,-1.03219762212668));
#1871=CARTESIAN_POINT('',(21.7840333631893,26.9000000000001,-1.03514837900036));
#1872=CARTESIAN_POINT('',(21.7991561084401,26.9000000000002,-1.04141764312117));
#1873=CARTESIAN_POINT('',(21.8066385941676,26.9000000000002,-1.04473592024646));
#1874=CARTESIAN_POINT('',(21.8214275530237,26.9000000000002,-1.05173206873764));
#1875=CARTESIAN_POINT('',(21.8287341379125,26.9000000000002,-1.05540970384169));
#1876=CARTESIAN_POINT('',(21.8431539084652,26.9000000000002,-1.06311573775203));
#1877=CARTESIAN_POINT('',(21.8502672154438,26.9000000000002,-1.06714390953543));
#1878=CARTESIAN_POINT('',(21.8642837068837,26.9000000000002,-1.07554151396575));
#1879=CARTESIAN_POINT('',(21.8711870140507,26.9000000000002,-1.07991074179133));
#1880=CARTESIAN_POINT('',(21.8847674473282,26.9000000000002,-1.08898028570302));
#1881=CARTESIAN_POINT('',(21.8914446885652,26.9000000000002,-1.09368042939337));
#1882=CARTESIAN_POINT('',(21.9045575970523,26.9000000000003,-1.10340096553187));
#1883=CARTESIAN_POINT('',(21.910993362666,26.9000000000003,-1.108421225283));
#1884=CARTESIAN_POINT('',(21.9236085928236,26.9000000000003,-1.11877049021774));
#1885=CARTESIAN_POINT('',(21.9297881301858,26.9000000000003,-1.124099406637));
#1886=CARTESIAN_POINT('',(21.941876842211,26.9000000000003,-1.13505382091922));
#1887=CARTESIAN_POINT('',(21.9477860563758,26.9000000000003,-1.14067927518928));
#1888=CARTESIAN_POINT('',(21.9593207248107,26.9000000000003,-1.15221394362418));
#1889=CARTESIAN_POINT('',(21.9649461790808,26.9000000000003,-1.158123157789));
#1890=CARTESIAN_POINT('',(21.975900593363,26.9000000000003,-1.17021186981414));
#1891=CARTESIAN_POINT('',(21.9812295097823,26.9000000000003,-1.17639140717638));
#1892=CARTESIAN_POINT('',(21.991578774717,26.9000000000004,-1.18900663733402));
#1893=CARTESIAN_POINT('',(21.9965990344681,26.9000000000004,-1.19544240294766));
#1894=CARTESIAN_POINT('',(22.0063195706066,26.9000000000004,-1.2085553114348));
#1895=CARTESIAN_POINT('',(22.011019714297,26.9000000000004,-1.21523255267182));
#1896=CARTESIAN_POINT('',(22.0200892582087,26.9000000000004,-1.22881298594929));
#1897=CARTESIAN_POINT('',(22.0244584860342,26.9000000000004,-1.23571629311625));
#1898=CARTESIAN_POINT('',(22.0328560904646,26.9000000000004,-1.24973278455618));
#1899=CARTESIAN_POINT('',(22.036884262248,26.9000000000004,-1.25684609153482));
#1900=CARTESIAN_POINT('',(22.0445902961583,26.9000000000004,-1.27126586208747));
#1901=CARTESIAN_POINT('',(22.0482679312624,26.9000000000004,-1.27857244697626));
#1902=CARTESIAN_POINT('',(22.0552640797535,26.9000000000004,-1.2933614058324));
#1903=CARTESIAN_POINT('',(22.0585823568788,26.9000000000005,-1.30084389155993));
#1904=CARTESIAN_POINT('',(22.0648516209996,26.9000000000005,-1.31596663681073));
#1905=CARTESIAN_POINT('',(22.0678023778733,26.9000000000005,-1.32360699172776));
#1906=CARTESIAN_POINT('',(22.0733290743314,26.9000000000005,-1.33902681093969));
#1907=CARTESIAN_POINT('',(22.075904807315,26.9000000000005,-1.34680634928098));
#1908=CARTESIAN_POINT('',(22.0806745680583,26.9000000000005,-1.36248522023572));
#1909=CARTESIAN_POINT('',(22.0828684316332,26.9000000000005,-1.37038460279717));
#1910=CARTESIAN_POINT('',(22.086868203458,26.9000000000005,-1.38628319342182));
#1911=CARTESIAN_POINT('',(22.0886740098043,26.9000000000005,-1.39428242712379));
#1912=CARTESIAN_POINT('',(22.0918920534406,26.9000000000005,-1.4103600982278));
#1913=CARTESIAN_POINT('',(22.0933042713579,26.9000000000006,-1.41843853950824));
#1914=CARTESIAN_POINT('',(22.0957301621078,26.9000000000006,-1.43465333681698));
#1915=CARTESIAN_POINT('',(22.0967439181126,26.9000000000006,-1.44278968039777));
#1916=CARTESIAN_POINT('',(22.0983685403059,26.9000000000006,-1.45909836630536));
#1917=CARTESIAN_POINT('',(22.0989796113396,26.9000000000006,-1.46727068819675));
#1918=CARTESIAN_POINT('',(22.0997951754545,26.9000000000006,-1.48362862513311));
#1919=CARTESIAN_POINT('',(22.1000000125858,26.9000000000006,-1.49181422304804));
#1920=CARTESIAN_POINT('',(22.1,26.9000000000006,-1.5));
#1921=B_SPLINE_CURVE_WITH_KNOTS('',3,(#1855,#1856,#1857,#1858,#1859,#1860,#1861,#1862,#1863,
#1864,#1865,#1866,#1867,#1868,#1869,#1870,#1871,#1872,#1873,#1874,#1875,#1876,#1877,#1878,#1879,
#1880,#1881,#1882,#1883,#1884,#1885,#1886,#1887,#1888,#1889,#1890,#1891,#1892,#1893,#1894,#1895,
#1896,#1897,#1898,#1899,#1900,#1901,#1902,#1903,#1904,#1905,#1906,#1907,#1908,#1909,#1910,#1911,
#1912,#1913,#1914,#1915,#1916,#1917,#1918,#1919,#1920),.UNSPECIFIED.,.F.,.F.,(4,2,2,2,2,2,2,2,2,
2,2,2,2,2,2,2,2,2,2,2,2,2,2,2,2,2,2,2,2,2,2,2,4),(0.,0.0245545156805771,0.0491298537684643,
0.0737177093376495,0.0983107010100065,0.122902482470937,0.147487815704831,0.172062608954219,
0.196623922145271,0.221169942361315,0.245699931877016,0.270214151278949,0.294713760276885,
0.319200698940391,0.343677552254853,0.368147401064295,0.392613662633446,0.417079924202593,
0.441549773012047,0.466026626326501,0.490513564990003,0.515013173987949,0.539527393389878,
0.564057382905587,0.588603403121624,0.613164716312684,0.637739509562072,0.662324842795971,
0.686916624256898,0.711509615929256,0.736097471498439,0.760672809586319,0.785227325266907),.UNSPECIFIED.);
#1922=EDGE_CURVE('E29',#1825,#161,#1921,.T.);
#1923=CARTESIAN_POINT('',(21.6,25.241687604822,-1.5));
#1924=CARTESIAN_POINT('',(21.6,25.2723198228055,-1.4799445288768));
#1925=CARTESIAN_POINT('',(21.6,25.3032848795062,-1.46039528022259));
#1926=CARTESIAN_POINT('',(21.6,25.3658678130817,-1.42235386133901));
#1927=CARTESIAN_POINT('',(21.6,25.3974858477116,-1.40386195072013));
#1928=CARTESIAN_POINT('',(21.6,25.4613447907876,-1.36799087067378));
#1929=CARTESIAN_POINT('',(21.6,25.4935856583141,-1.3506116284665));
#1930=CARTESIAN_POINT('',(21.6,25.5586569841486,-1.31701474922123));
#1931=CARTESIAN_POINT('',(21.6,25.5914872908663,-1.30079681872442));
#1932=CARTESIAN_POINT('',(21.6,25.657702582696,-1.26956516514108));
#1933=CARTESIAN_POINT('',(21.6,25.6910873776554,-1.25455103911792));
#1934=CARTESIAN_POINT('',(21.6,25.7583746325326,-1.22576306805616));
#1935=CARTESIAN_POINT('',(21.6,25.7922769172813,-1.21198881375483));
#1936=CARTESIAN_POINT('',(21.6,25.8605601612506,-1.1857101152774));
#1937=CARTESIAN_POINT('',(21.6,25.8949409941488,-1.17320534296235));
#1938=CARTESIAN_POINT('',(21.6,25.964140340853,-1.14948854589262));
#1939=CARTESIAN_POINT('',(21.6,25.998958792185,-1.13827633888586));
#1940=CARTESIAN_POINT('',(21.6,26.0689904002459,-1.11716101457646));
#1941=CARTESIAN_POINT('',(21.6,26.1042035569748,-1.10725789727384));
#1942=CARTESIAN_POINT('',(21.6,26.1749796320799,-1.08877051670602));
#1943=CARTESIAN_POINT('',(21.6,26.210542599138,-1.08018643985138));
#1944=CARTESIAN_POINT('',(21.6,26.2819713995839,-1.06434037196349));
#1945=CARTESIAN_POINT('',(21.6,26.3178373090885,-1.05707872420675));
#1946=CARTESIAN_POINT('',(21.6,26.3898231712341,-1.04387427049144));
#1947=CARTESIAN_POINT('',(21.6,26.4259432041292,-1.03793190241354));
#1948=CARTESIAN_POINT('',(21.6,26.4983865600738,-1.02735640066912));
#1949=CARTESIAN_POINT('',(21.6,26.5347099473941,-1.02272370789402));
#1950=CARTESIAN_POINT('',(21.6,26.6075074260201,-1.01475157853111));
#1951=CARTESIAN_POINT('',(21.6,26.6439815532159,-1.01141247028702));
#1952=CARTESIAN_POINT('',(21.6,26.717025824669,-1.00600567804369));
#1953=CARTESIAN_POINT('',(21.6,26.7535959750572,-1.00393807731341));
#1954=CARTESIAN_POINT('',(21.6,26.8267766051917,-1.00104524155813));
#1955=CARTESIAN_POINT('',(21.6,26.8633870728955,-1.00021970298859));
#1956=CARTESIAN_POINT('',(21.6,26.9,-1.00000000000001));
#1957=B_SPLINE_CURVE_WITH_KNOTS('',3,(#1923,#1924,#1925,#1926,#1927,#1928,#1929,#1930,#1931,
#1932,#1933,#1934,#1935,#1936,#1937,#1938,#1939,#1940,#1941,#1942,#1943,#1944,#1945,#1946,#1947,
#1948,#1949,#1950,#1951,#1952,#1953,#1954,#1955,#1956),.UNSPECIFIED.,.F.,.F.,(4,2,2,2,2,2,2,2,2,
2,2,2,2,2,2,2,4),(0.,0.109837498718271,0.219701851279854,0.32955901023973,0.439388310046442,
0.549180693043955,0.658936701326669,0.768664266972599,0.878376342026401,0.988088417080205,
1.09781598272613,1.20757199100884,1.31736437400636,1.42719367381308,1.53705083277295,
1.64691518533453,1.7567526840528),.UNSPECIFIED.);
#1958=EDGE_CURVE('E193',#1825,#122,#1957,.F.);
#1959=ORIENTED_EDGE('',*,*,#1922,.T.);
#1960=ORIENTED_EDGE('',*,*,#162,.T.);
#1961=ORIENTED_EDGE('',*,*,#1958,.F.);
#1962=EDGE_LOOP('',(#1959,#1960,#1961));
#1963=FACE_BOUND('',#1962,.T.);
#1964=ADVANCED_FACE('F700',(#1963),#1854,.T.);
#1965=CARTESIAN_POINT('',(21.6,30.758312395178,-1.5));
#1966=DIRECTION('',(0.,1.,0.));
#1967=DIRECTION('',(0.,0.,1.));
#1968=AXIS2_PLACEMENT_3D('',#1965,#1966,#1967);
#1969=CYLINDRICAL_SURFACE('',#1968,0.5);
#1970=CARTESIAN_POINT('',(22.1,29.1,-1.5));
#1971=CARTESIAN_POINT('',(22.1000000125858,29.1,-1.49181422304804));
#1972=CARTESIAN_POINT('',(22.0997951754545,29.1,-1.48362862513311));
#1973=CARTESIAN_POINT('',(22.0989796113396,29.1,-1.46727068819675));
#1974=CARTESIAN_POINT('',(22.0983685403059,29.1,-1.45909836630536));
#1975=CARTESIAN_POINT('',(22.0967439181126,29.1,-1.44278968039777));
#1976=CARTESIAN_POINT('',(22.0957301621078,29.1,-1.43465333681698));
#1977=CARTESIAN_POINT('',(22.0933042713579,29.1,-1.41843853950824));
#1978=CARTESIAN_POINT('',(22.0918920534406,29.1,-1.41036009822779));
#1979=CARTESIAN_POINT('',(22.0886740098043,29.1,-1.39428242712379));
#1980=CARTESIAN_POINT('',(22.086868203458,29.1,-1.38628319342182));
#1981=CARTESIAN_POINT('',(22.0828684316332,29.1,-1.37038460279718));
#1982=CARTESIAN_POINT('',(22.0806745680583,29.1,-1.36248522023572));
#1983=CARTESIAN_POINT('',(22.075904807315,29.1,-1.34680634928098));
#1984=CARTESIAN_POINT('',(22.0733290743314,29.1,-1.33902681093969));
#1985=CARTESIAN_POINT('',(22.0678023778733,29.1,-1.32360699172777));
#1986=CARTESIAN_POINT('',(22.0648516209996,29.1,-1.31596663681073));
#1987=CARTESIAN_POINT('',(22.0585823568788,29.1,-1.30084389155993));
#1988=CARTESIAN_POINT('',(22.0552640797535,29.1,-1.2933614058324));
#1989=CARTESIAN_POINT('',(22.0482679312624,29.1,-1.27857244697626));
#1990=CARTESIAN_POINT('',(22.0445902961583,29.1,-1.27126586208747));
#1991=CARTESIAN_POINT('',(22.036884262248,29.1,-1.25684609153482));
#1992=CARTESIAN_POINT('',(22.0328560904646,29.1,-1.24973278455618));
#1993=CARTESIAN_POINT('',(22.0244584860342,29.1,-1.23571629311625));
#1994=CARTESIAN_POINT('',(22.0200892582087,29.1,-1.22881298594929));
#1995=CARTESIAN_POINT('',(22.011019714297,29.1,-1.21523255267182));
#1996=CARTESIAN_POINT('',(22.0063195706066,29.1,-1.2085553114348));
#1997=CARTESIAN_POINT('',(21.9965990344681,29.1,-1.19544240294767));
#1998=CARTESIAN_POINT('',(21.991578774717,29.1,-1.18900663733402));
#1999=CARTESIAN_POINT('',(21.9812295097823,29.1,-1.17639140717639));
#2000=CARTESIAN_POINT('',(21.975900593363,29.1,-1.17021186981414));
#2001=CARTESIAN_POINT('',(21.9649461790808,29.1,-1.158123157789));
#2002=CARTESIAN_POINT('',(21.9593207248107,29.1,-1.15221394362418));
#2003=CARTESIAN_POINT('',(21.9477860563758,29.1,-1.14067927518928));
#2004=CARTESIAN_POINT('',(21.941876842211,29.1,-1.13505382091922));
#2005=CARTESIAN_POINT('',(21.9297881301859,29.1,-1.124099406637));
#2006=CARTESIAN_POINT('',(21.9236085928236,29.1,-1.11877049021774));
#2007=CARTESIAN_POINT('',(21.910993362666,29.1,-1.108421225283));
#2008=CARTESIAN_POINT('',(21.9045575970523,29.1,-1.10340096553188));
#2009=CARTESIAN_POINT('',(21.8914446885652,29.1,-1.09368042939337));
#2010=CARTESIAN_POINT('',(21.8847674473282,29.1,-1.08898028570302));
#2011=CARTESIAN_POINT('',(21.8711870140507,29.1,-1.07991074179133));
#2012=CARTESIAN_POINT('',(21.8642837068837,29.1,-1.07554151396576));
#2013=CARTESIAN_POINT('',(21.8502672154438,29.1,-1.06714390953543));
#2014=CARTESIAN_POINT('',(21.8431539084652,29.1,-1.06311573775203));
#2015=CARTESIAN_POINT('',(21.8287341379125,29.1,-1.05540970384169));
#2016=CARTESIAN_POINT('',(21.8214275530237,29.1,-1.05173206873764));
#2017=CARTESIAN_POINT('',(21.8066385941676,29.1,-1.04473592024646));
#2018=CARTESIAN_POINT('',(21.7991561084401,29.1,-1.04141764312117));
#2019=CARTESIAN_POINT('',(21.7840333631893,29.1,-1.03514837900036));
#2020=CARTESIAN_POINT('',(21.7763930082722,29.1,-1.03219762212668));
#2021=CARTESIAN_POINT('',(21.7609731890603,29.1,-1.02667092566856));
#2022=CARTESIAN_POINT('',(21.753193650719,29.1,-1.02409519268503));
#2023=CARTESIAN_POINT('',(21.7375147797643,29.1,-1.01932543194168));
#2024=CARTESIAN_POINT('',(21.7296153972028,29.1,-1.0171315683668));
#2025=CARTESIAN_POINT('',(21.7137168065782,29.1,-1.01313179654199));
#2026=CARTESIAN_POINT('',(21.7057175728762,29.1,-1.01132599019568));
#2027=CARTESIAN_POINT('',(21.6896399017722,29.1,-1.00810794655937));
#2028=CARTESIAN_POINT('',(21.6815614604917,29.1,-1.00669572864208));
#2029=CARTESIAN_POINT('',(21.665346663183,29.1,-1.00426983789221));
#2030=CARTESIAN_POINT('',(21.6572103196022,29.1,-1.00325608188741));
#2031=CARTESIAN_POINT('',(21.6409016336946,29.1,-1.00163145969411));
#2032=CARTESIAN_POINT('',(21.6327293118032,29.1,-1.00102038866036));
#2033=CARTESIAN_POINT('',(21.6163713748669,29.1,-1.00020482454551));
#2034=CARTESIAN_POINT('',(21.608185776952,29.1,-0.999999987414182));
#2035=CARTESIAN_POINT('',(21.6,29.1,-1.00000000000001));
#2036=B_SPLINE_CURVE_WITH_KNOTS('',3,(#1970,#1971,#1972,#1973,#1974,#1975,#1976,#1977,#1978,
#1979,#1980,#1981,#1982,#1983,#1984,#1985,#1986,#1987,#1988,#1989,#1990,#1991,#1992,#1993,#1994,
#1995,#1996,#1997,#1998,#1999,#2000,#2001,#2002,#2003,#2004,#2005,#2006,#2007,#2008,#2009,#2010,
#2011,#2012,#2013,#2014,#2015,#2016,#2017,#2018,#2019,#2020,#2021,#2022,#2023,#2024,#2025,#2026,
#2027,#2028,#2029,#2030,#2031,#2032,#2033,#2034,#2035),.UNSPECIFIED.,.F.,.F.,(4,2,2,2,2,2,2,2,2,
2,2,2,2,2,2,2,2,2,2,2,2,2,2,2,2,2,2,2,2,2,2,2,4),(0.,0.0245545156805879,0.0491298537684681,
0.0737177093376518,0.0983107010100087,0.122902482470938,0.147487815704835,0.172062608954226,
0.196623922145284,0.221169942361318,0.245699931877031,0.270214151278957,0.294713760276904,
0.319200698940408,0.343677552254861,0.368147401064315,0.39261366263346,0.417079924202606,
0.441549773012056,0.466026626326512,0.490513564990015,0.51501317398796,0.539527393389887,
0.564057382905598,0.588603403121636,0.613164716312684,0.637739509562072,0.662324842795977,
0.686916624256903,0.711509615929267,0.736097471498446,0.760672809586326,0.785227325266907),.UNSPECIFIED.);
#2037=EDGE_CURVE('E576',#1817,#169,#2036,.F.);
#2038=ORIENTED_EDGE('',*,*,#2037,.T.);
#2039=ORIENTED_EDGE('',*,*,#170,.F.);
#2040=ORIENTED_EDGE('',*,*,#1922,.F.);
#2041=ORIENTED_EDGE('',*,*,#1826,.T.);
#2042=EDGE_LOOP('',(#2038,#2039,#2040,#2041));
#2043=FACE_BOUND('',#2042,.T.);
#2044=ADVANCED_FACE('F691',(#2043),#1969,.F.);
#2045=CARTESIAN_POINT('',(21.6,30.758312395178,-1.5));
#2046=CARTESIAN_POINT('',(21.6,30.0028946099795,-1.00543735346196));
#2047=CARTESIAN_POINT('',(21.6,29.0999999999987,-1.));
#2048=CARTESIAN_POINT('',(21.6,30.758312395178,-1.5));
#2049=CARTESIAN_POINT('',(21.794214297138,30.0028946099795,-1.00543735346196));
#2050=CARTESIAN_POINT('',(21.7963495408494,29.0999999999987,-1.));
#2051=CARTESIAN_POINT('',(21.6,30.758312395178,-1.5));
#2052=CARTESIAN_POINT('',(21.990944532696,30.0028946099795,-1.10905546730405));
#2053=CARTESIAN_POINT('',(21.9952426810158,29.0999999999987,-1.10475731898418));
#2054=CARTESIAN_POINT('',(21.6,30.758312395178,-1.5));
#2055=CARTESIAN_POINT('',(22.0945626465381,30.0028946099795,-1.30578570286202));
#2056=CARTESIAN_POINT('',(22.1,29.0999999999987,-1.30365045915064));
#2057=CARTESIAN_POINT('',(21.6,30.758312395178,-1.5));
#2058=CARTESIAN_POINT('',(22.0945626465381,30.0028946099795,-1.5));
#2059=CARTESIAN_POINT('',(22.1,29.0999999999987,-1.5));
#2060=B_SPLINE_SURFACE_WITH_KNOTS('',4,2,((#2045,#2046,#2047),(#2048,#2049,#2050),(#2051,#2052,
#2053),(#2054,#2055,#2056),(#2057,#2058,#2059)),.UNSPECIFIED.,.F.,.F.,.F.,(5,5),(3,3),(0.,1.),
(0.,1.),.UNSPECIFIED.);
#2061=CARTESIAN_POINT('',(21.6,29.1,-1.00000000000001));
#2062=CARTESIAN_POINT('',(21.6,29.1366129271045,-1.00021970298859));
#2063=CARTESIAN_POINT('',(21.6,29.1732233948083,-1.00104524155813));
#2064=CARTESIAN_POINT('',(21.6,29.2464040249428,-1.00393807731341));
#2065=CARTESIAN_POINT('',(21.6,29.282974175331,-1.00600567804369));
#2066=CARTESIAN_POINT('',(21.6,29.3560184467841,-1.01141247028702));
#2067=CARTESIAN_POINT('',(21.6,29.3924925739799,-1.01475157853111));
#2068=CARTESIAN_POINT('',(21.6,29.4652900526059,-1.02272370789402));
#2069=CARTESIAN_POINT('',(21.6,29.5016134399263,-1.02735640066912));
#2070=CARTESIAN_POINT('',(21.6,29.5740567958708,-1.03793190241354));
#2071=CARTESIAN_POINT('',(21.6,29.6101768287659,-1.04387427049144));
#2072=CARTESIAN_POINT('',(21.6,29.6821626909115,-1.05707872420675));
#2073=CARTESIAN_POINT('',(21.6,29.7180286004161,-1.06434037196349));
#2074=CARTESIAN_POINT('',(21.6,29.789457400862,-1.08018643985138));
#2075=CARTESIAN_POINT('',(21.6,29.8250203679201,-1.08877051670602));
#2076=CARTESIAN_POINT('',(21.6,29.8957964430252,-1.10725789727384));
#2077=CARTESIAN_POINT('',(21.6,29.9310095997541,-1.11716101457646));
#2078=CARTESIAN_POINT('',(21.6,30.001041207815,-1.13827633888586));
#2079=CARTESIAN_POINT('',(21.6,30.035859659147,-1.14948854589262));
#2080=CARTESIAN_POINT('',(21.6,30.1050590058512,-1.17320534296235));
#2081=CARTESIAN_POINT('',(21.6,30.1394398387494,-1.1857101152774));
#2082=CARTESIAN_POINT('',(21.6,30.2077230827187,-1.21198881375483));
#2083=CARTESIAN_POINT('',(21.6,30.2416253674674,-1.22576306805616));
#2084=CARTESIAN_POINT('',(21.6,30.3089126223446,-1.25455103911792));
#2085=CARTESIAN_POINT('',(21.6,30.342297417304,-1.26956516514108));
#2086=CARTESIAN_POINT('',(21.6,30.4085127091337,-1.30079681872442));
#2087=CARTESIAN_POINT('',(21.6,30.4413430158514,-1.31701474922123));
#2088=CARTESIAN_POINT('',(21.6,30.5064143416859,-1.3506116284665));
#2089=CARTESIAN_POINT('',(21.6,30.5386552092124,-1.36799087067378));
#2090=CARTESIAN_POINT('',(21.6,30.6025141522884,-1.40386195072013));
#2091=CARTESIAN_POINT('',(21.6,30.6341321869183,-1.42235386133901));
#2092=CARTESIAN_POINT('',(21.6,30.6967151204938,-1.46039528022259));
#2093=CARTESIAN_POINT('',(21.6,30.7276801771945,-1.4799445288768));
#2094=CARTESIAN_POINT('',(21.6,30.758312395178,-1.5));
#2095=B_SPLINE_CURVE_WITH_KNOTS('',3,(#2061,#2062,#2063,#2064,#2065,#2066,#2067,#2068,#2069,
#2070,#2071,#2072,#2073,#2074,#2075,#2076,#2077,#2078,#2079,#2080,#2081,#2082,#2083,#2084,#2085,
#2086,#2087,#2088,#2089,#2090,#2091,#2092,#2093,#2094),.UNSPECIFIED.,.F.,.F.,(4,2,2,2,2,2,2,2,2,
2,2,2,2,2,2,2,4),(0.,0.10983749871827,0.21970185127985,0.329559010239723,0.439388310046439,
0.549180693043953,0.658936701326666,0.768664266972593,0.878376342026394,0.988088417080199,
1.09781598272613,1.20757199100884,1.31736437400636,1.42719367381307,1.53705083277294,
1.64691518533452,1.7567526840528),.UNSPECIFIED.);
#2096=EDGE_CURVE('E38',#208,#1817,#2095,.F.);
#2097=ORIENTED_EDGE('',*,*,#2096,.F.);
#2098=ORIENTED_EDGE('',*,*,#209,.T.);
#2099=ORIENTED_EDGE('',*,*,#2037,.F.);
#2100=EDGE_LOOP('',(#2097,#2098,#2099));
#2101=FACE_BOUND('',#2100,.T.);
#2102=ADVANCED_FACE('F643',(#2101),#2060,.T.);
#2103=CARTESIAN_POINT('',(15.4,26.9000000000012,-4.0000000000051));
#2104=DIRECTION('',(1.,0.,0.));
#2105=DIRECTION('',(0.,-4.17321392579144E-13,1.));
#2106=AXIS2_PLACEMENT_3D('',#2103,#2104,#2105);
#2107=CYLINDRICAL_SURFACE('',#2106,3.0000000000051);
#2108=ORIENTED_EDGE('',*,*,#1958,.T.);
#2109=ORIENTED_EDGE('',*,*,#123,.F.);
#2110=ORIENTED_EDGE('',*,*,#33,.F.);
#2111=ORIENTED_EDGE('',*,*,#1832,.T.);
#2112=EDGE_LOOP('',(#2108,#2109,#2110,#2111));
#2113=FACE_BOUND('',#2112,.T.);
#2114=ADVANCED_FACE('F188',(#2113),#2107,.F.);
#2115=CARTESIAN_POINT('',(15.4,29.0999999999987,-4.00000000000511));
#2116=DIRECTION('',(1.,0.,0.));
#2117=DIRECTION('',(0.,0.552770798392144,0.833333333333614));
#2118=AXIS2_PLACEMENT_3D('',#2115,#2116,#2117);
#2119=CYLINDRICAL_SURFACE('',#2118,3.0000000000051);
#2120=ORIENTED_EDGE('',*,*,#2096,.T.);
#2121=ORIENTED_EDGE('',*,*,#1818,.F.);
#2122=ORIENTED_EDGE('',*,*,#1793,.F.);
#2123=ORIENTED_EDGE('',*,*,#217,.T.);
#2124=EDGE_LOOP('',(#2120,#2121,#2122,#2123));
#2125=FACE_BOUND('',#2124,.T.);
#2126=ADVANCED_FACE('F631',(#2125),#2119,.F.);
#2127=CARTESIAN_POINT('',(0.,31.9999999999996,0.));
#2128=DIRECTION('',(0.,-1.,0.));
#2129=DIRECTION('',(0.,0.,-1.));
#2130=AXIS2_PLACEMENT_3D('',#2127,#2128,#2129);
#2131=TOROIDAL_SURFACE('',#2130,3.24999999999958,0.500000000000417);
#2132=ORIENTED_EDGE('',*,*,#1092,.F.);
#2133=ORIENTED_EDGE('',*,*,#859,.T.);
#2134=ORIENTED_EDGE('',*,*,#1064,.T.);
#2135=ORIENTED_EDGE('',*,*,#1001,.T.);
#2136=EDGE_LOOP('',(#2132,#2133,#2134,#2135));
#2137=FACE_BOUND('',#2136,.T.);
#2138=ADVANCED_FACE('F594',(#2137),#2131,.T.);
#2139=CARTESIAN_POINT('',(0.,24.0000000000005,0.));
#2140=DIRECTION('',(0.,-1.,0.));
#2141=DIRECTION('',(0.,0.,-1.));
#2142=AXIS2_PLACEMENT_3D('',#2139,#2140,#2141);
#2143=TOROIDAL_SURFACE('',#2142,3.24999999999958,0.500000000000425);
#2144=ORIENTED_EDGE('',*,*,#1109,.F.);
#2145=ORIENTED_EDGE('',*,*,#1116,.F.);
#2146=ORIENTED_EDGE('',*,*,#686,.T.);
#2147=ORIENTED_EDGE('',*,*,#1082,.T.);
#2148=ORIENTED_EDGE('',*,*,#745,.T.);
#2149=EDGE_LOOP('',(#2144,#2145,#2146,#2147,#2148));
#2150=FACE_BOUND('',#2149,.T.);
#2151=ADVANCED_FACE('F583',(#2150),#2143,.T.);
#2152=CARTESIAN_POINT('',(-4.6599009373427E-13,2.20743562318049E-12,0.));
#2153=DIRECTION('',(0.,-1.,0.));
#2154=DIRECTION('',(-1.,0.,0.));
#2155=AXIS2_PLACEMENT_3D('',#2152,#2153,#2154);
#2156=SPHERICAL_SURFACE('',#2155,6.00000000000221);
#2157=CARTESIAN_POINT('',(0.,-5.58107460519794,0.));
#2158=DIRECTION('',(0.,1.,0.));
#2159=DIRECTION('',(-1.,0.,0.));
#2160=AXIS2_PLACEMENT_3D('',#2157,#2158,#2159);
#2161=CIRCLE('',#2160,2.20263620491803);
#2162=CARTESIAN_POINT('',(-2.20263620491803,-5.58107460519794,0.));
#2163=VERTEX_POINT('',#2162);
#2164=EDGE_CURVE('E563',#2163,#2163,#2161,.F.);
#2165=ORIENTED_EDGE('',*,*,#2164,.T.);
#2166=EDGE_LOOP('',(#2165));
#2167=FACE_BOUND('',#2166,.T.);
#2168=ADVANCED_FACE('F593',(#2167),#2156,.T.);
#2169=CARTESIAN_POINT('',(0.,-4.2,0.));
#2170=DIRECTION('',(0.,1.,0.));
#2171=DIRECTION('',(0.,0.,-1.));
#2172=AXIS2_PLACEMENT_3D('',#2169,#2170,#2171);
#2173=CONICAL_SURFACE('',#2172,3.,0.523598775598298);
#2174=ORIENTED_EDGE('',*,*,#2164,.F.);
#2175=EDGE_LOOP('',(#2174));
#2176=FACE_BOUND('',#2175,.T.);
#2177=CARTESIAN_POINT('',(0.,-4.2,0.));
#2178=DIRECTION('',(0.,1.,0.));
#2179=DIRECTION('',(0.,0.,-1.));
#2180=AXIS2_PLACEMENT_3D('',#2177,#2178,#2179);
#2181=CIRCLE('',#2180,3.);
#2182=CARTESIAN_POINT('',(0.,-4.2,-3.));
#2183=VERTEX_POINT('',#2182);
#2184=EDGE_CURVE('E570',#2183,#2183,#2181,.F.);
#2185=ORIENTED_EDGE('',*,*,#2184,.T.);
#2186=EDGE_LOOP('',(#2185));
#2187=FACE_BOUND('',#2186,.T.);
#2188=ADVANCED_FACE('F1158',(#2176,#2187),#2173,.T.);
#2189=CARTESIAN_POINT('',(0.,-6.,0.));
#2190=DIRECTION('',(0.,-1.,0.));
#2191=DIRECTION('',(7.69327835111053E-10,0.,1.));
#2192=AXIS2_PLACEMENT_3D('',#2189,#2190,#2191);
#2193=CYLINDRICAL_SURFACE('',#2192,3.);
#2194=ORIENTED_EDGE('',*,*,#2184,.F.);
#2195=EDGE_LOOP('',(#2194));
#2196=FACE_BOUND('',#2195,.T.);
#2197=CARTESIAN_POINT('',(0.,6.,0.));
#2198=DIRECTION('',(0.,1.,0.));
#2199=DIRECTION('',(0.,0.,1.));
#2200=AXIS2_PLACEMENT_3D('',#2197,#2198,#2199);
#2201=CIRCLE('',#2200,3.);
#2202=CARTESIAN_POINT('',(0.,6.,3.));
#2203=VERTEX_POINT('',#2202);
#2204=EDGE_CURVE('E22',#2203,#2203,#2201,.F.);
#2205=ORIENTED_EDGE('',*,*,#2204,.T.);
#2206=EDGE_LOOP('',(#2205));
#2207=FACE_BOUND('',#2206,.T.);
#2208=ADVANCED_FACE('F1168',(#2196,#2207),#2193,.T.);
#2209=CARTESIAN_POINT('',(-2.8267949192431,6.,2.8267949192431));
#2210=DIRECTION('',(0.,1.,0.));
#2211=DIRECTION('',(1.,0.,0.));
#2212=AXIS2_PLACEMENT_3D('',#2209,#2210,#2211);
#2213=PLANE('',#2212);
#2214=ORIENTED_EDGE('',*,*,#2204,.F.);
#2215=EDGE_LOOP('',(#2214));
#2216=FACE_BOUND('',#2215,.T.);
#2217=CARTESIAN_POINT('',(0.,6.,0.));
#2218=DIRECTION('',(0.,-1.,0.));
#2219=DIRECTION('',(0.,0.,1.));
#2220=AXIS2_PLACEMENT_3D('',#2217,#2218,#2219);
#2221=CIRCLE('',#2220,2.);
#2222=CARTESIAN_POINT('',(0.,6.,2.));
#2223=VERTEX_POINT('',#2222);
#2224=EDGE_CURVE('E1199',#2223,#2223,#2221,.T.);
#2225=ORIENTED_EDGE('',*,*,#2224,.T.);
#2226=EDGE_LOOP('',(#2225));
#2227=FACE_BOUND('',#2226,.T.);
#2228=ADVANCED_FACE('F16',(#2216,#2227),#2213,.T.);
#2229=CARTESIAN_POINT('',(0.,-6.,0.));
#2230=DIRECTION('',(0.,-1.,0.));
#2231=DIRECTION('',(0.,0.,1.));
#2232=AXIS2_PLACEMENT_3D('',#2229,#2230,#2231);
#2233=CYLINDRICAL_SURFACE('',#2232,2.);
#2234=ORIENTED_EDGE('',*,*,#1127,.F.);
#2235=EDGE_LOOP('',(#2234));
#2236=FACE_BOUND('',#2235,.T.);
#2237=ORIENTED_EDGE('',*,*,#2224,.F.);
#2238=EDGE_LOOP('',(#2237));
#2239=FACE_BOUND('',#2238,.T.);
#2240=ADVANCED_FACE('F598',(#2236,#2239),#2233,.T.);
#2241=CLOSED_SHELL('',(#51,#260,#583,#794,#1005,#1023,#1041,#1053,#1068,#1096,#1131,#1209,#1219,
#1297,#1307,#1370,#1425,#1479,#1569,#1649,#1671,#1687,#1703,#1720,#1732,#1763,#1780,#1804,#1838,
#1964,#2044,#2102,#2114,#2126,#2138,#2151,#2168,#2188,#2208,#2228,#2240));
#2242=MANIFOLD_SOLID_BREP('B1',#2241);
#2243=ADVANCED_BREP_SHAPE_REPRESENTATION('',(#18,#2242),#14);
#2244=SHAPE_DEFINITION_REPRESENTATION(#9,#2243);
ENDSEC;
END-ISO-10303-21;
